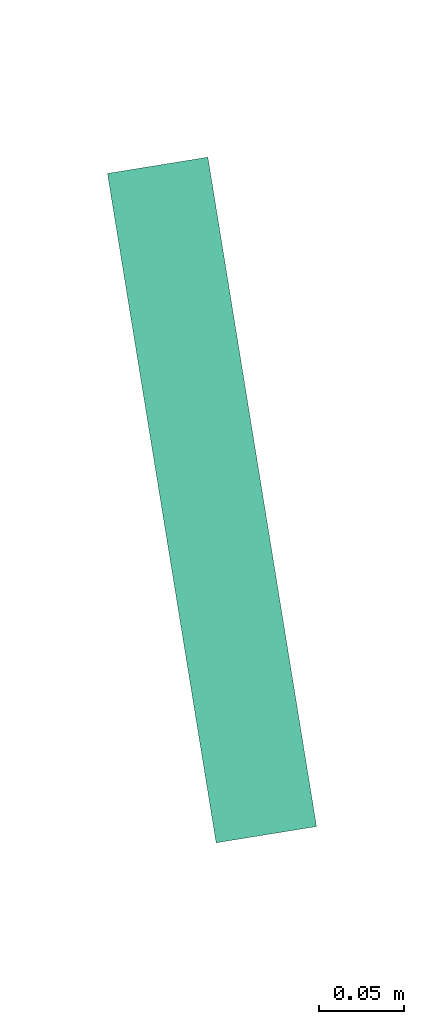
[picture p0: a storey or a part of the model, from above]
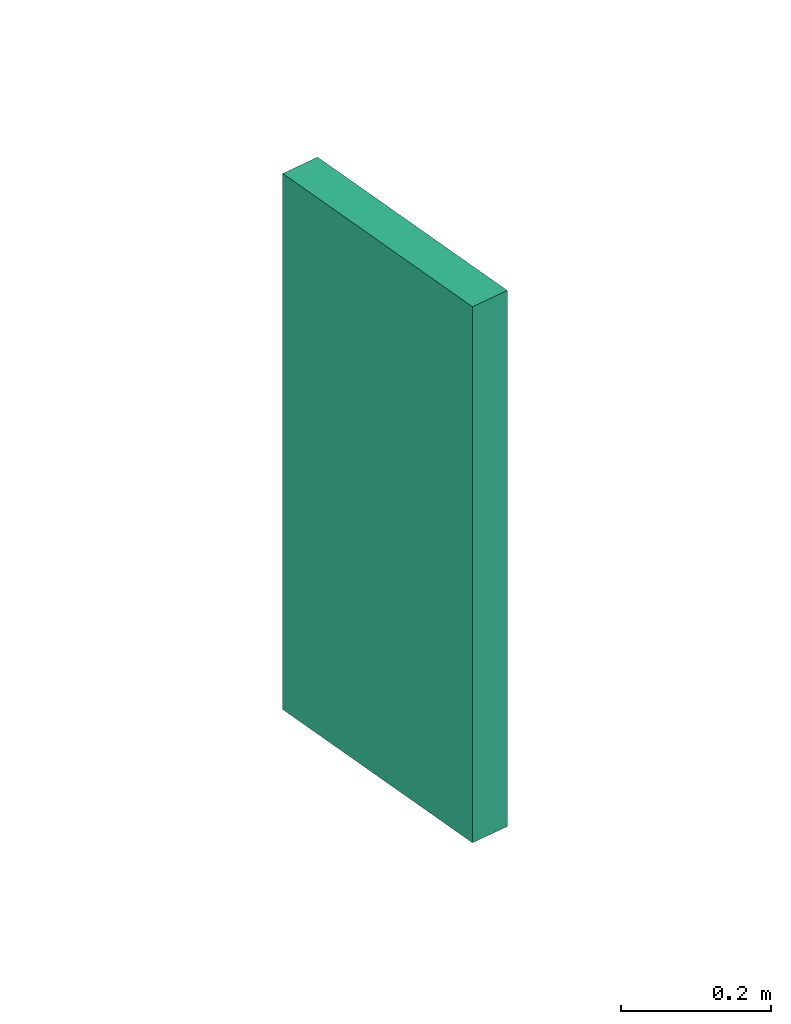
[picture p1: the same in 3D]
Properties of the parts of a building model (IFC2X3), part 1 of 3

# File
Description: ViewDefinition [CoordinationView_V2.0]
File name: BR003-350-101.1 (EDITED).ifc (Edited by Naviate Simple BIM 2022 version 6)
Time: 2026-03-27T09:04:17+01:00
Written by: ODA SDAI 24.12
Made in: Autodesk Revit 25.4.41.14 (ENU) - IFC 25.4.0.27

# IfcProject, 80052
LongName: T3 - Flesland; Phase: Som Bygget

# IfcSite (8)
RefElevation: 0 mm
Name | RefLatitude | RefLongitude
2 x Default | 60, 17, 20, 899658 | 5, 13, 37, 654037
3 x Default | 42, 24, 53, 508911 | -71, -15, -29, -58837
3 x Default | 59, 54, 49, 759826 | 10, 44, 19, 467315

# IfcBuilding (8)
Name
TOO | LongName: TOO
7 x 

# IfcBuildingStorey: Level:8mm Head (13)
Name | LongName | Elevation (mm)
Nivå B | Nivå B | 44700
7 x Nivå D | Nivå D | 51000
4 x Nivå C | Nivå C | 48160
Nivå E | Nivå E | 55630

# IfcBuildingStorey: Level:Kote Ny (3)
In: TOO
Name | LongName | Elevation (mm)
Nivå B | Nivå B | 44700
Nivå D-H01 | Nivå D-H01 | 51000
Himlingsplan Nivå E | Himlingsplan Nivå E | 55630

# IfcBeam: A223 - DLB Prefab. Betongbjelke:A223 - DLB Prefab. Betongbjelke - 815 x 700 x 400 mm (6)
In: Nivå D-H01
Type - PredefinedType: BEAM
ePset_Simplebim - Assembly Level: Leaf
ePset_SimplebimBasicQuantities - Height (Simplebim): 815 mm; Width (Simplebim): 700 mm
Pset_BeamCommon - Reference: A223 - DLB Prefab. Betongbjelke:A223 - DLB Prefab. Betongbjelke - 815 x 700 x 400 mm
Name (A223 - DLB Prefab. Betongbjelke:A223 - DLB Prefab. Betongbjelke - 815 x 700 x 400 mm:...) | Length (Simplebim) (mm) | Area, sides, net (Simplebim) (m2) | Volume, net (Simplebim) (m3) | Weight, as steel (Simplebim) (kg) | Splitting
28208053 | 8974.6 | 28.097 | 4.05652 | 31843.7 | ORIGINAL
28208110 | 8974.6 | 28.097 | 4.05652 | 31843.7 | ORIGINAL
28208108 | 5597 | 17.8638 | 2.52998 | 19860.3 | RESULT
23469193 | 767 | 3.22892 | 0.34682 | 2722.53 | RESULT
14871710 | 768 | 3.22892 | 0.34682 | 2722.53 | RESULT
28208055 | 5597 | 17.8638 | 2.52998 | 19860.3 | RESULT

# IfcBuildingElementProxy: 1612510-0001:Junction box1 (6)
In: Nivå D
Type - Material: <Unnamed>
ePset_Simplebim - Assembly Level: Leaf
ePset_LocationTool - Splitting: ORIGINAL
ePset_SimplebimBasicQuantities - Area, largest surface, net (Simplebim): 0.0121 m2; Volume, net (Simplebim): 0.000515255 m3; Length (Simplebim): 110 mm; Height (Simplebim): 110 mm; Thickness (Simplebim): 46 mm
Pset_BuildingElementProxyCommon - Reference: 1612510-0001:Junction box1
AVINOR - 08_Status: S4; 07_Fase: F90
Name (1612510-0001:Junction box1:...) | 05_ID-nummer
14241557 | +BR003=360.SB102-LC001
14241558 | +BR003=360.SB102-LC002
14241559 | +BR003=360.SB121-FA002
14241560 | +BR003=360.SB121-FA002
14241561 | +BR003=360.SB113-FA001
14296219 | +BR003=360.SB121-FA002 | Group: 5

# IfcBuildingElementProxy: 244 - Albuebryter:244 - Albuebryter (2)
In: Nivå D-H01
Type - Material: Ramme Plast, <Unnamed>
ePset_Simplebim - Assembly Level: Leaf
ePset_LocationTool - Splitting: ORIGINAL
ePset_SimplebimBasicQuantities - Area, largest surface, net (Simplebim): 0.0480408 m2; Volume, net (Simplebim): 0.000518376 m3; Thickness (Simplebim): 27.7678 mm; Height (Simplebim): 250 mm; Length (Simplebim): 79.9999 mm
Pset_BuildingElementProxyCommon - Reference: 244 - Albuebryter:244 - Albuebryter
Name (244 - Albuebryter:244 - Albuebryter:...)
37698599
37866248

# IfcBuildingElementProxy: 274-stikkontakt (306):274-stikkontakt (306) (2)
In: Nivå D-H01
Type - Material: <Unnamed>
ePset_Simplebim - Assembly Level: Leaf
Pset_BuildingElementProxyCommon - Reference: 274-stikkontakt (306):274-stikkontakt (306)
ePset_LocationTool - Splitting: ORIGINAL
ePset_SimplebimBasicQuantities - Volume, net (Simplebim): 0.00007225 m3; Height (Simplebim): 85 mm; Thickness (Simplebim): 10 mm; Area, largest surface, net (Simplebim): 0.007225 m2; Length (Simplebim): 85 mm
Name (274-stikkontakt (306):274-stikkontakt (306):...)
35439303
35460235

# IfcBuildingElementProxy: A275 - 3D FOLIE PIKTOGRAM HCWC:A275 - 3D FOLIE PIKTOGRAM HCWC, A275 - 3D FOLIE PIKTOGRAM HCWC:A275 - 3D FOLIE PIKTOGRAM HCWC:38297930
In: Nivå D-H01
Type - Material: <Unnamed>
ePset_Simplebim - Assembly Level: Leaf
ePset_LocationTool - Splitting: ORIGINAL
ePset_SimplebimBasicQuantities - Length (Simplebim): 300.595 mm; Height (Simplebim): 232.845 mm; Thickness (Simplebim): 48.6239 mm; Area, largest surface, net (Simplebim): 0.0134453 m2; Volume, net (Simplebim): 0.00022648 m3
Pset_BuildingElementProxyCommon - Reference: A275 - 3D FOLIE PIKTOGRAM HCWC:A275 - 3D FOLIE PIKTOGRAM HCWC

# IfcBuildingElementProxy: A275 - 3D FOLIE PIKTOGRAM stellebord:A275 - 3D FOLIE PIKTOGRAM stellebord, A275 - 3D FOLIE PIKTOGRAM stellebord:A275 - 3D FOLIE PIKTOGRAM stellebord:38650796
In: Nivå D-H01
Type - Material: <Unnamed>
ePset_Simplebim - Assembly Level: Leaf
ePset_LocationTool - Splitting: ORIGINAL
ePset_SimplebimBasicQuantities - Area, largest surface, net (Simplebim): 0.0115962 m2; Length (Simplebim): 241.472 mm; Volume, net (Simplebim): 0.000257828 m3; Height (Simplebim): 242.647 mm; Thickness (Simplebim): 37.4759 mm
Pset_BuildingElementProxyCommon - Reference: A275 - 3D FOLIE PIKTOGRAM stellebord:A275 - 3D FOLIE PIKTOGRAM stellebord

# IfcBuildingElementProxy: BRANNSPJELD - - SZ010T:BRANNSPJELD - FDT/R-1250-1000 - SZ010T, BRANNSPJELD - - SZ010T:BRANNSPJELD - FDT/R-1250-1000 - SZ010T:5717189
In: Nivå E
Type - Material: <Unnamed>
ePset_LocationTool - Splitting: ORIGINAL
ePset_Simplebim - Assembly Level: Leaf
AVINOR - 08_Status: S4; 07_Fase: F90; 05_ID-nummer: +BR003=360.SB110-SZ003
Pset_BuildingElementProxyCommon - Reference: BRANNSPJELD - - SZ010T:BRANNSPJELD - FDT/R-1250-1000 - SZ010T
ePset_SimplebimBasicQuantities - Area, largest surface, net (Simplebim): 1.24102 m2; Thickness (Simplebim): 996 mm; Height (Simplebim): 406 mm; Length (Simplebim): 1246 mm; Volume, net (Simplebim): 0.503852 m3
Group: 360.SB110 T

# IfcBuildingElementProxy: BRANNSPJELD - - SZ011T:BRANNSPJELD -C-EI60-125 - SZ011T, BRANNSPJELD - - SZ011T:BRANNSPJELD -C-EI60-125 - SZ011T:13399544
In: Nivå D
Type - Material: <Unnamed>
ePset_Simplebim - Assembly Level: Leaf
Pset_BuildingElementProxyCommon - Reference: BRANNSPJELD - - SZ011T:BRANNSPJELD -C-EI60-125 - SZ011T
ePset_LocationTool - Splitting: ORIGINAL
ePset_SimplebimBasicQuantities - Volume, net (Simplebim): 0.00323555 m3; Area, largest surface, net (Simplebim): 0.103933 m2; Height (Simplebim): 125 mm; Thickness (Simplebim): 125 mm; Length (Simplebim): 265 mm
AVINOR - 08_Status: S4; 07_Fase: F90; 05_ID-nummer: +BR003=360.SB113-SZ053
Group: 360.SB113 T

# IfcBuildingElementProxy: BRANNSPJELD - - SZ011T:BRANNSPJELD -C-EI60-200 - SZ011T, BRANNSPJELD - - SZ011T:BRANNSPJELD -C-EI60-200 - SZ011T:13404535
In: Nivå D
Type - Material: <Unnamed>
ePset_Simplebim - Assembly Level: Leaf
Pset_BuildingElementProxyCommon - Reference: BRANNSPJELD - - SZ011T:BRANNSPJELD -C-EI60-200 - SZ011T
AVINOR - 05_ID-nummer: +BR003=360.SB113-SZ010; 08_Status: S4; 07_Fase: F90
ePset_LocationTool - Splitting: ORIGINAL
ePset_SimplebimBasicQuantities - Volume, net (Simplebim): 0.00828302 m3; Area, largest surface, net (Simplebim): 0.166293 m2; Height (Simplebim): 200 mm; Thickness (Simplebim): 200 mm; Length (Simplebim): 265 mm
Group: 360.SB113 A

# IfcBuildingElementProxy: BRANNSPJELD - - SZ011T:BRANNSPJELD -C-EI60-500 - SZ011T (2)
In: Nivå D
Type - Material: <Unnamed>
ePset_Simplebim - Assembly Level: Leaf
ePset_SimplebimBasicQuantities - Area, largest surface, net (Simplebim): 0.701255 m2; Thickness (Simplebim): 447 mm; Length (Simplebim): 500 mm; Height (Simplebim): 500 mm; Volume, net (Simplebim): 0.0873233 m3
Pset_BuildingElementProxyCommon - Reference: BRANNSPJELD - - SZ011T:BRANNSPJELD -C-EI60-500 - SZ011T
ePset_LocationTool - Splitting: ORIGINAL
AVINOR - 08_Status: S4; 07_Fase: F90
Name (BRANNSPJELD - - SZ011T:BRANNSPJELD -C-EI60-500 - SZ011T:...) | 05_ID-nummer | Group
13271974 | +BR003=360.SB113-SZ049 | 360.SB113 T
13879327 | +BR003=360.SB113-SZ001 | 360.SB113 A

# IfcBuildingElementProxy: BRANNSPJELD - 1 - SZ010T:BRANNSPJELD -R E120-1000-1000 - SZ010T (2)
In: Nivå C
Type - Material: <Unnamed>
ePset_SimplebimBasicQuantities - Length (Simplebim): 996 mm; Thickness (Simplebim): 996 mm; Height (Simplebim): 396 mm; Volume, net (Simplebim): 0.392838 m3; Area, largest surface, net (Simplebim): 0.992016 m2
ePset_Simplebim - Assembly Level: Leaf
AVINOR - 08_Status: S4; 07_Fase: F90
Pset_BuildingElementProxyCommon - Reference: BRANNSPJELD - 1 - SZ010T:BRANNSPJELD -R E120-1000-1000 - SZ010T
ePset_LocationTool - Splitting: ORIGINAL
Name (BRANNSPJELD - 1 - SZ010T:BRANNSPJELD -R E120-1000-1000 - SZ010T:...) | 05_ID-nummer | Group
5561560 | +BR003=360.SB111-SZ001 | 360.SB111 A
5561591 | +BR003=360.SB112-SZ001 | 360.SB112 A

# IfcBuildingElementProxy: BRANNSPJELD - 1 - SZ06T:BRANNSPJELD -C-EI120-500 - SZ06T, BRANNSPJELD - 1 - SZ06T:BRANNSPJELD -C-EI120-500 - SZ06T:13082281
In: Nivå D
Type - Material: <Unnamed>
ePset_Simplebim - Assembly Level: Leaf
ePset_LocationTool - Splitting: ORIGINAL
Pset_BuildingElementProxyCommon - Reference: BRANNSPJELD - 1 - SZ06T:BRANNSPJELD -C-EI120-500 - SZ06T
AVINOR - 08_Status: S4; 07_Fase: F90; 05_ID-nummer: +BR003=360.SB113-SZ037
ePset_SimplebimBasicQuantities - Area, largest surface, net (Simplebim): 0.68942 m2; Height (Simplebim): 443 mm; Length (Simplebim): 496 mm; Thickness (Simplebim): 496 mm; Volume, net (Simplebim): 0.0851628 m3
Group: 360.SB113 T

# IfcBuildingElementProxy: Bryter 1-polet påvegg:2006015 (2)
In: Nivå D
Type - Material: Material1
ePset_LocationTool - Splitting: ORIGINAL
ePset_Simplebim - Assembly Level: Leaf
Pset_BuildingElementProxyCommon - Reference: Bryter 1-polet påvegg:2006015
AVINOR - 08_Status: S4; 07_Fase: F90; 05_ID-nummer: +BR003=439.OO001-XS001T
ePset_SimplebimBasicQuantities - Volume, net (Simplebim): 0.000041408 m3; Thickness (Simplebim): 12 mm; Length (Simplebim): 60 mm; Height (Simplebim): 60 mm; Area, largest surface, net (Simplebim): 0.0036 m2
Name (Bryter 1-polet påvegg:2006015:...)
14247189
14247595

# IfcBuildingElementProxy: Dobbel stikk i tak m_boks 2P+J PH:Earthed reces socket c2 (2)
In: Nivå D
Type - Material: <Unnamed>
ePset_Simplebim - Assembly Level: Leaf
ePset_LocationTool - Splitting: ORIGINAL
AVINOR - 08_Status: S4; 07_Fase: F90; 05_ID-nummer: +BR003=439.OO001-UE001T
ePset_SimplebimBasicQuantities - Area, largest surface, net (Simplebim): 0.010086 m2; Height (Simplebim): 19 mm; Thickness (Simplebim): 82 mm; Length (Simplebim): 123 mm; Volume, net (Simplebim): 0.000118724 m3
Pset_BuildingElementProxyCommon - Reference: Dobbel stikk i tak m_boks 2P+J PH:Earthed reces socket c2
Name (Dobbel stikk i tak m_boks 2P+J PH:Earthed reces socket c2:...) | Group
4070366 | =433.SD121-KW28
5570882 | =433.SD121-KW27

# IfcBuildingElementProxy: Dobbel stikk på vegg 2P+J hor PH:EARTHED-SOCKET-2(HOR) (5)
In: Nivå D
Type - Material: <Unnamed>
ePset_SimplebimBasicQuantities - Thickness (Simplebim): 45.1 mm; Length (Simplebim): 98.2 mm; Area, largest surface, net (Simplebim): 0.006174 m2; Height (Simplebim): 63.2 mm; Volume, net (Simplebim): 0.0000063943 m3
ePset_Simplebim - Assembly Level: Leaf
Pset_BuildingElementProxyCommon - Reference: Dobbel stikk på vegg 2P+J hor PH:EARTHED-SOCKET-2(HOR)
ePset_LocationTool - Splitting: ORIGINAL
AVINOR - 08_Status: S4; 07_Fase: F90; 05_ID-nummer: +BR003=439.OO001-UE001T
Name (Dobbel stikk på vegg 2P+J hor PH:EARTHED-SOCKET-2(HOR):...) | Group
14252326 | =433.SD121-KW67
14252465 | =433.SD121-KW67
14252483 | =433.SD121-KW67
14252511 | =433.SD121-KW67
18195576 | 6

# IfcBuildingElementProxy: Dobbel stikk vegg innf 2P+J vert PH:RECESSED-EARTHED-SOCKET-2(VER) (4)
In: Nivå D
Type - Material: Material3, Material2, Material1
ePset_Simplebim - Assembly Level: Leaf
ePset_LocationTool - Splitting: ORIGINAL
AVINOR - 08_Status: S4; 07_Fase: F90; 05_ID-nummer: +BR003=439.OO001-UE001T
Pset_BuildingElementProxyCommon - Reference: Dobbel stikk vegg innf 2P+J vert PH:RECESSED-EARTHED-SOCKET-2(VER)
ePset_SimplebimBasicQuantities - Volume, net (Simplebim): 0.000114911 m3; Length (Simplebim): 91.4039 mm; Area, largest surface, net (Simplebim): 0.00984 m2; Thickness (Simplebim): 83.0083 mm; Height (Simplebim): 103.761 mm
Name (Dobbel stikk vegg innf 2P+J vert PH:RECESSED-EARTHED-SOCKET-2(VER):...) | Group
6345599
15224680 | =433.SD121-KW149
18268836 | 8
18268866 | 7 | AVINOR - 01_Lufthavnkode: ENBR

# IfcBuildingElementProxy: Dome-camera-ceiling-0001:Dome camera ceiling, Dome-camera-ceiling-0001:Dome camera ceiling:7268528
In: Nivå D
Type - Material: <Unnamed>
ePset_Simplebim - Assembly Level: Leaf
Pset_BuildingElementProxyCommon - Reference: Dome-camera-ceiling-0001:Dome camera ceiling
ePset_SimplebimBasicQuantities - Height (Simplebim): 70 mm; Volume, net (Simplebim): 0.000340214 m3; Length (Simplebim): 100 mm; Thickness (Simplebim): 100 mm; Area, largest surface, net (Simplebim): 0.00942921 m2
AVINOR - 08_Status: S1; 07_Fase: F30
ePset_LocationTool - Splitting: ORIGINAL

# IfcBuildingElementProxy: El-ford-Skap:El-ford-Skap_001, El-ford-Skap:=435.SD121:14157169
In: Nivå D
Type - Material: <Unnamed>
ePset_Simplebim - Assembly Level: Leaf
AVINOR - 08_Status: S4; 07_Fase: F90; 05_ID-nummer: +BR003=435.SD121
ePset_LocationTool - Splitting: ORIGINAL
Pset_BuildingElementProxyCommon - Reference: El-ford-Skap:El-ford-Skap_001
ePset_SimplebimBasicQuantities - Area, largest surface, net (Simplebim): 1.2 m2; Thickness (Simplebim): 300 mm; Length (Simplebim): 600 mm; Height (Simplebim): 2000 mm; Volume, net (Simplebim): 0.36 m3
Group: 6; 5; 8; 7

# IfcBuildingElementProxy: Enkel stikk på vegg 2P+J IP44 PH:COVERED-SOCKET- 1, Enkel stikk på vegg 2P+J IP44 PH:COVERED-SOCKET- 1:4155008
In: Nivå D
Type - Material: <Unnamed>
ePset_Simplebim - Assembly Level: Leaf
ePset_LocationTool - Splitting: ORIGINAL
AVINOR - 08_Status: S4; 07_Fase: F90; 05_ID-nummer: +BR003=439.OO001-UE001T
ePset_SimplebimBasicQuantities - Thickness (Simplebim): 55.1845 mm; Area, largest surface, net (Simplebim): 0.002516 m2; Height (Simplebim): 87.4696 mm; Volume, net (Simplebim): 0.00000428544 m3; Length (Simplebim): 68.5963 mm
Pset_BuildingElementProxyCommon - Reference: Enkel stikk på vegg 2P+J IP44 PH:COVERED-SOCKET- 1
Group: =433.SD121-KW29

# IfcBuildingElementProxy: Enkel stikk på vegg 2P+J PH:EARTHED-SOCKET-1 (3)
In: Nivå D
Type - Material: Material3, Material2, Material1
ePset_Simplebim - Assembly Level: Leaf
Pset_BuildingElementProxyCommon - Reference: Enkel stikk på vegg 2P+J PH:EARTHED-SOCKET-1
ePset_SimplebimBasicQuantities - Volume, net (Simplebim): 0.000137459 m3; Thickness (Simplebim): 45.0114 mm; Height (Simplebim): 63 mm; Length (Simplebim): 63 mm; Area, largest surface, net (Simplebim): 0.003969 m2
AVINOR - 08_Status: S4; 07_Fase: F90; 05_ID-nummer: +BR003=439.OO001-UE001T
ePset_LocationTool - Splitting: ORIGINAL
Name (Enkel stikk på vegg 2P+J PH:EARTHED-SOCKET-1:...) | Group
5560765 | =433.SD121-KW59
5560766 | =433.SD121-KW30
14432721

# IfcBuildingElementProxy: FANCOIL--LC006T:FANCOIL--LC006T (2)
In: Nivå D
Type - Material: <Unnamed>
ePset_Simplebim - Assembly Level: Leaf
AVINOR - 08_Status: S4; 07_Fase: F90
ePset_LocationTool - Splitting: ORIGINAL
Pset_BuildingElementProxyCommon - Reference: FANCOIL--LC006T:FANCOIL--LC006T
ePset_SimplebimBasicQuantities - Volume, net (Simplebim): 0.126 m3; Height (Simplebim): 350 mm; Length (Simplebim): 600 mm; Thickness (Simplebim): 600 mm; Area, largest surface, net (Simplebim): 0.36 m2
Group: 370.SB102 T
Name (FANCOIL--LC006T:FANCOIL--LC006T:...) | 05_ID-nummer
21083713 | +BR003=370.SB102-LC001
21083752 | +BR003=370.SB102-LC002

# IfcBuildingElementProxy: Høyttaler innfelt 16cm:Bass speaker PC-2369EN /6W (4)
In: Nivå D
Type - Material: Material1, Material2
ePset_Simplebim - Assembly Level: Leaf
ePset_LocationTool - Splitting: ORIGINAL
ePset_SimplebimBasicQuantities - Area, largest surface, net (Simplebim): 0.0479856 m2; Length (Simplebim): 242.889 mm; Height (Simplebim): 170.098 mm; Volume, net (Simplebim): 0.00448694 m3; Thickness (Simplebim): 229.877 mm
AVINOR - 08_Status: S1; 07_Fase: F30
Pset_BuildingElementProxyCommon - Reference: Høyttaler innfelt 16cm:Bass speaker PC-2369EN /6W
Name (Høyttaler innfelt 16cm:Bass speaker PC-2369EN /6W:...)
7046618
7046619
7046620
7046621

# IfcBuildingElementProxy: Høyttaler line array:TOA Sr-S4s, Høyttaler line array:TOA Sr-S4s:10112814
In: Nivå D
Type - Material: <Unnamed>
ePset_Simplebim - Assembly Level: Leaf
ePset_LocationTool - Splitting: ORIGINAL
ePset_SimplebimBasicQuantities - Area, largest surface, net (Simplebim): 0.270276 m2; Volume, net (Simplebim): 0.0432442 m3; Thickness (Simplebim): 160 mm; Length (Simplebim): 303 mm; Height (Simplebim): 892 mm
Pset_BuildingElementProxyCommon - Reference: Høyttaler line array:TOA Sr-S4s
AVINOR - 08_Status: S1; 07_Fase: F30

# IfcBuildingElementProxy: INNREGULERINGSPJELD - - SR001T:INNREGULERINGSPJELD - IRIS-025 - SR001T, INNREGULERINGSPJELD - - SR001T:INNREGULERINGSPJELD - IRIS-025 - SR001T:22035496
In: Nivå D
Type - Material: <Unnamed>
ePset_Simplebim - Assembly Level: Leaf
Pset_BuildingElementProxyCommon - Reference: INNREGULERINGSPJELD - - SR001T:INNREGULERINGSPJELD - IRIS-025 - SR001T
ePset_SimplebimBasicQuantities - Thickness (Simplebim): 48 mm; Volume, net (Simplebim): 0.00234425 m3; Area, largest surface, net (Simplebim): 0.0488385 m2; Length (Simplebim): 250 mm; Height (Simplebim): 250 mm
AVINOR - 08_Status: S4; 07_Fase: F90; 05_ID-nummer: +BR003=360.SB113-SR001T
ePset_LocationTool - Splitting: ORIGINAL
Group: 360.SB113 A

# IfcBuildingElementProxy: INNREGULERINGSPJELD - - SR001T:INNREGULERINGSPJELD - IRIS-031 - SR001T (3)
In: Nivå D
Type - Material: <Unnamed>
Pset_BuildingElementProxyCommon - Reference: INNREGULERINGSPJELD - - SR001T:INNREGULERINGSPJELD - IRIS-031 - SR001T
ePset_Simplebim - Assembly Level: Leaf
ePset_SimplebimBasicQuantities - Volume, net (Simplebim): 0.00372173 m3; Area, largest surface, net (Simplebim): 0.0775361 m2; Thickness (Simplebim): 48 mm; Length (Simplebim): 315 mm; Height (Simplebim): 315 mm
ePset_LocationTool - Splitting: ORIGINAL
AVINOR - 08_Status: S4; 07_Fase: F90; 05_ID-nummer: +BR003=360.SB113-SR001T
Group: 360.SB113 A
Name (INNREGULERINGSPJELD - - SR001T:INNREGULERINGSPJELD - IRIS-031 - SR001T:...)
22035648
22063609
22063637

# IfcBuildingElementProxy: KJØLEAGGREGAT--IL - Starcold Aggregat:KJØLEAGGREGATMC LC1A B 020 MTIL - Starcold AggregaT, KJØLEAGGREGAT--IL - Starcold Aggregat:KJØLEAGGREGATMC LC1A B 020 MTIL - Starcold AggregaT:22171686
In: Nivå D
Type - Material: <Unnamed>
ePset_Simplebim - Assembly Level: Leaf
AVINOR - 05_ID-nummer: Kjøleaggregat-kom.areal; 08_Status: S4; 07_Fase: F90
ePset_LocationTool - Splitting: ORIGINAL
ePset_SimplebimBasicQuantities - Area, largest surface, net (Simplebim): 0.920419 m2; Height (Simplebim): 1040.02 mm; Volume, net (Simplebim): 0.699519 m3; Thickness (Simplebim): 760 mm; Length (Simplebim): 885 mm
Pset_BuildingElementProxyCommon - Reference: KJØLEAGGREGAT--IL - Starcold Aggregat:KJØLEAGGREGATMC LC1A B 020 MTIL - Starcold AggregaT

# IfcBuildingElementProxy: KJØLEAGGREGAT--IL - Starcold Aggregat:KJØLEAGGREGATMC LC4 B 050 MTIL - Starcold AggregaT, KJØLEAGGREGAT--IL - Starcold Aggregat:KJØLEAGGREGATMC LC4 B 050 MTIL - Starcold AggregaT:22171787
In: Nivå D
Type - Material: <Unnamed>
ePset_Simplebim - Assembly Level: Leaf
AVINOR - 05_ID-nummer: Kjøleaggregat-kom.areal; 08_Status: S4; 07_Fase: F90
Pset_BuildingElementProxyCommon - Reference: KJØLEAGGREGAT--IL - Starcold Aggregat:KJØLEAGGREGATMC LC4 B 050 MTIL - Starcold AggregaT
ePset_SimplebimBasicQuantities - Volume, net (Simplebim): 1.05916 m3; Area, largest surface, net (Simplebim): 1.39363 m2; Height (Simplebim): 1040.02 mm; Thickness (Simplebim): 760 mm; Length (Simplebim): 1340 mm
ePset_LocationTool - Splitting: ORIGINAL

# IfcBuildingElementProxy: Kabinetthøytaler himling 6:Bass speaker BS-678BSW /6W (7)
In: Nivå D
Type - Material: <Unnamed>
ePset_Simplebim - Assembly Level: Leaf
Pset_BuildingElementProxyCommon - Reference: Kabinetthøytaler himling 6:Bass speaker BS-678BSW /6W
ePset_LocationTool - Splitting: ORIGINAL
AVINOR - 08_Status: S1; 07_Fase: F30
ePset_SimplebimBasicQuantities - Height (Simplebim): 170.2 mm; Length (Simplebim): 250 mm; Thickness (Simplebim): 250 mm; Volume, net (Simplebim): 0.000128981 m3; Area, largest surface, net (Simplebim): 0.0966667 m2
Name (Kabinetthøytaler himling 6:Bass speaker BS-678BSW /6W:...)
7046635
7046636
7046638
7046639
7046640
7046641
9752912

# IfcBuildingElementProxy: Kortleser med tastatur1:SECURITY ALARM 3, Kortleser med tastatur1:SECURITY ALARM 3:10954413
In: Nivå D
Type - Material: Material1
Pset_BuildingElementProxyCommon - Reference: Kortleser med tastatur1:SECURITY ALARM 3
ePset_Simplebim - Assembly Level: Leaf
ePset_LocationTool - Splitting: ORIGINAL
AVINOR - 08_Status: S1; 07_Fase: F30
ePset_SimplebimBasicQuantities - Area, largest surface, net (Simplebim): 0.01037 m2; Thickness (Simplebim): 25 mm; Length (Simplebim): 85 mm; Height (Simplebim): 122 mm; Volume, net (Simplebim): 0.00025925 m3

# IfcBuildingElementProxy: LYDDEMPER - - QL006T:LYDDEMPER - 200-900 - QL006T, LYDDEMPER - - QL006T:LYDDEMPER - 200-900 - QL006T:22090765
In: Nivå D
Type - Material: <Unnamed>
ePset_SimplebimBasicQuantities - Volume, net (Simplebim): 0.0403286 m3; Height (Simplebim): 240 mm; Thickness (Simplebim): 240 mm; Length (Simplebim): 896 mm; Area, largest surface, net (Simplebim): 0.674711 m2
ePset_Simplebim - Assembly Level: Leaf
ePset_LocationTool - Splitting: ORIGINAL
Pset_BuildingElementProxyCommon - Reference: LYDDEMPER - - QL006T:LYDDEMPER - 200-900 - QL006T
AVINOR - 08_Status: S4; 07_Fase: F90; 05_ID-nummer: +BR003=360.SB113-QL006T
Group: 360.SB113 OVS

# IfcBuildingElementProxy: LYDDEMPER - - QL006T:LYDDEMPER - 500-900 - QL006T, LYDDEMPER - - QL006T:LYDDEMPER - 500-900 - QL006T:22057957
In: Nivå D
Type - Material: <Unnamed>
ePset_SimplebimBasicQuantities - Height (Simplebim): 540 mm; Thickness (Simplebim): 540 mm; Area, largest surface, net (Simplebim): 1.5181 m2; Volume, net (Simplebim): 0.204164 m3; Length (Simplebim): 896 mm
ePset_Simplebim - Assembly Level: Leaf
ePset_LocationTool - Splitting: ORIGINAL
AVINOR - 08_Status: S4; 07_Fase: F90; 05_ID-nummer: +BR003=360.SB113-QL006T
Pset_BuildingElementProxyCommon - Reference: LYDDEMPER - - QL006T:LYDDEMPER - 500-900 - QL006T
Group: 360.SB113 T

# IfcBuildingElementProxy: LYDDEMPER - - QL007T:LYDDEMPER - 250-1200 - QL007T, LYDDEMPER - - QL007T:LYDDEMPER - 250-1200 - QL007T:22035589
In: Nivå D
Type - Material: <Unnamed>
AVINOR - 08_Status: S4; 07_Fase: F90; 05_ID-nummer: +BR003=360.SB113-QL007T
ePset_Simplebim - Assembly Level: Leaf
Pset_BuildingElementProxyCommon - Reference: LYDDEMPER - - QL007T:LYDDEMPER - 250-1200 - QL007T
ePset_SimplebimBasicQuantities - Height (Simplebim): 290 mm; Thickness (Simplebim): 290 mm; Length (Simplebim): 1226 mm; Area, largest surface, net (Simplebim): 1.11554 m2; Volume, net (Simplebim): 0.0805692 m3
ePset_LocationTool - Splitting: ORIGINAL
Group: 360.SB113 A

# IfcBuildingElementProxy: Move-detector-2-0002:MOVE-DETECTOR-2, Move-detector-2-0002:MOVE-DETECTOR-2:6345598
In: Nivå D
Type - Material: <Unnamed>
ePset_Simplebim - Assembly Level: Leaf
ePset_LocationTool - Splitting: ORIGINAL
ePset_SimplebimBasicQuantities - Thickness (Simplebim): 72.7557 mm; Volume, net (Simplebim): 0.0000355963 m3; Height (Simplebim): 57.7879 mm; Area, largest surface, net (Simplebim): 0.006724 m2; Length (Simplebim): 87.7235 mm
AVINOR - 08_Status: S4; 07_Fase: F90; 05_ID-nummer: +BR003=439.OO001-XS001T
Pset_BuildingElementProxyCommon - Reference: Move-detector-2-0002:MOVE-DETECTOR-2
Group: =433.SD121-KW31

# IfcBuildingElementProxy: Styrepanel_FC:Styrepanel-FC (2)
In: Nivå D
Type - Material: <Unnamed>
ePset_Simplebim - Assembly Level: Leaf
Pset_BuildingElementProxyCommon - Reference: Styrepanel_FC:Styrepanel-FC
ePset_SimplebimBasicQuantities - Thickness (Simplebim): 62.6793 mm; Volume, net (Simplebim): 0.0000430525 m3; Height (Simplebim): 70.9326 mm; Area, largest surface, net (Simplebim): 0.006724 m2; Length (Simplebim): 88.5562 mm
AVINOR - 08_Status: S4; 07_Fase: F90
ePset_LocationTool - Splitting: ORIGINAL
Name (Styrepanel_FC:Styrepanel-FC:...) | 05_ID-nummer
14247711 | +BR003=360.SB102-LC001
14256008 | +BR003=360.SB102-LC002

# IfcBuildingElementProxy: TAPPEVANN KURS - 12 - - OR:TAPPEVANN KURS - 12 - 12 - OR001T, TAPPEVANN KURS - 12 - - OR:TAPPEVANN KURS - 12 - 12 - OR001T:19191870
In: Nivå D
Type - Material: <Unnamed>
ePset_Simplebim - Assembly Level: Leaf
ePset_SimplebimBasicQuantities - Volume, net (Simplebim): 0.04425 m3; Area, largest surface, net (Simplebim): 0.375 m2; Thickness (Simplebim): 118 mm; Length (Simplebim): 500 mm; Height (Simplebim): 750 mm
Pset_BuildingElementProxyCommon - Reference: TAPPEVANN KURS - 12 - - OR:TAPPEVANN KURS - 12 - 12 - OR001T
AVINOR - 08_Status: S4; 07_Fase: F90; 05_ID-nummer: +BR003=310.TO100-OR048
ePset_LocationTool - Splitting: ORIGINAL

# IfcColumn: A222 - HUP:A222 - HUP - 120 x 120 X 8mm (2)
In: Nivå D-H01
Type - PredefinedType: COLUMN; Material: A200 - Metall - Stål
ePset_Simplebim - Assembly Level: Leaf
ePset_SimplebimBasicQuantities - Weight, as steel (Simplebim): 105.941 kg; Area, sides, net (Simplebim): 3.33494 m2; Width (Simplebim): 120 mm; Depth (Simplebim): 120 mm; Height (Simplebim): 3810 mm; Volume, net (Simplebim): 0.0134956 m3
Pset_ColumnCommon - Reference: A222 - HUP:A222 - HUP - 120 x 120 X 8mm
ePset_LocationTool - Splitting: ORIGINAL
Name (A222 - HUP:A222 - HUP - 120 x 120 X 8mm:...)
19811011
19824822

# IfcColumn: A222 - Prefabrikert Sirkulær Betongsøyle:A222 - Prefabrikert Sirkulær Betongsøyle - Ø 600 mm (5)
In: Nivå D-H01
Type - PredefinedType: COLUMN; Material: A200 - Betong
ePset_Simplebim - Assembly Level: Leaf
Pset_ColumnCommon - Reference: A222 - Prefabrikert Sirkulær Betongsøyle:A222 - Prefabrikert Sirkulær Betongsøyle - Ø 600 mm
ePset_SimplebimBasicQuantities - Width (Simplebim): 600 mm; Depth (Simplebim): 600 mm
ePset_LocationTool - Splitting: RESULT
Name (A222 - Prefabrikert Sirkulær Betongsøyle:A222 - Prefabrikert Sirkulær Betongsøyle - Ø 600 mm:...) | Area, sides, net (Simplebim) (m2) | Volume, net (Simplebim) (m3) | Weight, as steel (Simplebim) (kg) | Height (Simplebim) (mm)
14902123 | 7.90677 | 1.1815 | 9274.79 | 4200
14901576 | 7.90677 | 1.1815 | 9274.79 | 4200
5212049 | 8.32093 | 1.24339 | 9760.61 | 4420
14901970 | 7.90677 | 1.1815 | 9274.79 | 4200
1233260 | 8.32093 | 1.24339 | 9760.61 | 4420

# IfcCovering: Compound Ceiling:A256 A01 Akustiske plater direkkemonert (4)
In: Nivå B
Type - PredefinedType: CEILING
ePset_LocationTool - Splitting: RESULT
ePset_Simplebim - Assembly Level: Leaf
Pset_CoveringCommon - Reference: Compound Ceiling:A256 A01 Akustiske plater direkkemonert
ePset_SimplebimBasicQuantities - Height (Simplebim): 50 mm
Name (Compound Ceiling:A256 A01 Akustiske plater direkkemonert:...) | Volume, net (Simplebim) (m3) | Area, largest surface, net (Simplebim) (m2) | Width (Simplebim) (mm) | Length (Simplebim) (mm)
25887524 | 1.3851 | 27.702 | 1800 | 15390
26811529 | 3.24049 | 64.8101 | 5405 | 14431
25469538 | 0.135004 | 2.70008 | 1295 | 2085
25937099 | 0.11655 | 2.331 | 1295 | 1800

# IfcCovering: Compound Ceiling:A257 MF04 Publikum Systemhimling 600x600 mm, Compound Ceiling:A257 MF04 Publikum Systemhimling 600x600 mm:10130142
In: Nivå D-H01
Type - PredefinedType: CEILING
Material: _NSW Standard 95 mm, A257 - Metall - Aluminum - 600 x 600mm 5 mm
ePset_Simplebim - Assembly Level: Leaf
ePset_SimplebimBasicQuantities - Length (Simplebim): 2510 mm; Volume, net (Simplebim): 0.547867 m3; Height (Simplebim): 100 mm; Width (Simplebim): 2220 mm; Area, largest surface, net (Simplebim): 5.47867 m2
Pset_CoveringCommon - Reference: Compound Ceiling:A257 MF04 Publikum Systemhimling 600x600 mm
ePset_LocationTool - Splitting: ORIGINAL

# IfcCovering: Duct Insulation:EI 60-30 (43)
In: Nivå D
Type - PredefinedType: INSULATION
ePset_Simplebim - Assembly Level: Leaf
ePset_LocationTool - Splitting: ORIGINAL
AVINOR - 08_Status: S4; 07_Fase: F90; 05_ID-nummer: +BR003=360.TO001-BI002T
Pset_CoveringCommon - Reference: Duct Insulation:EI 60-30
Name (Duct Insulation:EI 60-30:...) | Volume, net (Simplebim) (m3) | Width (Simplebim) (mm) | Height (Simplebim) (mm) | Length (Simplebim) (mm) | Area, largest surface, net (Simplebim) (m2)
22034092 | 0.0440498 | 180 | 560 | 560 | 0.316164
22034093 | 0.0507049 | 344.803 | 560 | 594.472 | 0.363561
22034094 | 0.0305196 | 201.879 | 560 | 567.496 | 0.239783
22034095 | 0.180211 | 780 | 670.328 | 825.891 | 1.34361
22034096 | 0.402592 | 560 | 560 | 1647.76 | 2.89215
22034098 | 0.971322 | 560 | 560 | 3974.33 | 6.97712
22034578 | 0.180211 | 780 | 560 | 780 | 1.34361
22036224 | 0.108767 | 460 | 460 | 660 | 0.951788
22036225 | 0.109031 | 530 | 460 | 600 | 0.329362
22036226 | 0.0807515 | 460 | 460 | 490 | 0.70663
22036227 | 0.0152774 | 75 | 560 | 560 | 0.244721
22036229 | 0.089043 | 460 | 460 | 540.312 | 0.779186
22036231 | 0.0118494 | 375 | 107.833 | 375 | 0.126873
22036232 | 0.00507581 | 30.8 | 460 | 460 | 0.164799
22036233 | 0.0117579 | 375 | 107 | 375 | 0.125894
22036235 | 0.00507581 | 30.8 | 460 | 460 | 0.164799
22036250 | 0.0947594 | 460 | 460 | 575 | 0.829209
22036251 | 0.0216045 | 131.096 | 460 | 460 | 0.189054
22036252 | 0.12136 | 460 | 460 | 736.41 | 1.06198
22036253 | 0.0974432 | 630 | 460 | 630 | 0.883822
22036254 | 0.00507581 | 30.8 | 460 | 460 | 0.164799
22036268 | 0.0118101 | 107.833 | 375 | 375 | 0.126771
22036269 | 0.365247 | 375 | 375 | 3344.73 | 3.92827
22036270 | 0.00569515 | 52 | 375 | 375 | 0.109522
22036271 | 0.174863 | 375 | 375 | 1596.42 | 1.87603
22036272 | 0.0406581 | 375 | 370 | 375 | 0.435327
22036273 | 0.0494316 | 375 | 502.5 | 502.5 | 0.524905
22057835 | 0.326799 | 560 | 560 | 1335.36 | 2.34468
22057838 | 0.150504 | 560 | 560 | 615 | 1.08023
22058200 | 0.200568 | 460 | 460 | 1215.64 | 1.75279
22058381 | 0.0325513 | 315 | 460 | 482.776 | 0.297579
22058382 | 0.0306953 | 390.77 | 460 | 491.192 | 0.267951
22058387 | 0.0325513 | 315 | 460 | 482.776 | 0.297579
22063470 | 0.0118494 | 375 | 107.833 | 375 | 0.126874
22063492 | 0.0160435 | 375 | 146 | 375 | 0.171779
22063621 | 0.00571411 | 375 | 52 | 375 | 0.10988
22063644 | 0.0385702 | 375 | 351 | 375 | 0.41298
22063645 | 0.00571411 | 375 | 52 | 375 | 0.109883
22064324 | 0.0353835 | 375 | 322 | 375 | 0.378855
22077347 | 0.081248 | 460 | 460 | 493.013 | 0.710975
22077434 | 0.0325513 | 315 | 460 | 482.776 | 0.297579
22077435 | 0.0141605 | 304.167 | 441.192 | 460 | 0.165355
22077440 | 0.0325513 | 315 | 460 | 482.776 | 0.297579

# IfcCovering: Duct Insulation:MuT030 (26)
Type - PredefinedType: INSULATION
ePset_Simplebim - Assembly Level: Leaf
AVINOR - 08_Status: S4; 07_Fase: F90; 05_ID-nummer: +BR003=360.TO001-BI001T
Pset_CoveringCommon - Reference: Duct Insulation:MuT030
Name (Duct Insulation:MuT030:...) | In | Splitting | Height (Simplebim) (mm) | Volume, net (Simplebim) (m3) | Width (Simplebim) (mm) | Area, largest surface, net (Simplebim) (m2) | Length (Simplebim) (mm)
16892361 | Nivå C | ORIGINAL | 460 | 0.203638 | 460 | 1.77973 | 1234.31
16892362 | Nivå C | ORIGINAL | 630 | 0.0974432 | 460 | 0.883822 | 630
16892364 | Nivå C | ORIGINAL | 460 | 0.0479524 | 445.477 | 0.440892 | 509.792
16905592 | Nivå D | ORIGINAL | 252.133 | 0.350111 | 1060 | 1.3886 | 1310
16905594 | Nivå C | ORIGINAL | 572.646 | 0.795176 | 1060 | 1.3886 | 1310
16905714 | Nivå D | ORIGINAL | 560 | 0.0930422 | 380.196 | 0.667802 | 560
16905715 | Nivå D | ORIGINAL | 780 | 0.180211 | 560 | 1.34361 | 780
16905716 | Nivå C | ORIGINAL | 386.543 | 0.0947233 | 560 | 0.6792 | 560
16905780 | Nivå C | ORIGINAL | 551.543 | 0.0893603 | 560 | 0.67158 | 624.437
16905781 | Nivå D | ORIGINAL | 560 | 0.606443 | 560 | 4.34842 | 2474.75
16905800 | Nivå D | ORIGINAL | 185.028 | 0.00783397 | 185 | 0.17003 | 292.942
16905801 | Nivå D | ORIGINAL | 165.356 | 0.0013064 | 165.356 | 0.0283538 | 185.026
16905802 | Nivå D | ORIGINAL | 185.005 | 0.00238379 | 153.805 | 0.0242007 | 194.519
16905803 | Nivå D | ORIGINAL | 185 | 0.0192784 | 185 | 0.419112 | 722.958
16905804 | Nivå D | ORIGINAL | 185 | 0.00238379 | 153.796 | 0.0242007 | 194.519
16905805 | Nivå D | ORIGINAL | 311.841 | 0.00835874 | 220 | 0.152562 | 311.841
16905806 | Nivå D | ORIGINAL | 220 | 0.00649253 | 172.764 | 0.119065 | 220.001
16905809 | Nivå D | ORIGINAL | 185.009 | 0.0304689 | 185 | 0.662488 | 1142.77
16905810 | Nivå D | ORIGINAL | 185 | 0.00162537 | 61.1647 | 0.0354464 | 185
16905811 | Nivå D | ORIGINAL | 185.002 | 0.00645957 | 185 | 0.140872 | 243.078
16905812 | Nivå D | ORIGINAL | 220 | 0.00239268 | 75.0019 | 0.0487985 | 220
16905843 | Nivå D | ORIGINAL | 400 | 0.566945 | 1310 | 1.82521 | 1310
18047927 | Nivå D | ORIGINAL | 220 | 0.00440114 | 190.919 | 0.0782788 | 234.645
18047932 | Nivå D | ORIGINAL | 220 | 0.00440117 | 190.92 | 0.0782793 | 234.645
16905937 | Nivå D | RESULT | 1310 | 4.48946 | 1310 | 1.341 | 3348
16905733 | Nivå D | RESULT | 220 | 0.0197545 | 220 | 0.0376796 | 524

# IfcCurtainWall: Curtain Wall:Curtain Wall Standard (Bruk kun denne) (2)
In: Nivå D-H01
ePset_Simplebim - Assembly Level: Topmost
Pset_CurtainWallCommon - Reference: Curtain Wall:Curtain Wall Standard (Bruk kun denne)
Name (Curtain Wall:Curtain Wall Standard (Bruk kun denne):...) | Volume, net (Simplebim) (m3) | Width (mm) | Height (mm) | Length (mm)
16536474 | 5.09154 | 365 | 4600 | 53820
42233614 | 0.0189 | 10 | 2700 | 700

# IfcDistributionControlElement: Brannalarm Røykdetektor m-v-lys:SMOKE DETECTOR2, Brannalarm Røykdetektor m-v-lys:SMOKE DETECTOR2:3716187
In: Nivå D
Type - Material: <Unnamed>
ePset_Simplebim - Assembly Level: Leaf
ePset_LocationTool - Splitting: ORIGINAL
AVINOR - 08_Status: S4; 07_Fase: F90; 05_ID-nummer: +BR003=542.SD103-RY3030

# IfcDistributionControlElement: Brannalarm Røykdetektor:SMOKE DETECTOR2 (8)
Type - Material: <Unnamed>
ePset_Simplebim - Assembly Level: Leaf
AVINOR - 08_Status: S4; 07_Fase: F90
ePset_LocationTool - Splitting: ORIGINAL
Name (Brannalarm Røykdetektor:SMOKE DETECTOR2:...) | In | 05_ID-nummer
2640049 | Nivå B | +BR003=542.SB101-RY2048
3721035 | Nivå D | +BR003=542.SD103-RY3028
4462737 | Nivå B | +BR003=542.SB101-RY2015
4570552 | Nivå B | +BR003=542.SB101-RY2017
4571193 | Nivå B | +BR003=542.SB101-RY2016
6727980 | Nivå D | +BR003=542.SD103-RY3034
6727988 | Nivå D | +BR003=542.SD103-RY3033
14231547 | Nivå D | +BR003=542.SD103-RY3031

# IfcDistributionControlElement: Brannalarm Varmedetektor:Heating detector ceiling, Brannalarm Varmedetektor:Heating detector ceiling:14231688
In: Nivå D
Type - Material: <Unnamed>
ePset_LocationTool - Splitting: ORIGINAL
AVINOR - 08_Status: S4; 07_Fase: F90; 05_ID-nummer: +BR003=542.SD103-RZ3032
ePset_Simplebim - Assembly Level: Leaf

# IfcDistributionControlElement: Brannalarm adresseledd:I/O UNIT, Brannalarm adresseledd:I/O UNIT:18275993
In: Nivå D
Type - Material: <Unnamed>
ePset_Simplebim - Assembly Level: Leaf
ePset_LocationTool - Splitting: ORIGINAL
AVINOR - 08_Status: S4; 07_Fase: F90; 05_ID-nummer: +BR003=542.SD103-XZ30XX

# IfcDistributionControlElement: bryter_brann:4ed9449eabe84ffd8883e117f7a2c9, bryter_brann:4ed9449eabe84ffd8883e117f7a2c9:18276112
In: Nivå D
Type - Material: <Unnamed>
ePset_Simplebim - Assembly Level: Leaf
ePset_LocationTool - Splitting: ORIGINAL

# IfcDistributionPort (673)
Description: Flow
ePset_Simplebim - Assembly Level: Leaf
Name | FlowDirection | Group
OutPort_28710394_1 | SOURCE
OutPort_37112398_1 | SOURCE
Port_3223138_1 | SOURCEANDSINK
Port_6345598_1 | SOURCEANDSINK
Port_3339015_1 | SOURCEANDSINK
Port_4070366_1 | SOURCEANDSINK
Port_3343406_1 | SOURCEANDSINK
Port_4155008_1 | SOURCEANDSINK
Port_14432721_1 | SOURCEANDSINK
Port_4155016_1 | SOURCEANDSINK
Port_4207578_1 | SOURCEANDSINK
Port_4501853_1 | SOURCEANDSINK
Port_5563343_1 | SOURCEANDSINK
Port_6345599_1 | SOURCEANDSINK
Port_8559565_0 | SOURCEANDSINK
Port_14244948_1 | SOURCEANDSINK
Port_8559565_1 | SOURCEANDSINK
Port_8597597_0 | SOURCEANDSINK
Port_14244947_1 | SOURCEANDSINK
Port_8597597_1 | SOURCEANDSINK
Port_14245988_1 | SOURCEANDSINK
Port_14157169_1 | SOURCEANDSINK
Port_14162308_0 | SOURCEANDSINK
Port_14162498_2 | SOURCEANDSINK
Port_14162308_1 | SOURCEANDSINK
Port_14162498_1 | SOURCEANDSINK
Port_14208431_0 | SOURCEANDSINK
Port_14244947_2 | SOURCEANDSINK
Port_14208431_1 | SOURCEANDSINK
Port_14233376_1 | SOURCEANDSINK
Port_14208431_2 | SOURCEANDSINK
Port_14233037_0 | SOURCEANDSINK
Port_14230975_1 | SOURCEANDSINK
Port_14230976_1 | SOURCEANDSINK
Port_14231547_1 | SOURCEANDSINK
Port_14231688_1 | SOURCEANDSINK
Port_14232792_0 | SOURCEANDSINK
Port_14233284_1 | SOURCEANDSINK
Port_14232792_1 | SOURCEANDSINK
Port_14233037_1 | SOURCEANDSINK
Port_14233287_1 | SOURCEANDSINK
Port_14233246_0 | SOURCEANDSINK
Port_14233284_2 | SOURCEANDSINK
Port_14233246_1 | SOURCEANDSINK
Port_14233287_2 | SOURCEANDSINK
Port_14233326_0 | SOURCEANDSINK
Port_14233376_2 | SOURCEANDSINK
Port_14233326_1 | SOURCEANDSINK
Port_14233537_2 | SOURCEANDSINK
Port_14233464_0 | SOURCEANDSINK
Port_14233537_1 | SOURCEANDSINK
Port_14233464_1 | SOURCEANDSINK
Port_14246518_2 | SOURCEANDSINK
Port_14233636_0 | SOURCEANDSINK
Port_14233636_1 | SOURCEANDSINK
Port_14241557_1 | SOURCEANDSINK
Port_14241558_1 | SOURCEANDSINK
Port_14241559_1 | SOURCEANDSINK
Port_14241560_1 | SOURCEANDSINK
Port_14241561_1 | SOURCEANDSINK
Port_14244919_0 | SOURCEANDSINK
Port_14244919_1 | SOURCEANDSINK
Port_14244920_0 | SOURCEANDSINK
Port_14244920_1 | SOURCEANDSINK
Port_14244921_0 | SOURCEANDSINK
Port_14244921_1 | SOURCEANDSINK
Port_14244922_0 | SOURCEANDSINK
Port_14244922_1 | SOURCEANDSINK
Port_14244923_0 | SOURCEANDSINK
Port_14244923_1 | SOURCEANDSINK
Port_14244924_0 | SOURCEANDSINK
Port_14244924_1 | SOURCEANDSINK
Port_14244926_0 | SOURCEANDSINK
Port_14244926_1 | SOURCEANDSINK
Port_14244927_0 | SOURCEANDSINK
Port_14244927_1 | SOURCEANDSINK
Port_14244928_0 | SOURCEANDSINK
Port_14244928_1 | SOURCEANDSINK
Port_14244929_0 | SOURCEANDSINK
Port_14244929_1 | SOURCEANDSINK
Port_14244948_2 | SOURCEANDSINK
Port_14245065_0 | SOURCEANDSINK
Port_14246025_2 | SOURCEANDSINK
Port_14245065_1 | SOURCEANDSINK
Port_14245987_1 | SOURCEANDSINK
Port_14245132_0 | SOURCEANDSINK
Port_14246024_2 | SOURCEANDSINK
Port_14245132_1 | SOURCEANDSINK
Port_14245162_0 | SOURCEANDSINK
Port_14245987_2 | SOURCEANDSINK
Port_14245162_1 | SOURCEANDSINK
Port_14245988_2 | SOURCEANDSINK
Port_14245866_0 | SOURCEANDSINK
Port_14246024_1 | SOURCEANDSINK
Port_14245866_1 | SOURCEANDSINK
Port_14246025_1 | SOURCEANDSINK
Port_14246517_0 | SOURCEANDSINK
Port_14246518_1 | SOURCEANDSINK
Port_14246517_1 | SOURCEANDSINK
Port_14247711_1 | SOURCEANDSINK
2 x Port_14252326_1 | SOURCEANDSINK
Port_18195576_1 | SOURCEANDSINK
2 x Port_14252465_1 | SOURCEANDSINK
2 x Port_14252483_1 | SOURCEANDSINK
Port_14252511_1 | SOURCEANDSINK
Port_14256008_1 | SOURCEANDSINK
Port_18275993_1 | SOURCEANDSINK
Port_18276112_1 | SOURCEANDSINK
InPort_5561560_1 | SINK | 360.SB111 A
OutPort_13082516_0 | SOURCE | 360.SB111 A
InPort_13082517_0 | SINK | 360.SB111 A
OutPort_5561560_2 | SOURCE | 360.SB111 A
InPort_5561568_1 | SINK | 360.SB111 A
OutPort_13082517_1 | SOURCE | 360.SB111 A
InPort_5561591_1 | SINK | 360.SB112 A
OutPort_13082518_0 | SOURCE | 360.SB112 A
InPort_13082520_0 | SINK | 360.SB112 A
OutPort_5561591_2 | SOURCE | 360.SB112 A
InPort_5561599_1 | SINK | 360.SB112 A
OutPort_13082520_1 | SOURCE | 360.SB112 A
InPort_5717182_0 | SINK | 360.SB110 T
OutPort_5717189_2 | SOURCE | 360.SB110 T
InPort_14228081_0 | SINK | 360.SB110 T
OutPort_5717182_1 | SOURCE | 360.SB110 T
InPort_5717189_1 | SINK | 360.SB110 T
OutPort_5717188_1 | SOURCE | 360.SB110 T
InPort_13271974_1 | SINK | 360.SB113 T
OutPort_7335645_0 | SOURCE | 360.SB113 T
InPort_7335645_1 | SINK | 360.SB113 T
OutPort_7335647_1 | SOURCE | 360.SB113 T
InPort_7335647_2 | SINK | 360.SB113 T
OutPort_13082282_0 | SOURCE | 360.SB113 T
InPort_13082281_1 | SINK | 360.SB113 T
OutPort_7335663_0 | SOURCE | 360.SB113 T
InPort_7335663_1 | SINK | 360.SB113 T
OutPort_13082277_2 | SOURCE | 360.SB113 T
InPort_7568002_1 | SINK | 360.SB113 T
OutPort_13405116_0 | SOURCE | 360.SB113 T
InPort_18047923_1 | SINK | 360.SB113 T
InPort_13327755_0 | SINK | 360.SB113 A
OutPort_8669098_1 | SOURCE | 360.SB113 A
InPort_12339977_2 | SINK | 360.SB114 T
OutPort_12339971_0 | SOURCE | 360.SB114 T
InPort_12339971_1 | SINK | 360.SB114 T
OutPort_12340091_1 | SOURCE | 360.SB114 T
InPort_12340320_0 | SINK | 360.SB114 A
OutPort_12340328_2 | SOURCE | 360.SB114 A
InPort_12340363_1 | SINK | 360.SB114 A
OutPort_12340320_1 | SOURCE | 360.SB114 A
InPort_13082282_1 | SINK | 360.SB113 T
OutPort_13082281_2 | SOURCE | 360.SB113 T
InPort_13082516_1 | SINK | 360.SB111 A
OutPort_14282860_0 | SOURCE | 360.SB111 A
InPort_13082518_1 | SINK | 360.SB112 A
OutPort_14282905_0 | SOURCE | 360.SB112 A
InPort_13271975_1 | SINK | 360.SB113 T
OutPort_13271974_2 | SOURCE | 360.SB113 T
InPort_22036357_1 | SINK | 360.SB113 T
OutPort_13271975_0 | SOURCE | 360.SB113 T
InPort_13327757_3 | SINK | 360.SB113 A
OutPort_13327755_1 | SOURCE | 360.SB113 A
InPort_13327761_0 | SINK | 360.SB113 A
OutPort_13327757_1 | SOURCE | 360.SB113 A
InPort_13327757_2 | SINK | 360.SB113 A
OutPort_13404551_0 | SOURCE | 360.SB113 A
InPort_18021358_1 | SINK | 360.SB113 A
OutPort_13327761_1 | SOURCE | 360.SB113 A
OutPort_18021353_2 | SOURCE | 360.SB113 A
InPort_13879327_1 | SINK | 360.SB113 A
OutPort_13385609_0 | SOURCE | 360.SB113 A
InPort_13385609_1 | SINK | 360.SB113 A
OutPort_22033990_1 | SOURCE | 360.SB113 A
InPort_13386488_1 | SINK | 360.SB113 T
OutPort_13404819_0 | SOURCE | 360.SB113 T
InPort_13399544_1 | SINK | 360.SB113 T
OutPort_13405083_1 | SOURCE | 360.SB113 T
InPort_13404801_0 | SINK | 360.SB113 T
OutPort_13399544_2 | SOURCE | 360.SB113 T
InPort_13404535_1 | SINK | 360.SB113 A
OutPort_13399975_0 | SOURCE | 360.SB113 A
InPort_13399975_1 | SINK | 360.SB113 A
OutPort_13399997_2 | SOURCE | 360.SB113 A
InPort_13399997_1 | SINK | 360.SB113 A
OutPort_16842945_0 | SOURCE | 360.SB113 A
InPort_13404551_1 | SINK | 360.SB113 A
OutPort_13404535_2 | SOURCE | 360.SB113 A
InPort_13404815_2 | SINK | 360.SB113 T
OutPort_13404801_1 | SOURCE | 360.SB113 T
InPort_13404809_0 | SINK | 360.SB113 T
OutPort_13404815_1 | SOURCE | 360.SB113 T
InPort_13404831_1 | SINK | 360.SB113 T
OutPort_13404809_1 | SOURCE | 360.SB113 T
InPort_13404819_1 | SINK | 360.SB113 T
OutPort_13404831_2 | SOURCE | 360.SB113 T
InPort_13404924_0 | SINK | 360.SB113 T
OutPort_18047923_2 | SOURCE | 360.SB113 T
InPort_18047928_2 | SINK | 360.SB113 T
OutPort_13404924_1 | SOURCE | 360.SB113 T
InPort_13405175_2 | SINK | 360.SB113 T
OutPort_13404966_0 | SOURCE | 360.SB113 T
InPort_13404966_1 | SINK | 360.SB113 T
OutPort_18047928_1 | SOURCE | 360.SB113 T
InPort_13405091_1 | SINK | 360.SB113 T
OutPort_13404966_2 | SOURCE | 360.SB113 T
InPort_13405083_0 | SINK | 360.SB113 T
OutPort_13405091_2 | SOURCE | 360.SB113 T
InPort_13405116_1 | SINK | 360.SB113 T
OutPort_13405175_1 | SOURCE | 360.SB113 T
OutPort_13879327_2 | SOURCE | 360.SB113 A
OutPort_14228081_1 | SOURCE | 360.SB110 T
OutPort_14282370_1 | SOURCE | 360.SB112 A
InPort_14282860_1 | SINK | 360.SB111 A
OutPort_14282965_1 | SOURCE | 360.SB111 A
InPort_14282905_1 | SINK | 360.SB112 A
OutPort_14282947_1 | SOURCE | 360.SB112 A
InPort_16842945_1 | SINK | 360.SB113 A
OutPort_16842743_1 | SOURCE | 360.SB113 A
InPort_18021351_0 | SINK | 360.SB113 A
OutPort_18021358_2 | SOURCE | 360.SB113 A
InPort_18021353_1 | SINK | 360.SB113 A
OutPort_18021351_1 | SOURCE | 360.SB113 A
InPort_22033864_0 | SINK | 360.SB113 A
OutPort_22033986_2 | SOURCE | 360.SB113 A
InPort_22033990_2 | SINK | 360.SB113 A
OutPort_22033864_1 | SOURCE | 360.SB113 A
InPort_22033986_1 | SINK | 360.SB113 A
OutPort_22034005_0 | SOURCE | 360.SB113 A
InPort_22034005_1 | SINK | 360.SB113 A
OutPort_22034576_2 | SOURCE | 360.SB113 A
InPort_22064079_0 | SINK | 360.SB113 A
OutPort_22034212_0 | SOURCE | 360.SB113 A
InPort_22034212_1 | SINK | 360.SB113 A
OutPort_22063950_1 | SOURCE | 360.SB113 A
InPort_22034461_2 | SINK | 360.SB113 A
OutPort_22034428_0 | SOURCE | 360.SB113 A
InPort_22034428_1 | SINK | 360.SB113 A
OutPort_22035878_1 | SOURCE | 360.SB113 A
InPort_22034428_2 | SINK | 360.SB113 A
OutPort_22063467_1 | SOURCE | 360.SB113 A
InPort_22034461_1 | SINK | 360.SB113 A
OutPort_22034482_0 | SOURCE | 360.SB113 A
InPort_22034656_1 | SINK | 360.SB113 A
OutPort_22034461_3 | SOURCE | 360.SB113 A
InPort_22034482_1 | SINK | 360.SB113 A
OutPort_22035838_1 | SOURCE | 360.SB113 A
InPort_22034482_2 | SINK | 360.SB113 A
OutPort_22035824_1 | SOURCE | 360.SB113 A
InPort_22034576_1 | SINK | 360.SB113 A
OutPort_22034526_1 | SOURCE | 360.SB113 A
InPort_22034573_1 | SINK | 360.SB113 A
OutPort_22034656_0 | SOURCE | 360.SB113 A
InPort_22057833_0 | SINK | 360.SB113 A
OutPort_22034573_2 | SOURCE | 360.SB113 A
InPort_22034601_2 | SINK | 360.SB113 A
OutPort_22034590_0 | SOURCE | 360.SB113 A
InPort_22034590_1 | SINK | 360.SB113 A
OutPort_22034611_1 | SOURCE | 360.SB113 A
InPort_22057833_2 | SINK | 360.SB113 A
OutPort_22034601_1 | SOURCE | 360.SB113 A
InPort_22034605_0 | SINK | 360.SB113 A
OutPort_22077430_1 | SOURCE | 360.SB113 A
InPort_22058383_1 | SINK | 360.SB113 A
OutPort_22034605_1 | SOURCE | 360.SB113 A
InPort_22034611_2 | SINK | 360.SB113 A
OutPort_22058238_0 | SOURCE | 360.SB113 A
InPort_22077326_0 | SINK | 360.SB113 A
OutPort_22034828_1 | SOURCE | 360.SB113 A
InPort_22077326_3 | SINK | 360.SB113 A
OutPort_22035303_1 | SOURCE | 360.SB113 A
InPort_22035303_2 | SINK | 360.SB113 A
OutPort_22035656_0 | SOURCE | 360.SB113 A
InPort_22077326_2 | SINK | 360.SB113 A
OutPort_22035396_1 | SOURCE | 360.SB113 A
InPort_22035396_2 | SINK | 360.SB113 A
OutPort_22035514_0 | SOURCE | 360.SB113 A
InPort_22035648_1 | SINK | 360.SB113 A
OutPort_22035462_0 | SOURCE | 360.SB113 A
InPort_22035462_1 | SINK | 360.SB113 A
OutPort_22035742_1 | SOURCE | 360.SB113 A
InPort_22035496_1 | SINK | 360.SB113 A
OutPort_22035599_0 | SOURCE | 360.SB113 A
InPort_22035514_1 | SINK | 360.SB113 A
OutPort_22035496_2 | SOURCE | 360.SB113 A
InPort_22035589_1 | SINK | 360.SB113 A
OutPort_22117714_0 | SOURCE | 360.SB113 A
InPort_22035599_1 | SINK | 360.SB113 A
OutPort_22035589_2 | SOURCE | 360.SB113 A
InPort_22035656_1 | SINK | 360.SB113 A
OutPort_22035648_2 | SOURCE | 360.SB113 A
InPort_22035723_0 | SINK | 360.SB113 A
OutPort_22035740_1 | SOURCE | 360.SB113 A
InPort_22035742_2 | SINK | 360.SB113 A
OutPort_22035723_1 | SOURCE | 360.SB113 A
InPort_22035740_0 | SINK | 360.SB113 A
OutPort_22064582_0 | SOURCE | 360.SB113 A
InPort_22035824_2 | SINK | 360.SB113 A
OutPort_22063618_0 | SOURCE | 360.SB113 A
InPort_22063637_1 | SINK | 360.SB113 A
OutPort_22035852_0 | SOURCE | 360.SB113 A
InPort_22035852_1 | SINK | 360.SB113 A
OutPort_22064079_1 | SOURCE | 360.SB113 A
InPort_22036345_0 | SINK | 360.SB113 T
OutPort_22036357_2 | SOURCE | 360.SB113 T
InPort_22036368_1 | SINK | 360.SB113 T
OutPort_22036345_1 | SOURCE | 360.SB113 T
InPort_22036362_0 | SINK | 360.SB113 T
OutPort_22036368_2 | SOURCE | 360.SB113 T
InPort_22036421_1 | SINK | 360.SB113 T
OutPort_22036362_1 | SOURCE | 360.SB113 T
InPort_22057878_0 | SINK | 360.SB113 T
OutPort_22036421_2 | SOURCE | 360.SB113 T
InPort_22036439_0 | SINK | 360.SB113 T
OutPort_22057957_2 | SOURCE | 360.SB113 T
InPort_22058631_1 | SINK | 360.SB113 T
OutPort_22036439_1 | SOURCE | 360.SB113 T
InPort_22059491_1 | SINK | 360.SB113 T
OutPort_22036439_5 | SOURCE | 360.SB113 T
InPort_22060967_1 | SINK | 360.SB113 T
OutPort_22036439_6 | SOURCE | 360.SB113 T
InPort_22091961_1 | SINK | 360.SB113 T
OutPort_22036439_7 | SOURCE | 360.SB113 T
InPort_22059487_1 | SINK | 360.SB113 T
OutPort_22036447_0 | SOURCE | 360.SB113 T
InPort_22036447_1 | SINK | 360.SB113 T
OutPort_22059491_2 | SOURCE | 360.SB113 T
InPort_22059919_1 | SINK | 360.SB113 T
OutPort_22036447_2 | SOURCE | 360.SB113 T
InPort_22057957_1 | SINK | 360.SB113 T
OutPort_22057971_1 | SOURCE | 360.SB113 T
InPort_22058238_1 | SINK | 360.SB113 A
OutPort_22058377_1 | SOURCE | 360.SB113 A
InPort_22058377_2 | SINK | 360.SB113 A
OutPort_22058354_0 | SOURCE | 360.SB113 A
InPort_22058354_1 | SINK | 360.SB113 A
OutPort_22058383_2 | SOURCE | 360.SB113 A
InPort_22059849_1 | SINK | 360.SB113 T
OutPort_22058730_1 | SOURCE | 360.SB113 T
InPort_22058751_1 | SINK | 360.SB113 T
OutPort_22058730_2 | SOURCE | 360.SB113 T
InPort_22058730_3 | SINK | 360.SB113 T
OutPort_22058947_0 | SOURCE | 360.SB113 T
InPort_22059779_1 | SINK | 360.SB113 T
OutPort_22058751_0 | SOURCE | 360.SB113 T
InPort_22058947_1 | SINK | 360.SB113 T
OutPort_22059487_2 | SOURCE | 360.SB113 T
InPort_22059374_0 | SINK | 360.SB113 T
OutPort_22060967_2 | SOURCE | 360.SB113 T
InPort_22059380_1 | SINK | 360.SB113 T
OutPort_22059374_1 | SOURCE | 360.SB113 T
InPort_22061004_0 | SINK | 360.SB113 T
OutPort_22059380_2 | SOURCE | 360.SB113 T
InPort_22059397_0 | SINK | 360.SB113 T
OutPort_22061040_2 | SOURCE | 360.SB113 T
InPort_22059452_3 | SINK | 360.SB113 T
OutPort_22059397_1 | SOURCE | 360.SB113 T
InPort_22060111_0 | SINK | 360.SB113 T
OutPort_22059452_1 | SOURCE | 360.SB113 T
InPort_22060077_0 | SINK | 360.SB113 T
OutPort_22059452_2 | SOURCE | 360.SB113 T
InPort_22059600_1 | SINK | 360.SB113 T
OutPort_22059663_0 | SOURCE | 360.SB113 T
InPort_22059663_1 | SINK | 360.SB113 T
OutPort_22059783_1 | SOURCE | 360.SB113 T
InPort_22059757_0 | SINK | 360.SB113 T
OutPort_22059779_2 | SOURCE | 360.SB113 T
InPort_22059783_2 | SINK | 360.SB113 T
OutPort_22059757_1 | SOURCE | 360.SB113 T
InPort_22059826_1 | SINK | 360.SB113 T
OutPort_22059827_0 | SOURCE | 360.SB113 T
InPort_22059827_1 | SINK | 360.SB113 T
OutPort_22059833_1 | SOURCE | 360.SB113 T
InPort_22059829_0 | SINK | 360.SB113 T
OutPort_22059831_2 | SOURCE | 360.SB113 T
InPort_22059833_2 | SINK | 360.SB113 T
OutPort_22059829_1 | SOURCE | 360.SB113 T
InPort_22059831_1 | SINK | 360.SB113 T
OutPort_22059849_0 | SOURCE | 360.SB113 T
InPort_22059881_1 | SINK | 360.SB113 T
OutPort_22059882_0 | SOURCE | 360.SB113 T
InPort_22059882_1 | SINK | 360.SB113 T
OutPort_22059888_1 | SOURCE | 360.SB113 T
InPort_22059884_0 | SINK | 360.SB113 T
OutPort_22059922_1 | SOURCE | 360.SB113 T
InPort_22059888_2 | SINK | 360.SB113 T
OutPort_22059884_1 | SOURCE | 360.SB113 T
InPort_22059904_0 | SINK | 360.SB113 T
OutPort_22059919_2 | SOURCE | 360.SB113 T
InPort_22059922_2 | SINK | 360.SB113 T
OutPort_22059904_1 | SOURCE | 360.SB113 T
InPort_22059936_1 | SINK | 360.SB113 T
OutPort_22059937_0 | SOURCE | 360.SB113 T
InPort_22059937_1 | SINK | 360.SB113 T
OutPort_22059941_1 | SOURCE | 360.SB113 T
InPort_22059939_0 | SINK | 360.SB113 T
OutPort_22059943_1 | SOURCE | 360.SB113 T
InPort_22059941_2 | SINK | 360.SB113 T
OutPort_22059939_1 | SOURCE | 360.SB113 T
InPort_22059943_2 | SINK | 360.SB113 T
OutPort_22060003_1 | SOURCE | 360.SB113 T
InPort_22059962_1 | SINK | 360.SB113 T
OutPort_22059963_0 | SOURCE | 360.SB113 T
InPort_22059963_1 | SINK | 360.SB113 T
OutPort_22059969_1 | SOURCE | 360.SB113 T
InPort_22059965_0 | SINK | 360.SB113 T
OutPort_22059967_2 | SOURCE | 360.SB113 T
InPort_22059969_2 | SINK | 360.SB113 T
OutPort_22059965_1 | SOURCE | 360.SB113 T
InPort_22059967_1 | SINK | 360.SB113 T
OutPort_22060003_0 | SOURCE | 360.SB113 T
InPort_22060003_2 | SINK | 360.SB113 T
OutPort_22091940_1 | SOURCE | 360.SB113 T
InPort_22060047_1 | SINK | 360.SB113 T
OutPort_22060048_0 | SOURCE | 360.SB113 T
InPort_22060048_1 | SINK | 360.SB113 T
OutPort_22060054_1 | SOURCE | 360.SB113 T
InPort_22060050_0 | SINK | 360.SB113 T
OutPort_22060089_1 | SOURCE | 360.SB113 T
InPort_22060054_2 | SINK | 360.SB113 T
OutPort_22060050_1 | SOURCE | 360.SB113 T
InPort_22060089_2 | SINK | 360.SB113 T
OutPort_22060077_1 | SOURCE | 360.SB113 T
InPort_22060094_1 | SINK | 360.SB113 T
OutPort_22060095_0 | SOURCE | 360.SB113 T
InPort_22060095_1 | SINK | 360.SB113 T
OutPort_22060099_1 | SOURCE | 360.SB113 T
InPort_22060097_0 | SINK | 360.SB113 T
OutPort_22060125_1 | SOURCE | 360.SB113 T
InPort_22060099_2 | SINK | 360.SB113 T
OutPort_22060097_1 | SOURCE | 360.SB113 T
InPort_22060125_2 | SINK | 360.SB113 T
OutPort_22060111_1 | SOURCE | 360.SB113 T
InPort_22061040_1 | SINK | 360.SB113 T
OutPort_22061004_1 | SOURCE | 360.SB113 T
InPort_22061062_1 | SINK | 360.SB113 T
OutPort_22061004_2 | SOURCE | 360.SB113 T
InPort_22061051_0 | SINK | 360.SB113 T
OutPort_22061062_2 | SOURCE | 360.SB113 T
InPort_22061088_1 | SINK | 360.SB113 T
OutPort_22061051_1 | SOURCE | 360.SB113 T
InPort_22061080_0 | SINK | 360.SB113 T
OutPort_22061088_2 | SOURCE | 360.SB113 T
InPort_22061097_1 | SINK | 360.SB113 T
OutPort_22061080_1 | SOURCE | 360.SB113 T
InPort_22063467_2 | SINK | 360.SB113 A
OutPort_22063642_0 | SOURCE | 360.SB113 A
InPort_22063609_1 | SINK | 360.SB113 A
OutPort_22064314_0 | SOURCE | 360.SB113 A
InPort_22063618_1 | SINK | 360.SB113 A
OutPort_22063609_2 | SOURCE | 360.SB113 A
InPort_22063642_1 | SINK | 360.SB113 A
OutPort_22063637_2 | SOURCE | 360.SB113 A
InPort_22064314_1 | SINK | 360.SB113 A
OutPort_22064355_1 | SOURCE | 360.SB113 A
InPort_22064582_1 | SINK | 360.SB113 A
OutPort_22064396_1 | SOURCE | 360.SB113 A
InPort_22077436_1 | SINK | 360.SB113 A
OutPort_22077326_1 | SOURCE | 360.SB113 A
InPort_22077430_2 | SINK | 360.SB113 A
OutPort_22077406_0 | SOURCE | 360.SB113 A
InPort_22077406_1 | SINK | 360.SB113 A
OutPort_22077436_2 | SOURCE | 360.SB113 A
InPort_22090765_1 | SINK | 360.SB113 OVS
OutPort_22090771_1 | SOURCE | 360.SB113 OVS
InPort_22117972_0 | SINK | 360.SB113 OVS
OutPort_22090765_2 | SOURCE | 360.SB113 OVS
InPort_22090771_0 | SINK | 360.SB113 OVS
OutPort_22090841_1 | SOURCE | 360.SB113 OVS
InPort_22091940_2 | SINK | 360.SB113 T
OutPort_22091927_0 | SOURCE | 360.SB113 T
InPort_22091927_1 | SINK | 360.SB113 T
OutPort_22091951_2 | SOURCE | 360.SB113 T
InPort_22091951_1 | SINK | 360.SB113 T
OutPort_22091943_0 | SOURCE | 360.SB113 T
InPort_22091943_1 | SINK | 360.SB113 T
OutPort_22091964_2 | SOURCE | 360.SB113 T
InPort_22091953_0 | SINK | 360.SB113 T
OutPort_22091961_2 | SOURCE | 360.SB113 T
InPort_22091964_1 | SINK | 360.SB113 T
OutPort_22091953_1 | SOURCE | 360.SB113 T
InPort_22117714_1 | SINK | 360.SB113 A
OutPort_22122182_1 | SOURCE | 360.SB113 A
InPort_22118106_1 | SINK | 360.SB113 OVS
OutPort_22117972_1 | SOURCE | 360.SB113 OVS
InPort_22118098_0 | SINK | 360.SB113 OVS
OutPort_22118106_2 | SOURCE | 360.SB113 OVS
InPort_22118100_1 | SINK | 360.SB113 OVS
OutPort_22118098_1 | SOURCE | 360.SB113 OVS
InPort_22118098_1 | SINK | 360.SB113 OVS
OutPort_22118100_1 | SOURCE | 360.SB113 OVS
Port_20453409_1 | SOURCEANDSINK | 370.SB102 T
Port_20453410_1 | SOURCEANDSINK | 370.SB102 T
Port_20453409_2 | SOURCEANDSINK | 370.SB102 T
Port_21083568_0 | SOURCEANDSINK | 370.SB102 T
Port_20453412_1 | SOURCEANDSINK | 370.SB102 R
Port_20453413_1 | SOURCEANDSINK | 370.SB102 R
Port_20453412_2 | SOURCEANDSINK | 370.SB102 R
Port_21083574_0 | SOURCEANDSINK | 370.SB102 R
Port_21083621_0 | SOURCEANDSINK | 370.SB102 T
Port_22136604_1 | SOURCEANDSINK | 370.SB102 T
Port_21083621_1 | SOURCEANDSINK | 370.SB102 T
Port_21083631_0 | SOURCEANDSINK | 370.SB102 R
Port_22136599_1 | SOURCEANDSINK | 370.SB102 R
Port_21083631_1 | SOURCEANDSINK | 370.SB102 R
Port_21083713_1 | SOURCEANDSINK | 370.SB102 T
Port_21083752_1 | SOURCEANDSINK | 370.SB102 T
Port_21394819_0 | SOURCEANDSINK | 370.SB102 R
Port_21396544_1 | SOURCEANDSINK | 370.SB102 R
Port_21394819_1 | SOURCEANDSINK | 370.SB102 R
Port_21394902_0 | SOURCEANDSINK | 370.SB102 T
Port_21396461_1 | SOURCEANDSINK | 370.SB102 T
Port_21394902_1 | SOURCEANDSINK | 370.SB102 T
Port_21396250_0 | SOURCEANDSINK | 370.SB102 T
Port_21396427_1 | SOURCEANDSINK | 370.SB102 T
Port_21396260_1 | SOURCEANDSINK | 370.SB102 T
Port_21396317_0 | SOURCEANDSINK | 370.SB102 R
Port_21396517_1 | SOURCEANDSINK | 370.SB102 R
Port_21396326_1 | SOURCEANDSINK | 370.SB102 R
Port_21396427_2 | SOURCEANDSINK | 370.SB102 T
Port_21396429_1 | SOURCEANDSINK | 370.SB102 T
Port_21396461_2 | SOURCEANDSINK | 370.SB102 T
Port_21396463_1 | SOURCEANDSINK | 370.SB102 T
Port_21396517_2 | SOURCEANDSINK | 370.SB102 R
Port_21396519_1 | SOURCEANDSINK | 370.SB102 R
Port_21396519_0 | SOURCEANDSINK | 370.SB102 R
Port_21396617_1 | SOURCEANDSINK | 370.SB102 R
Port_21396544_2 | SOURCEANDSINK | 370.SB102 R
Port_21396546_1 | SOURCEANDSINK | 370.SB102 R
Port_21396546_0 | SOURCEANDSINK | 370.SB102 R
Port_21396644_1 | SOURCEANDSINK | 370.SB102 R
Port_21396617_2 | SOURCEANDSINK | 370.SB102 R
Port_21396619_1 | SOURCEANDSINK | 370.SB102 R
Port_21396644_2 | SOURCEANDSINK | 370.SB102 R
Port_21396646_1 | SOURCEANDSINK | 370.SB102 R
Port_22136599_2 | SOURCEANDSINK | 370.SB102 R
Port_22136600_1 | SOURCEANDSINK | 370.SB102 R
Port_22136604_2 | SOURCEANDSINK | 370.SB102 T
Port_22136605_1 | SOURCEANDSINK | 370.SB102 T
Port_22136609_0 | SOURCEANDSINK | 370.SB102 R
Port_22136625_1 | SOURCEANDSINK | 370.SB102 R
Port_22136609_1 | SOURCEANDSINK | 370.SB102 R
Port_22136617_0 | SOURCEANDSINK | 370.SB102 T
Port_22136675_2 | SOURCEANDSINK | 370.SB102 T
Port_22136617_1 | SOURCEANDSINK | 370.SB102 T
Port_22136625_2 | SOURCEANDSINK | 370.SB102 R
Port_22136626_1 | SOURCEANDSINK | 370.SB102 R
Port_22136675_1 | SOURCEANDSINK | 370.SB102 T
Port_22136683_1 | SOURCEANDSINK | 370.SB102 T
Port_22171686_1 | SOURCEANDSINK
Port_22171787_1 | SOURCEANDSINK
Port_23480837_1 | SOURCEANDSINK | K 347
Port_23480838_0 | SOURCEANDSINK | K 347
Port_23480838_1 | SOURCEANDSINK | K 347
Port_23480840_1 | SOURCEANDSINK | K 349
Port_23480841_0 | SOURCEANDSINK | K 349
Port_23480841_1 | SOURCEANDSINK | K 349
Port_6031075_0 | SOURCEANDSINK | 310.TO500 22
Port_7600315_0 | SOURCEANDSINK | 310.TO100 78
Port_9049062_1 | SOURCEANDSINK | 310.TO500 22
OutPort_10884926_1 | SOURCE | 310.TO500 1 (47)
Port_10884926_2 | SOURCEANDSINK
OutPort_10888927_1 | SOURCE
Port_10888927_2 | SOURCEANDSINK
Port_10911357_1 | SOURCEANDSINK
OutPort_10914619_1 | SOURCE
Port_15946447_0 | SOURCEANDSINK | 310.TO500 22
OutPort_19152087_1 | SOURCE
Port_19152381_1 | SOURCEANDSINK | 310.TO500 22
Port_19154484_1 | SOURCEANDSINK | 310.TO200 1
Port_19165741_0 | SOURCEANDSINK | 310.TO500 22
Port_19165991_1 | SOURCEANDSINK | 310.TO601
Port_19166408_1 | SOURCEANDSINK | 310.TO100 78
Port_19173949_0 | SOURCEANDSINK | 310.TO500 22
Port_19174209_0 | SOURCEANDSINK | 310.TO500 22
Port_19174457_0 | SOURCEANDSINK | 310.TO500 22
Port_19174910_0 | SOURCEANDSINK | 310.TO500 22
Port_19185895_0 | SOURCEANDSINK | 310.TO500 22
InPort_19191870_1 | SINK
Port_19192476_0 | SOURCEANDSINK | 310.TO200 1
Port_19192476_1 | SOURCEANDSINK | 310.TO200 1
Port_19192774_0 | SOURCEANDSINK | 310.TO200 1
Port_19192774_1 | SOURCEANDSINK | 310.TO200 1
Port_19192795_1 | SOURCEANDSINK | 310.TO100 78
InPort_10365456_0 | SINK | 332.SB001 (1) (2)
OutPort_9498206_1 | SOURCE | 332.SB001 (1) (2)
InPort_9498208_1 | SINK | 332.SB001 (1) (2)
OutPort_9498207_1 | SOURCE | 332.SB001 (1) (2)
InPort_10365519_0 | SINK | 332.SB001 (1) (2)
OutPort_9498219_1 | SOURCE | 332.SB001 (1) (2)
InPort_9498221_1 | SINK | 332.SB001 (1) (2)
OutPort_9498220_1 | SOURCE | 332.SB001 (1) (2)
InPort_11007168_1 | SINK | 332.SB001 (1) (2)
OutPort_11007167_1 | SOURCE | 332.SB001 (1) (2)
InPort_19828718_1 | SINK | 332.SB001 (1) (2)
OutPort_19828717_1 | SOURCE | 332.SB001 (1) (2)
InPort_19828761_1 | SINK | 332.SB001 (1) (2)
OutPort_19828760_1 | SOURCE | 332.SB001 (1) (2)
InPort_19828783_1 | SINK | 332.SB001 (1) (2)
OutPort_19828782_1 | SOURCE | 332.SB001 (1) (2)
InPort_19829300_1 | SINK | 332.SB001 (1) (2)
OutPort_19829299_1 | SOURCE | 332.SB001 (1) (2)
InPort_19829324_1 | SINK | 332.SB001 (1) (2)
OutPort_19829323_1 | SOURCE | 332.SB001 (1) (2)
InPort_19829336_1 | SINK | 332.SB001 (1) (2)
OutPort_19829335_1 | SOURCE | 332.SB001 (1) (2)
InPort_19829619_1 | SINK | 332.SB001 (1) (2)
OutPort_19829618_1 | SOURCE | 332.SB001 (1) (2)
InPort_19830441_1 | SINK | 332.SB001 (1) (2)
OutPort_19830440_1 | SOURCE | 332.SB001 (1) (2)
InPort_19830494_1 | SINK | 332.SB001 (1) (2)
OutPort_19830493_1 | SOURCE | 332.SB001 (1) (2)
InPort_19830604_1 | SINK | 332.SB001 (1) (2)
OutPort_19830603_1 | SOURCE | 332.SB001 (1) (2)
InPort_19830614_1 | SINK | 332.SB001 (1) (2)
OutPort_19830613_1 | SOURCE | 332.SB001 (1) (2)
InPort_19830969_1 | SINK | 332.SB001 (1) (2)
OutPort_19830968_1 | SOURCE | 332.SB001 (1) (2)
InPort_19830972_1 | SINK | 332.SB001 (1) (2)
OutPort_19830971_1 | SOURCE | 332.SB001 (1) (2)
InPort_19831094_1 | SINK | 332.SB001 (1) (2)
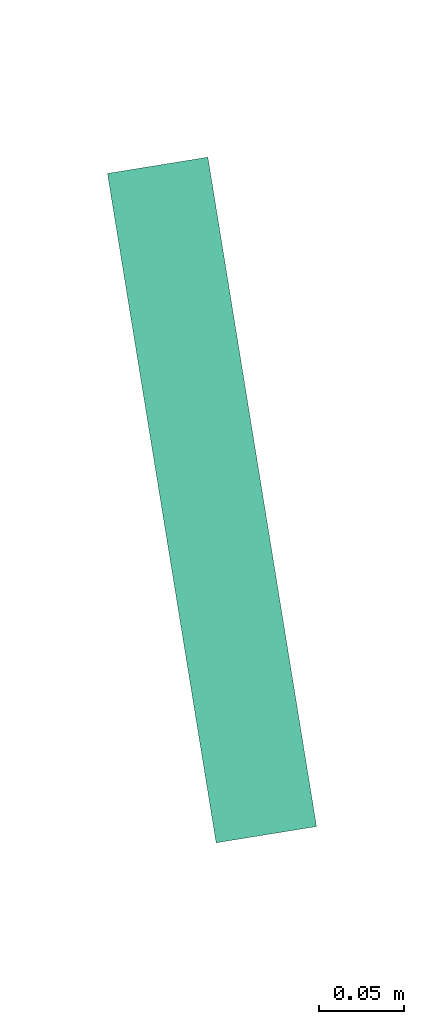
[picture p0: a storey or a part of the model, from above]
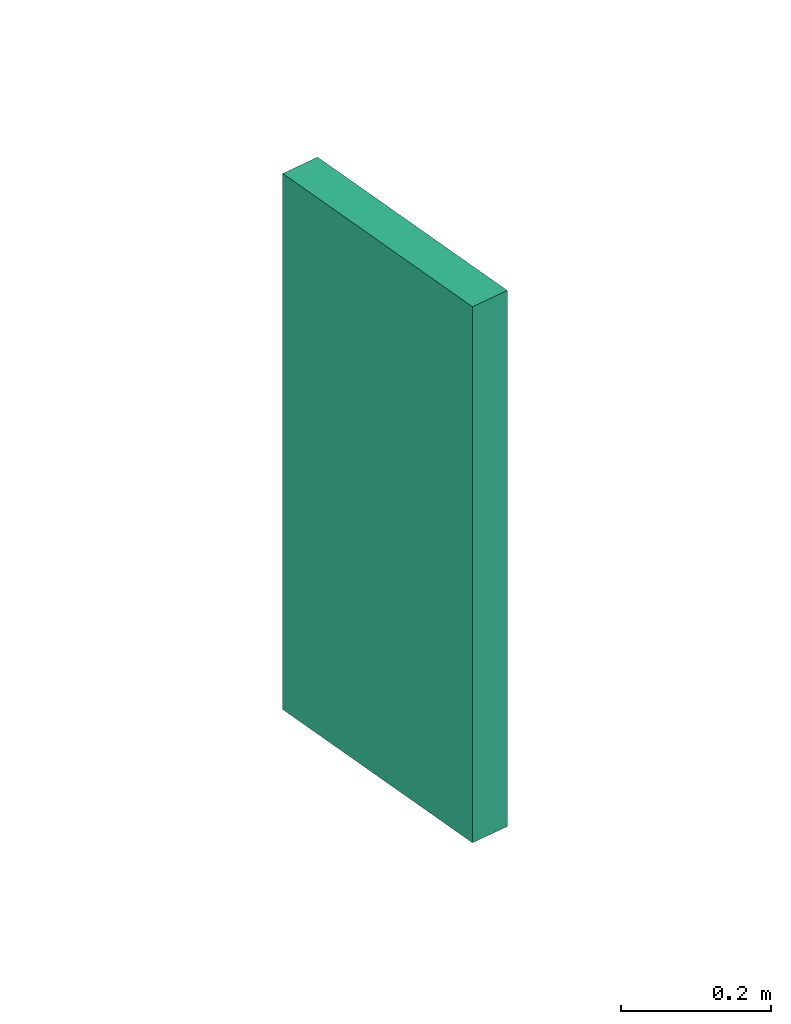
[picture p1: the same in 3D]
Properties of the parts of a building model (IFC2X3), part 2 of 3

# IfcDistributionPort (673)
Name | FlowDirection | Group
OutPort_19831093_1 | SOURCE | 332.SB001 (1) (2)
InPort_19831097_1 | SINK | 332.SB001 (1) (2)
OutPort_19831096_1 | SOURCE | 332.SB001 (1) (2)
InPort_19831177_1 | SINK | 332.SB001 (1) (2)
OutPort_19831176_1 | SOURCE | 332.SB001 (1) (2)
InPort_19831234_1 | SINK | 332.SB001 (1) (2)
OutPort_19831233_1 | SOURCE | 332.SB001 (1) (2)
InPort_19831237_1 | SINK | 332.SB001 (1) (2)
OutPort_19831236_1 | SOURCE | 332.SB001 (1) (2)
InPort_19831297_1 | SINK | 332.SB001 (1) (2)
OutPort_19831296_1 | SOURCE | 332.SB001 (1) (2)
InPort_19831381_1 | SINK | 332.SB001 (1) (2)
OutPort_19831380_1 | SOURCE | 332.SB001 (1) (2)
InPort_19831487_1 | SINK | 332.SB001 (1) (2)
OutPort_20623527_0 | SOURCE | 332.SB001 (1) (2)
InPort_19831566_1 | SINK | 332.SB001 (1) (2)
OutPort_19831567_0 | SOURCE | 332.SB001 (1) (2)
InPort_19831603_1 | SINK | 332.SB001 (1) (2)
OutPort_19831602_1 | SOURCE | 332.SB001 (1) (2)
InPort_19831615_1 | SINK | 332.SB001 (1) (2)
OutPort_19831614_1 | SOURCE | 332.SB001 (1) (2)
Port_7046618_1 | SOURCEANDSINK
Port_7046619_1 | SOURCEANDSINK
Port_7046620_1 | SOURCEANDSINK
Port_7046621_1 | SOURCEANDSINK
Port_7046635_1 | SOURCEANDSINK
Port_7046636_1 | SOURCEANDSINK
Port_7046638_1 | SOURCEANDSINK
Port_7046639_1 | SOURCEANDSINK
Port_7046640_1 | SOURCEANDSINK
Port_7046641_1 | SOURCEANDSINK
Port_7268528_1 | SOURCEANDSINK
Port_7268529_1 | SOURCEANDSINK
Port_7394731_1 | SOURCEANDSINK
Port_7394831_1 | SOURCEANDSINK
Port_8253846_1 | SOURCEANDSINK
Port_8255363_1 | SOURCEANDSINK
Port_9744690_1 | SOURCEANDSINK
Port_9745026_1 | SOURCEANDSINK
Port_9752896_1 | SOURCEANDSINK
Port_9752900_1 | SOURCEANDSINK
Port_9752904_1 | SOURCEANDSINK
Port_9752908_1 | SOURCEANDSINK
Port_9752912_1 | SOURCEANDSINK
Port_9822640_1 | SOURCEANDSINK
Port_9822760_1 | SOURCEANDSINK
Port_9822846_1 | SOURCEANDSINK
Port_10112814_1 | SOURCEANDSINK
Port_10392649_1 | SOURCEANDSINK
Port_10954286_1 | SOURCEANDSINK
Port_10954413_1 | SOURCEANDSINK

# IfcDoor: A200 - Slagdør - Enfløyet:A244 - DI_LSO - 0890 x 2190 mm, A200 - Slagdør - Enfløyet:A244 - DI_LSO - 0890 x 2190 mm:40483843
In: Nivå D-H01
Type - OperationType: SINGLE_SWING_RIGHT; ParameterTakesPrecedence: no; Sizeable: no; Material: _NSW Stål - rustfritt, _NSW Stål, N_Door - Threshold, N_Door - Panel
Type - IfcDoorPanelProperties - PanelOperation: SWINGING
OverallHeight: 2210 mm; OverallWidth: 910 mm
ePset_Simplebim - Assembly Level: Leaf
Pset_DoorCommon - Reference: A200 - Slagdør - Enfløyet:A244 - DI_LSO - 0890 x 2190 mm
ePset_SimplebimBasicQuantities - Height, opening (Simplebim): 2210 mm; Area, opening (Simplebim): 2.0111 m2; Width (Simplebim): 890 mm; Width, opening (Simplebim): 910 mm; Height (Simplebim): 2190 mm; Length, frame (Simplebim): 5270 mm; Area (Simplebim): 1.9491 m2
ePset_LocationTool - Splitting: ORIGINAL

# IfcDoor: A200 - Slagdør - Enfløyet:A244 - DI_LSO - 0990 x 2190 mm (4)
In: Nivå D-H01
Type - OperationType: SINGLE_SWING_RIGHT; ParameterTakesPrecedence: no; Sizeable: no; Material: _NSW Stål - rustfritt, _NSW Stål, N_Door - Threshold, N_Door - Panel
Type - IfcDoorPanelProperties - PanelOperation: SWINGING
OverallWidth: 1010 mm
ePset_Simplebim - Assembly Level: Leaf
Pset_DoorCommon - Reference: A200 - Slagdør - Enfløyet:A244 - DI_LSO - 0990 x 2190 mm
ePset_SimplebimBasicQuantities - Area (Simplebim): 2.1681 m2; Width (Simplebim): 990 mm; Width, opening (Simplebim): 1010 mm; Height (Simplebim): 2190 mm; Length, frame (Simplebim): 5370 mm
ePset_LocationTool - Splitting: ORIGINAL
Name (A200 - Slagdør - Enfløyet:A244 - DI_LSO - 0990 x 2190 mm:...) | OverallHeight (mm) = Height, opening (Simplebim) (mm) | 05_ID-nummer | Area, opening (Simplebim) (m2)
8702926 | 2200 | +BR003=244.04148 | 2.222
10713092 | 2200 | +BR003=244.04036 | 2.222
22473332 | 2210 | +BR003=244.04071 | 2.2321
35827357 | 2200 | +BR003=244.04029 | 2.222

# IfcDoor: A200 - Slagdør - Tofløyet:A244 - DI_LSO - 1990 x 2190 mm, A200 - Slagdør - Tofløyet:A244 - DI_LSO - 1990 x 2190 mm:45087363
In: Nivå D-H01
Type - OperationType: DOUBLE_DOOR_SINGLE_SWING; ParameterTakesPrecedence: no; Sizeable: no; Material: _NSW Stål
Type - IfcDoorPanelProperties - PanelOperation: SWINGING
OverallHeight: 2210 mm; OverallWidth: 2010 mm
AVINOR - 05_ID-nummer: +BR003=244.04000-DI0004; 08_Status: S4; 03_Ansvar: 188110; 07_Fase: F50; 02_Prosjekt: 10003898; 01_Lufthavnkode: ENBR
ePset_Simplebim - Assembly Level: Leaf
Pset_DoorCommon - Reference: A200 - Slagdør - Tofløyet:A244 - DI_LSO - 1990 x 2190 mm
ePset_SimplebimBasicQuantities - Area (Simplebim): 4.3581 m2; Area, opening (Simplebim): 4.4421 m2; Length, frame (Simplebim): 6370 mm; Height (Simplebim): 2190 mm; Height, opening (Simplebim): 2210 mm; Width, opening (Simplebim): 2010 mm; Width (Simplebim): 1990 mm
ePset_LocationTool - Splitting: ORIGINAL

# IfcFlowController: LUFTEPOTTE--:LUFTEPOTTE (2)
In: Nivå D
Type - Material: 2d_hide, Metal - Caleffi - Brass
Classification: D2020300 Domestic Water Supply Equipment (Uniformat)
ePset_LocationTool - Splitting: ORIGINAL
ePset_Simplebim - Assembly Level: Leaf
AVINOR - 08_Status: S4; 07_Fase: F90
Name (LUFTEPOTTE--:LUFTEPOTTE:...) | 05_ID-nummer | Group
23480837 | +BR003=370.SB102-ML003 | K 347
23480840 | +BR003=370.SB102-ML004 | K 349

# IfcFlowController: REGULERINGSVENTIL - MANUELL--SV001T:REGULERINGSVENTIL - MANUELL-20-SV001T (2)
In: Nivå D
Type - Material: 2d_hide
ePset_Simplebim - Assembly Level: Leaf
AVINOR - 08_Status: S4; 07_Fase: F90
ePset_LocationTool - Splitting: ORIGINAL
Group: 370.SB102 R
Name (REGULERINGSVENTIL - MANUELL--SV001T:REGULERINGSVENTIL - MANUELL-20-SV001T:...) | 05_ID-nummer
21396617 | +BR003=370.SB102-SV002
21396644 | +BR003=370.SB102-SV003

# IfcFlowController: REGULERINGSVENTIL - MANUELL--SV01T:REGULERINGSVENTIL - MANUELL-25-SV001T (2)
In: Nivå D
Type - Material: 2d_hide
ePset_Simplebim - Assembly Level: Leaf
ePset_LocationTool - Splitting: ORIGINAL
AVINOR - 08_Status: S4; 07_Fase: F90
Group: 370.SB102 R
Name (REGULERINGSVENTIL - MANUELL--SV01T:REGULERINGSVENTIL - MANUELL-25-SV001T:...) | 05_ID-nummer
22136599 | +BR003=370.SB102-SV005
22136625 | +BR003=370.SB102-SV004

# IfcFlowController: REGULERINGSVENTIL - MOTORSTYRT- 1-SB001T:REGULERINGSVENTIL - MOTORSTYRT-SB001T (2)
In: Nivå D
Type - Material: 2d_hide
ePset_LocationTool - Splitting: ORIGINAL
ePset_Simplebim - Assembly Level: Leaf
AVINOR - 08_Status: S4; 07_Fase: F90
Group: 370.SB102 R
Name (REGULERINGSVENTIL - MOTORSTYRT- 1-SB001T:REGULERINGSVENTIL - MOTORSTYRT-SB001T:...) | 05_ID-nummer
21396517 | +BR003=370.SB102-SB001
21396544 | +BR003=370.SB102-SB002

# IfcFlowController: STENGEVENTIL - MANUELL - 4 - SM:STENGEVENTIL - MANUELL - 20 - SM01T (2)
In: Nivå D
Type - Material: <Unnamed>
ePset_LocationTool - Splitting: ORIGINAL
ePset_Simplebim - Assembly Level: Leaf
AVINOR - 08_Status: S4; 07_Fase: F90
Name (STENGEVENTIL - MANUELL - 4 - SM:STENGEVENTIL - MANUELL - 20 - SM01T:...) | 05_ID-nummer
19169148 | +BR003=310.TO200-SM264
19169200 | +BR003=310.TO200-SM265

# IfcFlowController: STENGEVENTIL - MANUELL - 4 - SM:STENGEVENTIL - MANUELL - 25 - SM01T (2)
In: Nivå D
Type - Material: <Unnamed>
ePset_Simplebim - Assembly Level: Leaf
AVINOR - 08_Status: S4; 07_Fase: F90
ePset_LocationTool - Splitting: ORIGINAL
Name (STENGEVENTIL - MANUELL - 4 - SM:STENGEVENTIL - MANUELL - 25 - SM01T:...) | 05_ID-nummer
19169247 | +BR003=310.TO100-SM230
19169295 | +BR003=310.TO100-SM231

# IfcFlowController: STENGEVENTIL - MANUELL- 1-SM01T:STENGEVENTIL - MANUELL-20-SM001T (2)
In: Nivå D
Type - Material: <Unnamed>
ePset_Simplebim - Assembly Level: Leaf
ePset_LocationTool - Splitting: ORIGINAL
AVINOR - 08_Status: S4; 07_Fase: F90
Group: 370.SB102 T
Name (STENGEVENTIL - MANUELL- 1-SM01T:STENGEVENTIL - MANUELL-20-SM001T:...) | 05_ID-nummer
21396427 | +BR003=370.SB102-SM009
21396461 | +BR003=370.SB102-SM010

# IfcFlowController: STENGEVENTIL - MANUELL--SM06T:STENGEVENTIL - MANUELL-25-SM006T (2)
In: Nivå D
Type - Material: 2d_hide
ePset_Simplebim - Assembly Level: Leaf
AVINOR - 08_Status: S4; 07_Fase: F90
ePset_LocationTool - Splitting: ORIGINAL
Group: 370.SB102 T
Name (STENGEVENTIL - MANUELL--SM06T:STENGEVENTIL - MANUELL-25-SM006T:...) | 05_ID-nummer
22136604 | +BR003=370.SB102-SM011
22136675 | +BR003=370.SB102-SM012

# IfcFlowController: STENGEVENTIL - MANUELL--SM06T:STENGEVENTIL - MANUELL-40-SM006T (2)
In: Nivå D
Type - Material: 2d_hide
ePset_Simplebim - Assembly Level: Leaf
AVINOR - 08_Status: S4; 07_Fase: F90
ePset_LocationTool - Splitting: ORIGINAL
Name (STENGEVENTIL - MANUELL--SM06T:STENGEVENTIL - MANUELL-40-SM006T:...) | 05_ID-nummer | Group
20453409 | +BR003=370.SB102-SM005 | 370.SB102 T
20453412 | +BR003=370.SB102-SM007 | 370.SB102 R

# IfcFlowController: STENGEVENTIL - MOTORSTYRT - -:STENGEVENTIL - MOTORSTYRT - -, STENGEVENTIL - MOTORSTYRT - -:STENGEVENTIL - MOTORSTYRT - -:19658977
In: Nivå D
Type - Material: 2d_hide
ePset_LocationTool - Splitting: ORIGINAL
ePset_Simplebim - Assembly Level: Leaf
AVINOR - 08_Status: S4; 07_Fase: F90; 05_ID-nummer: +BR003=310.TO100-SC005

# IfcFlowController: TRYKKREDUKSJONSVENTIL - - SJ:TRYKKREDUKSJONSVENTIL - 25 - SJ01T, TRYKKREDUKSJONSVENTIL - - SJ:TRYKKREDUKSJONSVENTIL - 25 - SJ01T:19200028
In: Nivå D
Type - Material: 2d_hide
ePset_Simplebim - Assembly Level: Leaf
AVINOR - 08_Status: S4; 07_Fase: F90; 05_ID-nummer: +BR003=310.TO100-SJ011
ePset_LocationTool - Splitting: ORIGINAL

# IfcFlowFitting: Endcap 5521:Lindab EPF (5)
In: Nivå D
Type - Material: DF_Material1
ePset_Simplebim - Assembly Level: Leaf
AVINOR - 08_Status: S4; 07_Fase: F90; 05_ID-nummer: +BR003=360.SB113-KK001T
ePset_LocationTool - Splitting: ORIGINAL
Name (Endcap 5521:Lindab EPF:...) | Group
22034828 | 360.SB113 A
22035838 | 360.SB113 A
22035878 | 360.SB113 A
22058631 | 360.SB113 T
22064355 | 360.SB113 A

# IfcFlowFitting: MC_Ladder Vertical Inside Bend_Short:Standard 10mm, MC_Ladder Vertical Inside Bend_Short:Standard 10mm:14233287
In: Nivå D
Type - Material: <Unnamed>
ePset_Simplebim - Assembly Level: Leaf
ePset_LocationTool - Splitting: ORIGINAL
AVINOR - 08_Status: S4; 07_Fase: F90; 05_ID-nummer: +BR003=411.OO001-CR001T

# IfcFlowFitting: MC_Ladder Vertical Outside Bend:Standard 10mm (2)
In: Nivå D
Type - Material: <Unnamed>
ePset_Simplebim - Assembly Level: Leaf
ePset_LocationTool - Splitting: ORIGINAL
AVINOR - 08_Status: S4; 07_Fase: F90; 05_ID-nummer: +BR003=411.OO001-CR001T
Name (MC_Ladder Vertical Outside Bend:Standard 10mm:...)
14162498
14233284

# IfcFlowFitting: M_Ladder Horizontal Bend:Standard (9)
In: Nivå D
Type - Material: <Unnamed>
ePset_LocationTool - Splitting: ORIGINAL
ePset_Simplebim - Assembly Level: Leaf
AVINOR - 08_Status: S4; 07_Fase: F90; 05_ID-nummer: +BR003=411.OO001-CR001T
Name (M_Ladder Horizontal Bend:Standard:...)
14233376
14233537
14244947
14244948
14245987
14245988
14246024
14246025
14246518

# IfcFlowFitting: magicirc_elbow_full_radius_1:magicirc_elbow_full_radius_001 (43)
Type - Material: <Unnamed>
ePset_Simplebim - Assembly Level: Leaf
AVINOR - 08_Status: S4; 07_Fase: F90
ePset_LocationTool - Splitting: ORIGINAL
Name (magicirc_elbow_full_radius_1:magicirc_elbow_full_radius_001:...) | In | 05_ID-nummer | Group
7335647 | Nivå D | +BR003=360.SB113-KK001T | 360.SB113 T
12339977 | Nivå C | +BR003=360.SB114-KK001T | 360.SB114 T
12340091 | Nivå C | +BR003=360.SB114-KK001T | 360.SB114 T
12340328 | Nivå C | +BR003=360.SB114-KK001T | 360.SB114 A
12340363 | Nivå C | +BR003=360.SB114-KK001T | 360.SB114 A
13082277 | Nivå D | +BR003=360.SB113-KK001T | 360.SB113 T
13404815 | Nivå D | +BR003=360.SB113-KK001T | 360.SB113 T
13404831 | Nivå D | +BR003=360.SB113-KK001T | 360.SB113 T
18021353 | Nivå D | +BR003=360.SB113-KK001T | 360.SB113 A
18021358 | Nivå D | +BR003=360.SB113-KK001T | 360.SB113 A
18047923 | Nivå D | +BR003=360.SB113-KK001T | 360.SB113 T
18047928 | Nivå D | +BR003=360.SB113-KK001T | 360.SB113 T
22033986 | Nivå D | +BR003=360.SB113-KK001T | 360.SB113 A
22033990 | Nivå D | +BR003=360.SB113-KK001T | 360.SB113 A
22034576 | Nivå D | +BR003=360.SB113-KK001T | 360.SB113 A
22034611 | Nivå D | +BR003=360.SB113-KK001T | 360.SB113 A
22035742 | Nivå D | +BR003=360.SB113-KK001T | 360.SB113 A
22036357 | Nivå D | +BR003=360.SB113-KK001T | 360.SB113 T
22036368 | Nivå D | +BR003=360.SB113-KK001T | 360.SB113 T
22036421 | Nivå D | +BR003=360.SB113-KK001T | 360.SB113 T
22058377 | Nivå D | +BR003=360.SB113-KK001T | 360.SB113 A
22058383 | Nivå D | +BR003=360.SB113-KK001T | 360.SB113 A
22059380 | Nivå D | +BR003=360.SB113-KK001T | 360.SB113 T
22059779 | Nivå D | +BR003=360.SB113-KK001T | 360.SB113 T
22059783 | Nivå D | +BR003=360.SB113-KK001T | 360.SB113 T
22059831 | Nivå D | +BR003=360.SB113-KK001T | 360.SB113 T
22059833 | Nivå D | +BR003=360.SB113-KK001T | 360.SB113 T
22059888 | Nivå D | +BR003=360.SB113-KK001T | 360.SB113 T
22059922 | Nivå D | +BR003=360.SB113-KK001T | 360.SB113 T
22059941 | Nivå D | +BR003=360.SB113-KK001T | 360.SB113 T
22059943 | Nivå D | +BR003=360.SB113-KK001T | 360.SB113 T
22059967 | Nivå D | +BR003=360.SB113-KK001T | 360.SB113 T
22059969 | Nivå D | +BR003=360.SB113-KK001T | 360.SB113 T
22060054 | Nivå D | +BR003=360.SB113-KK001T | 360.SB113 T
22060089 | Nivå D | +BR003=360.SB113-KK001T | 360.SB113 T
22060099 | Nivå D | +BR003=360.SB113-KK001T | 360.SB113 T
22060125 | Nivå D | +BR003=360.SB113-KK001T | 360.SB113 T
22061088 | Nivå D | +BR003=360.SB113-KK001T | 360.SB113 T
22077430 | Nivå D | +BR003=360.SB113-KK001T | 360.SB113 A
22077436 | Nivå D | +BR003=360.SB113-KK001T | 360.SB113 A
22091951 | Nivå D | +BR003=360.SB113-KK001T | 360.SB113 T
22091964 | Nivå D | +BR003=360.SB113-KK001T | 360.SB113 T
22118106 | Nivå D | +BR003=360.SB113-KK001T | 360.SB113 OVS

# IfcFlowFitting: magicirc_multi_shape_trans_001:magicirc_multi_shape_trans_001 (7)
Type - Material: Material_Duct
ePset_Simplebim - Assembly Level: Leaf
ePset_LocationTool - Splitting: ORIGINAL
AVINOR - 08_Status: S4; 07_Fase: F90
Name (magicirc_multi_shape_trans_001:magicirc_multi_shape_trans_001:...) | In | 05_ID-nummer | Group
13082516 | Nivå C | +BR003=360.SB111-KK001T | 360.SB111 A
13082517 | Nivå C | +BR003=360.SB111-KK001T | 360.SB111 A
13082518 | Nivå C | +BR003=360.SB112-KK001T | 360.SB112 A
13082520 | Nivå C | +BR003=360.SB112-KK001T | 360.SB112 A
14228081 | Nivå E | +BR003=360.SB110-KK001T | 360.SB110 T
22035740 | Nivå D | +BR003=360.SB113-KK001T | 360.SB113 A
22064079 | Nivå D | +BR003=360.SB113-KK001T | 360.SB113 A

# IfcFlowFitting: magicirc_reduction_001:magicirc_reduction_001 (5)
In: Nivå D
Type - Material: Material_Duct
ePset_Simplebim - Assembly Level: Leaf
AVINOR - 08_Status: S4; 07_Fase: F90; 05_ID-nummer: +BR003=360.SB113-KK001T
ePset_LocationTool - Splitting: ORIGINAL
Name (magicirc_reduction_001:magicirc_reduction_001:...) | Group
13399997 | 360.SB113 A
13405175 | 360.SB113 T
22034573 | 360.SB113 A
22059487 | 360.SB113 T
22061040 | 360.SB113 T

# IfcFlowFitting: magicirc_tapoutlet_1:magicirc_tapoutlet_001 (12)
In: Nivå D
Type - Material: <Unnamed>
ePset_Simplebim - Assembly Level: Leaf
ePset_LocationTool - Splitting: ORIGINAL
AVINOR - 08_Status: S4; 07_Fase: F90; 05_ID-nummer: +BR003=360.SB113-KK001T
Name (magicirc_tapoutlet_1:magicirc_tapoutlet_001:...) | Group
13405091 | 360.SB113 T
22034601 | 360.SB113 A
22035303 | 360.SB113 A
22035396 | 360.SB113 A
22035824 | 360.SB113 A
22059491 | 360.SB113 T
22059919 | 360.SB113 T
22060967 | 360.SB113 T
22061062 | 360.SB113 T
22063467 | 360.SB113 A
22091940 | 360.SB113 T
22091961 | 360.SB113 T

# IfcFlowFitting: magicirc_tee_centric_90_1:magicirc_tee_centric_90_001 (4)
In: Nivå D
Type - Material: <Unnamed>
ePset_Simplebim - Assembly Level: Leaf
AVINOR - 08_Status: S4; 07_Fase: F90; 05_ID-nummer: +BR003=360.SB113-KK001T
ePset_LocationTool - Splitting: ORIGINAL
Name (magicirc_tee_centric_90_1:magicirc_tee_centric_90_001:...) | Group
13327757 | 360.SB113 A
22034461 | 360.SB113 A
22058730 | 360.SB113 T
22059452 | 360.SB113 T

# IfcFlowSegment: Cable Tray with Fittings:Armaturskinne, Cable Tray with Fittings:Armaturskinne:14244920
In: Nivå D
Type - PredefinedType: CABLETRAYSEGMENT
ePset_Simplebim - Assembly Level: Leaf
AVINOR - 08_Status: S4; 07_Fase: F90; 05_ID-nummer: +BR003=411.OO001-CR012T
ePset_SimplebimBasicQuantities - Length (Simplebim): 7130 mm; Width (Simplebim): 50 mm; Height (Simplebim): 50 mm
ePset_LocationTool - Splitting: ORIGINAL

# IfcFlowSegment: Cable Tray with Fittings:Kabelbro (15)
Type - PredefinedType: CABLETRAYSEGMENT
ePset_Simplebim - Assembly Level: Leaf
ePset_LocationTool - Splitting: ORIGINAL
AVINOR - 08_Status: S4; 07_Fase: F90; 05_ID-nummer: +BR003=411.OO001-CR001T
Name (Cable Tray with Fittings:Kabelbro:...) | In | Width (Simplebim) (mm) | Height (Simplebim) (mm) | Length (Simplebim) (mm)
8559565 | Nivå D | 400 | 60 | 2029
8597597 | Nivå D | 400 | 60 | 4936.24
14162308 | Nivå B | 60 | 400 | 872.48
14208431 | Nivå D | 400 | 60 | 4366.31
14232792 | Nivå D | 297.572 | 60 | 400
14233037 | Nivå D | 400 | 60 | 614.572
14233246 | Nivå D | 373.563 | 282.983 | 400
14233326 | Nivå D | 400 | 60 | 2989.4
14233464 | Nivå D | 400 | 60 | 2779.69
14233636 | Nivå D | 400 | 60 | 1440
14245065 | Nivå D | 352.776 | 60 | 400
14245132 | Nivå D | 400 | 60 | 938.285
14245162 | Nivå D | 409.042 | 60 | 444.973
14245866 | Nivå D | 412.642 | 60 | 448.391
14246517 | Nivå D | 400 | 60 | 579

# IfcFlowSegment: Cable Tray with Fittings:Spotskinne (9)
In: Nivå D
Type - PredefinedType: CABLETRAYSEGMENT
ePset_SimplebimBasicQuantities - Width (Simplebim): 50 mm; Height (Simplebim): 50 mm
ePset_LocationTool - Splitting: ORIGINAL
ePset_Simplebim - Assembly Level: Leaf
AVINOR - 08_Status: S4; 07_Fase: F90
Name (Cable Tray with Fittings:Spotskinne:...) | Length (Simplebim) (mm)
14244919 | 11130
14244921 | 1800
14244922 | 1800
14244923 | 3500
14244924 | 3500
14244926 | 1800
14244927 | 1800
14244928 | 10110
14244929 | 10110

# IfcFlowSegment: Pipe Types:Kobberrør (25)
ePset_Simplebim - Assembly Level: Leaf
AVINOR - 08_Status: S4; 07_Fase: F90
Name (Pipe Types:Kobberrør:...) | In | Splitting | Length (Simplebim) (mm) | Width (Simplebim) (mm) = Height (Simplebim) (mm) | 05_ID-nummer
7600312 | Nivå C | ORIGINAL | 732 | 28 | +BR003=310.TO100-KR001T | AVINOR - 01_Lufthavnkode: ENBR
7600315 | Nivå D | ORIGINAL | 1360 | 28 | +BR003=310.TO100-KR001T | Group: 310.TO100 78
19154484 | Nivå D | ORIGINAL | 458 | 28 | +BR003=310.TO200-KR003T | Group: 310.TO200 1
19166408 | Nivå D | ORIGINAL | 452 | 35 | +BR003=310.TO100-KR001T | Group: 310.TO100 78
19166672 | Nivå D | ORIGINAL | 113.413 | 22 | +BR003=310.TO200-KR003T
19166740 | Nivå D | ORIGINAL | 231.913 | 28 | +BR003=310.TO100-KR001T
19166780 | Nivå D | ORIGINAL | 6693 | 22 | +BR003=310.TO200-KR003T
19166827 | Nivå D | ORIGINAL | 6983.99 | 28 | +BR003=310.TO100-KR001T
19169156 | Nivå D | ORIGINAL | 334.075 | 22 | +BR003=310.TO200-KR003T
19169211 | Nivå D | ORIGINAL | 781.587 | 22 | +BR003=310.TO200-KR003T
19169253 | Nivå D | ORIGINAL | 770.837 | 28 | +BR003=310.TO100-KR001T
19169304 | Nivå D | ORIGINAL | 169.575 | 28 | +BR003=310.TO100-KR001T
19192308 | Nivå D | ORIGINAL | 3025.24 | 28 | +BR003=310.TO100-KR001T
19192318 | Nivå D | ORIGINAL | 3025.24 | 22 | +BR003=310.TO200-KR003T
19192476 | Nivå D | ORIGINAL | 394.321 | 22 | +BR003=310.TO200-KR003T | Group: 310.TO200 1
19192509 | Nivå D | ORIGINAL | 233.321 | 28 | +BR003=310.TO100-KR001T
19192653 | Nivå D | ORIGINAL | 44 | 28 | +BR003=310.TO100-KR001T
19192720 | Nivå D | ORIGINAL | 56 | 22 | +BR003=310.TO200-KR003T
19192774 | Nivå D | ORIGINAL | 2608 | 22 | +BR003=310.TO200-KR003T | Group: 310.TO200 1
19192795 | Nivå D | ORIGINAL | 2602 | 28 | +BR003=310.TO100-KR001T | Group: 310.TO100 78
19200038 | Nivå D | ORIGINAL | 90.6888 | 28 | +BR003=310.TO100-KR001T
19658979 | Nivå D | ORIGINAL | 233.321 | 28 | +BR003=310.TO100-KR001T
19659008 | Nivå D | ORIGINAL | 502.51 | 22 | +BR003=310.TO200-KR003T
19166557 | Nivå D | RESULT | 4078 | 28 | +BR003=310.TO200-KR003T | AVINOR - 01_Lufthavnkode: ENBR
19166602 | Nivå D | RESULT | 4072 | 35 | +BR003=310.TO100-KR001T | AVINOR - 01_Lufthavnkode: ENBR

# IfcFlowSegment: Pipe Types:MA (20)
ePset_Simplebim - Assembly Level: Leaf
AVINOR - 08_Status: S4; 07_Fase: F90
Name (Pipe Types:MA:...) | In | Splitting | Length (Simplebim) (mm) | Width (Simplebim) (mm) | Height (Simplebim) (mm) | 05_ID-nummer | 01_Lufthavnkode
6031140 | Nivå C | ORIGINAL | 804.045 | 75 | 75 | +BR003=310.TO500-KR006T | ENBR
6031736 | Nivå C | ORIGINAL | 779.937 | 110 | 110 | +BR003=310.TO500-KR006T | ENBR
8030607 | Nivå D | ORIGINAL | 724.081 | 135 | 135 | +BR003=310.SB803-KR007T | ENBR
8708246 | Nivå D | ORIGINAL | 119.885 | 110 | 111.952 | +BR003=310.TO500-KR006T
8708248 | Nivå D | ORIGINAL | 154.953 | 154.953 | 111.804 | +BR003=310.TO500-KR006T
8708253 | Nivå D | ORIGINAL | 355.047 | 75.0002 | 80.8841 | +BR003=310.TO500-KR006T
8708279 | Nivå C | ORIGINAL | 934.383 | 110 | 110 | +BR003=310.TO500-KR006T | ENBR
9049062 | Nivå D | ORIGINAL | 142.456 | 75.1033 | 75.5929 | +BR003=310.TO500-KR006T | Group: 310.TO500 22
10920417 | Nivå C | ORIGINAL | 808.903 | 75 | 75 | +BR003=310.TO500-KR006T | ENBR
15946447 | Nivå D | ORIGINAL | 111.303 | 80.9465 | 110 | +BR003=310.TO500-KR006T | Group: 310.TO500 22
15946458 | Nivå D | ORIGINAL | 144.715 | 110 | 110 | +BR003=310.TO500-KR006T
16645764 | Nivå C | ORIGINAL | 588.934 | 75 | 75 | +BR003=310.TO500-KR006T | ENBR
19152381 | Nivå D | ORIGINAL | 1403.37 | 75 | 75 | +BR003=310.TO500-KR006T | ENBR | Group: 310.TO500 22
19165741 | Nivå C | ORIGINAL | 1040.02 | 110 | 110 | +BR003=310.TO500-KR006T | ENBR | Group: 310.TO500 22
19173949 | Nivå C | ORIGINAL | 1510.68 | 75 | 75 | +BR003=310.TO500-KR006T | ENBR | Group: 310.TO500 22
19174209 | Nivå C | ORIGINAL | 1547.56 | 75 | 75 | +BR003=310.TO500-KR006T | ENBR | Group: 310.TO500 22
19174457 | Nivå C | ORIGINAL | 793.053 | 110 | 110 | +BR003=310.TO500-KR006T | ENBR | Group: 310.TO500 22
19174910 | Nivå C | ORIGINAL | 1428.53 | 75 | 75 | +BR003=310.TO500-KR006T | ENBR | Group: 310.TO500 22
19185895 | Nivå C | ORIGINAL | 1604.17 | 75 | 75 | +BR003=310.TO500-KR006T | ENBR | Group: 310.TO500 22
8028614 | Nivå D | RESULT | 4240 | 135 | 135 | +BR003=310.SB803-KR007T

# IfcFlowSegment: Pipe Types:PP avløpsrør, Pipe Types:PP avløpsrør:6031075
In: Nivå D
ePset_SimplebimBasicQuantities - Length (Simplebim): 270.24 mm; Width (Simplebim): 50 mm; Height (Simplebim): 50 mm
ePset_Simplebim - Assembly Level: Leaf
AVINOR - 08_Status: S4; 07_Fase: F90; 05_ID-nummer: +BR003=310.TO500-KR012T
ePset_LocationTool - Splitting: ORIGINAL
Group: 310.TO500 22

# IfcFlowSegment: Pipe Types:Rustfrie stålrør (8)
In: Nivå D
ePset_Simplebim - Assembly Level: Leaf
AVINOR - 08_Status: S4; 07_Fase: F90; 05_ID-nummer: +BR003=310.TO601-KR009T
Name (Pipe Types:Rustfrie stålrør:...) | Splitting | Length (Simplebim) (mm) | Width (Simplebim) (mm) | Height (Simplebim) (mm)
19165853 | ORIGINAL | 826.259 | 826.259 | 110
19165991 | ORIGINAL | 2420 | 110 | 110 | Group: 310.TO601
19168182 | ORIGINAL | 585.627 | 110 | 110
19168276 | ORIGINAL | 1831.03 | 110 | 110
19168277 | ORIGINAL | 163.345 | 110 | 163.345
19168318 | ORIGINAL | 5964.56 | 110 | 110
19168319 | ORIGINAL | 213.345 | 110 | 213.345
19168132 | RESULT | 1318 | 110 | 110

# IfcFlowSegment: Pipe Types:Stålrør normaltykke (128)
ePset_Simplebim - Assembly Level: Leaf
Name (Pipe Types:Stålrør normaltykke:...) | In | 08_Status | 07_Fase | 05_ID-nummer | Splitting | Width (Simplebim) (mm) | Height (Simplebim) (mm) | Length (Simplebim) (mm)
6588751 | Nivå C | S4 | F90 | +BR003=320.SB101-KR001T | ORIGINAL | 60.3 | 60.3 | 838
6588789 | Nivå C | S4 | F90 | +BR003=320.SB101-KR001T | ORIGINAL | 60.3 | 60.3 | 838
23480838 | Nivå D | S4 | F90 | +BR003=370.SB102-KR001T | ORIGINAL | 17.2 | 17.2 | 80 | Group: K 347
23480841 | Nivå D | S4 | F90 | +BR003=370.SB102-KR001T | ORIGINAL | 17.2 | 17.2 | 80 | Group: K 349
9498208 | Nivå D | S4 | F90 | +BR003=332.SB001-KR001T | ORIGINAL | 33.7 | 8.3199 | 33.7175 | Group: 332.SB001 (1) (2)
9498221 | Nivå D | S4 | F90 | +BR003=332.SB001-KR001T | ORIGINAL | 33.7 | 8.24815 | 33.7001 | Group: 332.SB001 (1) (2)
10175061 | Nivå D | S4 | F90 | +BR003=332.SB001-KR001T | ORIGINAL | 114.3 | 114.3 | 3218.68
10365431 | Nivå D | S4 | F90 | +BR003=332.SB001-KR001T | ORIGINAL | 33.7 | 33.7 | 47.8824
10365447 | Nivå D | S4 | F90 | +BR003=332.SB001-KR001T | ORIGINAL | 33.7 | 33.7 | 39.5417
10365456 | Nivå D | S4 | F90 | +BR003=332.SB001-KR001T | ORIGINAL | 33.7 | 33.7177 | 675.153 | Group: 332.SB001 (1) (2)
10365472 | Nivå D | S4 | F90 | +BR003=332.SB001-KR001T | ORIGINAL | 33.7 | 33.7 | 3216.9
10365508 | Nivå D | S4 | F90 | +BR003=332.SB001-KR001T | ORIGINAL | 33.7 | 33.7 | 68.2332
10365519 | Nivå D | S4 | F90 | +BR003=332.SB001-KR001T | ORIGINAL | 33.7 | 33.7 | 675.152 | Group: 332.SB001 (1) (2)
11007107 | Nivå D | S4 | F90 | +BR003=332.SB001-KR001T | ORIGINAL | 114.3 | 114.3 | 4321.04
11007168 | Nivå D | S4 | F90 | +BR003=332.SB001-KR001T | ORIGINAL | 33.7 | 9.24801 | 33.7 | Group: 332.SB001 (1) (2)
19828718 | Nivå D | S4 | F90 | +BR003=332.SB001-KR001T | ORIGINAL | 33.7 | 9.24801 | 33.7 | Group: 332.SB001 (1) (2)
19828761 | Nivå D | S4 | F90 | +BR003=332.SB001-KR001T | ORIGINAL | 33.7 | 9.24801 | 33.7 | Group: 332.SB001 (1) (2)
19828783 | Nivå D | S4 | F90 | +BR003=332.SB001-KR001T | ORIGINAL | 33.7 | 9.24801 | 33.7 | Group: 332.SB001 (1) (2)
19829300 | Nivå D | S4 | F90 | +BR003=332.SB001-KR001T | ORIGINAL | 33.7 | 17.698 | 33.7 | Group: 332.SB001 (1) (2)
19829324 | Nivå D | S4 | F90 | +BR003=332.SB001-KR001T | ORIGINAL | 33.7 | 9.24801 | 33.7 | Group: 332.SB001 (1) (2)
19829336 | Nivå D | S4 | F90 | +BR003=332.SB001-KR001T | ORIGINAL | 33.7 | 9.24807 | 33.7 | Group: 332.SB001 (1) (2)
19829619 | Nivå D | S4 | F90 | +BR003=332.SB001-KR001T | ORIGINAL | 33.7 | 9.24801 | 33.7 | Group: 332.SB001 (1) (2)
19830140 | Nivå D | S4 | F90 | +BR003=332.SB001-KR001T | ORIGINAL | 33.7 | 33.7 | 693.152
19830242 | Nivå D | S4 | F90 | +BR003=332.SB001-KR001T | ORIGINAL | 33.7001 | 33.7004 | 693.152
19830254 | Nivå D | S4 | F90 | +BR003=332.SB001-KR001T | ORIGINAL | 33.7 | 33.7 | 693.152
19830441 | Nivå D | S4 | F90 | +BR003=332.SB001-KR001T | ORIGINAL | 33.7 | 9.24801 | 33.7 | Group: 332.SB001 (1) (2)
19830494 | Nivå D | S4 | F90 | +BR003=332.SB001-KR001T | ORIGINAL | 33.7 | 9.24801 | 33.7 | Group: 332.SB001 (1) (2)
19830604 | Nivå D | S4 | F90 | +BR003=332.SB001-KR001T | ORIGINAL | 33.7 | 9.24801 | 33.7 | Group: 332.SB001 (1) (2)
19830614 | Nivå D | S4 | F90 | +BR003=332.SB001-KR001T | ORIGINAL | 33.7 | 9.24801 | 33.7 | Group: 332.SB001 (1) (2)
19830969 | Nivå D | S4 | F90 | +BR003=332.SB001-KR001T | ORIGINAL | 33.7 | 17.698 | 33.7 | Group: 332.SB001 (1) (2)
19830972 | Nivå D | S4 | F90 | +BR003=332.SB001-KR001T | ORIGINAL | 33.7 | 9.24801 | 33.7 | Group: 332.SB001 (1) (2)
19831094 | Nivå D | S4 | F90 | +BR003=332.SB001-KR001T | ORIGINAL | 33.7 | 9.24801 | 33.7 | Group: 332.SB001 (1) (2)
19831097 | Nivå D | S4 | F90 | +BR003=332.SB001-KR001T | ORIGINAL | 33.7 | 9.24801 | 33.7 | Group: 332.SB001 (1) (2)
19831177 | Nivå D | S4 | F90 | +BR003=332.SB001-KR001T | ORIGINAL | 33.7 | 9.24801 | 33.7 | Group: 332.SB001 (1) (2)
19831234 | Nivå D | S4 | F90 | +BR003=332.SB001-KR001T | ORIGINAL | 33.7 | 9.24801 | 33.7 | Group: 332.SB001 (1) (2)
19831237 | Nivå D | S4 | F90 | +BR003=332.SB001-KR001T | ORIGINAL | 33.7 | 9.24802 | 33.7 | Group: 332.SB001 (1) (2)
19831297 | Nivå D | S4 | F90 | +BR003=332.SB001-KR001T | ORIGINAL | 33.7 | 9.24801 | 33.7 | Group: 332.SB001 (1) (2)
19831381 | Nivå D | S4 | F90 | +BR003=332.SB001-KR001T | ORIGINAL | 33.7 | 33.7 | 43.28 | Group: 332.SB001 (1) (2)
19831406 | Nivå D | S4 | F90 | +BR003=332.SB001-KR001T | ORIGINAL | 33.7 | 33.7 | 229.9
19831567 | Nivå D | S4 | F90 | +BR003=332.SB001-KR001T | ORIGINAL | 33.7 | 33.7 | 841.2 | Group: 332.SB001 (1) (2)
19831603 | Nivå D | S4 | F90 | +BR003=332.SB001-KR001T | ORIGINAL | 33.7 | 9.24801 | 33.7 | Group: 332.SB001 (1) (2)
19831615 | Nivå D | S4 | F90 | +BR003=332.SB001-KR001T | ORIGINAL | 33.7 | 9.24801 | 33.7 | Group: 332.SB001 (1) (2)
19831652 | Nivå D | S4 | F90 | +BR003=332.SB001-KR001T | ORIGINAL | 33.7 | 33.7 | 3432.4
19831689 | Nivå D | S4 | F90 | +BR003=332.SB001-KR001T | ORIGINAL | 42.4 | 18.85 | 42.4
19831720 | Nivå D | S4 | F90 | +BR003=332.SB001-KR001T | ORIGINAL | 33.7 | 33.7 | 661.696
19831953 | Nivå D | S4 | F90 | +BR003=332.SB001-KR001T | ORIGINAL | 33.7 | 33.7 | 92.4
19831965 | Nivå D | S4 | F90 | +BR003=332.SB001-KR001T | ORIGINAL | 42.4 | 42.4 | 430.714
19831984 | Nivå D | S4 | F90 | +BR003=332.SB001-KR001T | ORIGINAL | 33.7 | 33.7 | 77.5802
19831987 | Nivå D | S4 | F90 | +BR003=332.SB001-KR001T | ORIGINAL | 33.7 | 33.7 | 1778.32
19832036 | Nivå D | S4 | F90 | +BR003=332.SB001-KR001T | ORIGINAL | 42.4 | 42.4 | 127.362
19832045 | Nivå D | S4 | F90 | +BR003=332.SB001-KR001T | ORIGINAL | 114.3 | 114.3 | 4146.43
19832086 | Nivå D | S4 | F90 | +BR003=332.SB001-KR001T | ORIGINAL | 33.7 | 33.7 | 94.8996
19832089 | Nivå D | S4 | F90 | +BR003=332.SB001-KR001T | ORIGINAL | 33.7 | 33.7 | 2861.72
19832116 | Nivå D | S4 | F90 | +BR003=332.SB001-KR001T | ORIGINAL | 32.6989 | 42.4 | 43.3584
19832144 | Nivå D | S4 | F90 | +BR003=332.SB001-KR001T | ORIGINAL | 33.7 | 33.7 | 78.7747
19832157 | Nivå D | S4 | F90 | +BR003=332.SB001-KR001T | ORIGINAL | 33.7 | 33.7 | 71.1302
19832322 | Nivå D | S4 | F90 | +BR003=332.SB001-KR001T | ORIGINAL | 33.7 | 33.7 | 1211.63
19832344 | Nivå D | S4 | F90 | +BR003=332.SB001-KR001T | ORIGINAL | 33.7 | 33.7 | 272.4
19832354 | Nivå D | S4 | F90 | +BR003=332.SB001-KR001T | ORIGINAL | 33.7 | 33.7 | 352.4
19832364 | Nivå D | S4 | F90 | +BR003=332.SB001-KR001T | ORIGINAL | 33.7 | 33.7 | 604.488
19832374 | Nivå D | S4 | F90 | +BR003=332.SB001-KR001T | ORIGINAL | 33.7 | 33.7 | 386.432
19832425 | Nivå D | S4 | F90 | +BR003=332.SB001-KR001T | ORIGINAL | 33.7 | 33.7 | 1692.1
19832438 | Nivå D | S4 | F90 | +BR003=332.SB001-KR001T | ORIGINAL | 33.7 | 33.7 | 2172.7
19832508 | Nivå D | S4 | F90 | +BR003=332.SB001-KR001T | ORIGINAL | 48.3 | 48.3 | 526.948
19832523 | Nivå D | S4 | F90 | +BR003=332.SB001-KR001T | ORIGINAL | 114.3 | 114.3 | 3792.8
19832544 | Nivå D | S4 | F90 | +BR003=332.SB001-KR001T | ORIGINAL | 48.3 | 48.3 | 215.337
19832560 | Nivå D | S4 | F90 | +BR003=332.SB001-KR001T | ORIGINAL | 48.3 | 48.3 | 614.408
19832570 | Nivå D | S4 | F90 | +BR003=332.SB001-KR001T | ORIGINAL | 48.3 | 48.3 | 50.3094
19832580 | Nivå D | S4 | F90 | +BR003=332.SB001-KR001T | ORIGINAL | 42.4 | 42.4 | 743.183
19832617 | Nivå D | S4 | F90 | +BR003=332.SB001-KR001T | ORIGINAL | 33.7 | 33.7 | 1747.4
19832641 | Nivå D | S4 | F90 | +BR003=332.SB001-KR001T | ORIGINAL | 33.7 | 33.7 | 233.378
19832644 | Nivå D | S4 | F90 | +BR003=332.SB001-KR001T | ORIGINAL | 48.3 | 48.3 | 815.147
19832697 | Nivå D | S4 | F90 | +BR003=332.SB001-KR001T | ORIGINAL | 33.7 | 33.7 | 1742.4
19832738 | Nivå D | S4 | F90 | +BR003=332.SB001-KR001T | ORIGINAL | 33.7 | 33.7 | 1733.8
19832789 | Nivå D | S4 | F90 | +BR003=332.SB001-KR001T | ORIGINAL | 42.4 | 42.4 | 210.228
19832799 | Nivå D | S4 | F90 | +BR003=332.SB001-KR001T | ORIGINAL | 42.4 | 42.4 | 1102.29
19832867 | Nivå D | S4 | F90 | +BR003=332.SB001-KR001T | ORIGINAL | 33.7 | 33.7 | 1098.8
19832944 | Nivå D | S4 | F90 | +BR003=332.SB001-KR001T | ORIGINAL | 33.7 | 33.7 | 572.4
19832950 | Nivå D | S4 | F90 | +BR003=332.SB001-KR001T | ORIGINAL | 33.7 | 33.7 | 2181.15
19832961 | Nivå D | S4 | F90 | +BR003=332.SB001-KR001T | ORIGINAL | 33.7 | 33.7 | 218.6
19832977 | Nivå D | S4 | F90 | +BR003=332.SB001-KR001T | ORIGINAL | 33.7 | 33.7 | 1732.4
19832987 | Nivå D | S4 | F90 | +BR003=332.SB001-KR001T | ORIGINAL | 60.3 | 60.3 | 430.296
19833031 | Nivå D | S4 | F90 | +BR003=332.SB001-KR001T | ORIGINAL | 33.7 | 33.7 | 1503.2
19833033 | Nivå D | S4 | F90 | +BR003=332.SB001-KR001T | ORIGINAL | 33.7 | 33.7 | 1297.9
19833037 | Nivå D | S4 | F90 | +BR003=332.SB001-KR001T | ORIGINAL | 33.7 | 33.7 | 503.2
19833353 | Nivå D | S4 | F90 | +BR003=332.SB001-KR001T | ORIGINAL | 33.7 | 33.7 | 319.9
19833430 | Nivå D | S4 | F90 | +BR003=332.SB001-KR001T | ORIGINAL | 60.3 | 60.3 | 98.5993
19833590 | Nivå D | S4 | F90 | +BR003=332.SB001-KR001T | ORIGINAL | 33.7 | 33.7 | 414.025
19833602 | Nivå D | S4 | F90 | +BR003=332.SB001-KR001T | ORIGINAL | 33.7 | 33.7 | 845.9
19833604 | Nivå D | S4 | F90 | +BR003=332.SB001-KR001T | ORIGINAL | 60.3 | 60.3 | 795.91
19833670 | Nivå D | S4 | F90 | +BR003=332.SB001-KR001T | ORIGINAL | 33.7 | 33.7 | 1774.19
19833691 | Nivå D | S4 | F90 | +BR003=332.SB001-KR001T | ORIGINAL | 33.7 | 33.7 | 218.6
19833716 | Nivå D | S4 | F90 | +BR003=332.SB001-KR001T | ORIGINAL | 33.7 | 33.7 | 2090.6
19833723 | Nivå D | S4 | F90 | +BR003=332.SB001-KR001T | ORIGINAL | 33.7 | 33.7 | 657.985
19833727 | Nivå D | S4 | F90 | +BR003=332.SB001-KR001T | ORIGINAL | 48.3 | 48.3 | 1992.31
19833741 | Nivå D | S4 | F90 | +BR003=332.SB001-KR001T | ORIGINAL | 33.7 | 33.7 | 78.7747
19833768 | Nivå D | S4 | F90 | +BR003=332.SB001-KR001T | ORIGINAL | 33.7 | 33.7 | 743.025
19833884 | Nivå D | S4 | F90 | +BR003=332.SB001-KR001T | ORIGINAL | 33.7 | 33.7 | 713.672
19834010 | Nivå D | S4 | F90 | +BR003=332.SB001-KR001T | ORIGINAL | 33.7 | 33.7 | 982.4
19834061 | Nivå D | S4 | F90 | +BR003=332.SB001-KR001T | ORIGINAL | 33.7 | 33.7 | 1583.62
19834092 | Nivå D | S4 | F90 | +BR003=332.SB001-KR001T | ORIGINAL | 33.7 | 33.7 | 66.2
19834144 | Nivå D | S4 | F90 | +BR003=332.SB001-KR001T | ORIGINAL | 33.7 | 12.4 | 33.7
19834150 | Nivå D | S4 | F90 | +BR003=332.SB001-KR001T | ORIGINAL | 33.7 | 33.7 | 152.4
19834160 | Nivå D | S4 | F90 | +BR003=332.SB001-KR001T | ORIGINAL | 33.7 | 12.4 | 33.7
19834257 | Nivå D | S4 | F90 | +BR003=332.SB001-KR001T | ORIGINAL | 33.7 | 33.7 | 782.4
19834398 | Nivå D | S4 | F90 | +BR003=332.SB001-KR001T | ORIGINAL | 33.7 | 18.85 | 33.7
19834413 | Nivå D | S4 | F90 | +BR003=332.SB001-KR001T | ORIGINAL | 114.3 | 114.3 | 2376.3
19834503 | Nivå D | S4 | F90 | +BR003=332.SB001-KR001T | ORIGINAL | 33.7 | 33.7 | 730.722
19834535 | Nivå D | S4 | F90 | +BR003=332.SB001-KR001T | ORIGINAL | 33.7 | 33.7 | 72.4
19834670 | Nivå D | S4 | F90 | +BR003=332.SB001-KR001T | ORIGINAL | 33.7 | 33.7 | 585.439
19834699 | Nivå D | S4 | F90 | +BR003=332.SB001-KR001T | ORIGINAL | 33.7 | 18.85 | 33.7
19834708 | Nivå D | S4 | F90 | +BR003=332.SB001-KR001T | ORIGINAL | 114.3 | 114.3 | 644.02
19834729 | Nivå D | S4 | F90 | +BR003=332.SB001-KR001T | ORIGINAL | 33.7 | 33.7 | 730.722
19834776 | Nivå D | S4 | F90 | +BR003=332.SB001-KR001T | ORIGINAL | 33.7 | 33.7 | 181.18
19834792 | Nivå D | S4 | F90 | +BR003=332.SB001-KR001T | ORIGINAL | 33.7 | 33.7 | 424.756
19834828 | Nivå D | S4 | F90 | +BR003=332.SB001-KR001T | ORIGINAL | 33.7 | 33.7 | 1980.6
19834873 | Nivå D | S4 | F90 | +BR003=332.SB001-KR001T | ORIGINAL | 60.3 | 67.4218 | 72.1291
19836970 | Nivå D | S4 | F90 | +BR003=332.SB001-KR001T | ORIGINAL | 33.7 | 33.7 | 127.833
19837045 | Nivå D | S4 | F90 | +BR003=332.SB001-KR001T | ORIGINAL | 33.7 | 10.7901 | 33.7
19837059 | Nivå D | S4 | F90 | +BR003=332.SB001-KR001T | ORIGINAL | 33.7 | 33.7 | 352.967
19837069 | Nivå D | S4 | F90 | +BR003=332.SB001-KR001T | ORIGINAL | 33.7 | 10.7901 | 33.7
20623527 | Nivå D |  |  |  | ORIGINAL | 33.7 | 33.7 | 841.2 | Group: 332.SB001 (1) (2)
20623535 | Nivå D |  |  |  | ORIGINAL | 33.7 | 33.7 | 392.831
6588746 | Nivå D | S4 | F90 | +BR003=320.SB101-KR001T | RESULT | 60 | 60 | 4222
6588784 | Nivå D | S4 | F90 | +BR003=320.SB101-KR001T | RESULT | 60 | 60 | 4222
10365352 | Nivå D | S4 | F90 | +BR003=332.SB001-KR001T | RESULT | 114 | 114 | 1586
10178875 | Nivå D | S4 | F90 | +BR003=332.SB001-KR001T | RESULT | 114 | 114 | 1003
19831705 | Nivå D | S4 | F90 | +BR003=332.SB001-KR001T | RESULT | 115 | 114 | 1140

# IfcFlowSegment: Pipe Types:Stålrør syrefast AISI 316 (58)
ePset_Simplebim - Assembly Level: Leaf
AVINOR - 08_Status: S4; 07_Fase: F90; 05_ID-nummer: +BR003=370.SB102-KR001T
Name (Pipe Types:Stålrør syrefast AISI 316:...) | In | Width (Simplebim) (mm) | Height (Simplebim) (mm) | Length (Simplebim) (mm) | Splitting
8708823 | Nivå C | 60.3 | 60.3 | 1239.6 | ORIGINAL
8708846 | Nivå C | 60.3 | 60.3 | 1284 | ORIGINAL
8709056 | Nivå D | 60.3 | 60.3 | 2921.6 | ORIGINAL
8709074 | Nivå D | 60.3 | 60.3 | 2877.2 | ORIGINAL
20453410 | Nivå D | 48.3 | 48.3 | 301.039 | ORIGINAL | Group: 370.SB102 T
20453413 | Nivå D | 48.3 | 48.3 | 321.384 | ORIGINAL | Group: 370.SB102 R
21083568 | Nivå D | 48.3 | 48.3191 | 252.61 | ORIGINAL | Group: 370.SB102 T
21083574 | Nivå D | 48.3 | 48.3228 | 236.519 | ORIGINAL | Group: 370.SB102 R
21083583 | Nivå D | 48.3 | 48.3207 | 453.54 | ORIGINAL
21083586 | Nivå D | 48.3 | 48.3 | 523.2 | ORIGINAL
21083597 | Nivå D | 48.3 | 48.3303 | 253.542 | ORIGINAL
21083604 | Nivå D | 48.3 | 48.3 | 496.926 | ORIGINAL
21083618 | Nivå D | 48.3 | 48.3 | 1855.89 | ORIGINAL
21083621 | Nivå D | 33.7 | 33.7 | 194.72 | ORIGINAL | Group: 370.SB102 T
21083628 | Nivå D | 48.3 | 48.3 | 1855.89 | ORIGINAL
21083631 | Nivå D | 33.7 | 33.7 | 185.72 | ORIGINAL | Group: 370.SB102 R
21083663 | Nivå D | 48.3 | 48.3284 | 246.254 | ORIGINAL
21083675 | Nivå D | 48.3 | 48.3404 | 244.753 | ORIGINAL
21083686 | Nivå D | 48.3 | 48.3 | 252.607 | ORIGINAL
21083700 | Nivå D | 48.3 | 48.3 | 252.607 | ORIGINAL
21083728 | Nivå D | 33.7 | 33.7 | 229.9 | ORIGINAL
21083731 | Nivå D | 48.3 | 48.3 | 1674.12 | ORIGINAL
21083740 | Nivå D | 33.7 | 33.7 | 229.9 | ORIGINAL
21083743 | Nivå D | 48.3 | 48.3 | 1214.68 | ORIGINAL
21394819 | Nivå D | 26.7 | 26.7 | 211.199 | ORIGINAL | Group: 370.SB102 R
21394902 | Nivå D | 26.7 | 26.7 | 257.199 | ORIGINAL | Group: 370.SB102 T
21395451 | Nivå D | 26.7 | 26.7 | 47.85 | ORIGINAL
21395454 | Nivå D | 33.7 | 33.7 | 5812.99 | ORIGINAL
21395508 | Nivå D | 26.7 | 26.7 | 47.85 | ORIGINAL
21395511 | Nivå D | 33.7 | 33.7 | 5762.99 | ORIGINAL
21395632 | Nivå D | 26.7 | 26.7 | 3118.5 | ORIGINAL
21395642 | Nivå D | 26.7 | 26.7 | 1451.4 | ORIGINAL
21395654 | Nivå D | 26.7 | 26.7 | 836.4 | ORIGINAL
21395873 | Nivå D | 26.7 | 26.7 | 3416.7 | ORIGINAL
21395879 | Nivå D | 26.7 | 26.7 | 1511.4 | ORIGINAL
21395947 | Nivå D | 26.7 | 26.7 | 838.2 | ORIGINAL
21396250 | Nivå D | 26.7 | 26.7 | 211.607 | ORIGINAL | Group: 370.SB102 T
21396260 | Nivå D | 26.7 | 26.7 | 83.2 | ORIGINAL | Group: 370.SB102 T
21396293 | Nivå D | 26.7 | 26.7 | 46.4 | ORIGINAL
21396317 | Nivå D | 26.7 | 26.7 | 160.607 | ORIGINAL | Group: 370.SB102 R
21396326 | Nivå D | 26.7 | 26.7 | 83.2 | ORIGINAL | Group: 370.SB102 R
21396352 | Nivå D | 26.7 | 26.7 | 46.4 | ORIGINAL
21396429 | Nivå D | 26.7 | 26.7 | 426.755 | ORIGINAL | Group: 370.SB102 T
21396463 | Nivå D | 26.7 | 26.7 | 445.82 | ORIGINAL | Group: 370.SB102 T
21396519 | Nivå D | 26.7 | 26.7 | 73.2865 | ORIGINAL | Group: 370.SB102 R
21396546 | Nivå D | 26.7 | 26.7 | 125.883 | ORIGINAL | Group: 370.SB102 R
21396619 | Nivå D | 26.7 | 26.7 | 400.506 | ORIGINAL | Group: 370.SB102 R
21396646 | Nivå D | 26.7 | 26.7 | 426.755 | ORIGINAL | Group: 370.SB102 R
22136600 | Nivå D | 33.7 | 33.7 | 2109.68 | ORIGINAL | Group: 370.SB102 R
22136605 | Nivå D | 33.7 | 33.7 | 2368.72 | ORIGINAL | Group: 370.SB102 T
22136609 | Nivå D | 33.7 | 33.7 | 158.125 | ORIGINAL | Group: 370.SB102 R
22136612 | Nivå D | 48.3 | 48.3 | 2936.24 | ORIGINAL
22136617 | Nivå D | 33.7 | 33.7 | 167.125 | ORIGINAL | Group: 370.SB102 T
22136620 | Nivå D | 48.3 | 48.3 | 2916.44 | ORIGINAL
22136626 | Nivå D | 33.7 | 33.7 | 75.575 | ORIGINAL | Group: 370.SB102 R
22136683 | Nivå D | 33.7 | 33.7 | 295.525 | ORIGINAL | Group: 370.SB102 T
20453394 | Nivå D | 60 | 61 | 1202 | RESULT
20453400 | Nivå D | 60 | 60 | 1202 | RESULT

# IfcFlowSegment: Rectangular Duct:KK002T - Rektangulære, Forsinket stål (4)
ePset_Simplebim - Assembly Level: Leaf
ePset_LocationTool - Splitting: ORIGINAL
AVINOR - 08_Status: S4; 07_Fase: F90
Name (Rectangular Duct:KK002T - Rektangulære, Forsinket stål:...) | In | Height (Simplebim) (mm) | Width (Simplebim) (mm) | Length (Simplebim) (mm) | 05_ID-nummer | Group
5717182 | Nivå E | 252.133 | 1000 | 1250 | +BR003=360.SB110-KK002T | 360.SB110 T
5717188 | Nivå E | 572.646 | 1000 | 1250 | +BR003=360.SB110-KK002T | 360.SB110 T
22034212 | Nivå D | 530 | 1400 | 2000 | +BR003=360.SB113-KK002T | 360.SB113 A
22064582 | Nivå D | 530 | 1300 | 1300 | +BR003=360.SB113-KK002T | 360.SB113 A

# IfcFlowSegment: Round Duct:KK001T - Spiro kanaler, Forsinket stål (87)
ePset_Simplebim - Assembly Level: Leaf
AVINOR - 08_Status: S4; 07_Fase: F90
Name (Round Duct:KK001T - Spiro kanaler, Forsinket stål:...) | In | Splitting | Height (Simplebim) (mm) | Width (Simplebim) (mm) | Length (Simplebim) (mm) | 05_ID-nummer | Group
5561568 | Nivå C | ORIGINAL | 114.246 | 1000 | 1000 | +BR003=360.SB111-KK001T | 360.SB111 A
5561599 | Nivå C | ORIGINAL | 110 | 1000 | 1000 | +BR003=360.SB112-KK001T | 360.SB112 A
7335645 | Nivå D | ORIGINAL | 500 | 500 | 380.196 | +BR003=360.SB113-KK001T | 360.SB113 T
7335663 | Nivå D | ORIGINAL | 386.543 | 500 | 500 | +BR003=360.SB113-KK001T | 360.SB113 T
12339971 | Nivå C | ORIGINAL | 400 | 400 | 1234.31 | +BR003=360.SB114-KK001T | 360.SB114 T
12340320 | Nivå C | ORIGINAL | 400 | 400 | 1180.98 | +BR003=360.SB114-KK001T | 360.SB114 A
13082282 | Nivå D | ORIGINAL | 500 | 500 | 2474.75 | +BR003=360.SB113-KK001T | 360.SB113 T
13271975 | Nivå D | ORIGINAL | 500 | 500 | 79.6587 | +BR003=360.SB113-KK001T | 360.SB113 T
13327755 | Nivå D | ORIGINAL | 100 | 160 | 160 | +BR003=360.SB113-KK001T | 360.SB113 A
13327761 | Nivå D | ORIGINAL | 200.017 | 200 | 1065.03 | +BR003=360.SB113-KK001T | 360.SB113 A
13385609 | Nivå D | ORIGINAL | 500 | 500 | 180 | +BR003=360.SB113-KK001T | 360.SB113 A
13399975 | Nivå D | ORIGINAL | 200 | 200 | 27.5 | +BR003=360.SB113-KK001T | 360.SB113 A
13404551 | Nivå D | ORIGINAL | 200 | 200 | 27.5 | +BR003=360.SB113-KK001T | 360.SB113 A
13404801 | Nivå D | ORIGINAL | 125.028 | 125 | 292.936 | +BR003=360.SB113-KK001T | 360.SB113 T
13404809 | Nivå D | ORIGINAL | 122.929 | 122.929 | 125.026 | +BR003=360.SB113-KK001T | 360.SB113 T
13404819 | Nivå D | ORIGINAL | 125 | 125 | 722.958 | +BR003=360.SB113-KK001T | 360.SB113 T
13404924 | Nivå D | ORIGINAL | 269.415 | 160 | 269.415 | +BR003=360.SB113-KK001T | 360.SB113 T
13404966 | Nivå D | ORIGINAL | 160 | 160 | 172.763 | +BR003=360.SB113-KK001T | 360.SB113 T
13405083 | Nivå D | ORIGINAL | 125.009 | 125 | 1142.77 | +BR003=360.SB113-KK001T | 360.SB113 T
13405116 | Nivå D | ORIGINAL | 125 | 125 | 243.076 | +BR003=360.SB113-KK001T | 360.SB113 T
14282860 | Nivå D | ORIGINAL | 1000 | 1000 | 3500.75 | +BR003=360.SB111-KK001T | 360.SB111 A
14282905 | Nivå D | ORIGINAL | 1000 | 1000 | 3506.5 | +BR003=360.SB112-KK001T | 360.SB112 A
16842945 | Nivå D | ORIGINAL | 125.022 | 125 | 693.202 | +BR003=360.SB113-KK001T | 360.SB113 A
18021351 | Nivå D | ORIGINAL | 182.947 | 199.542 | 200.832 | +BR003=360.SB113-KK001T | 360.SB113 A
22033864 | Nivå D | ORIGINAL | 500 | 329.273 | 536.516 | +BR003=360.SB113-KK001T | 360.SB113 A
22034005 | Nivå D | ORIGINAL | 500 | 500 | 1647.76 | +BR003=360.SB113-KK001T | 360.SB113 A
22034428 | Nivå D | ORIGINAL | 400 | 400 | 660 | +BR003=360.SB113-KK001T | 360.SB113 A
22034482 | Nivå D | ORIGINAL | 400 | 400 | 490 | +BR003=360.SB113-KK001T | 360.SB113 A
22034526 | Nivå D | ORIGINAL | 500 | 500 | 1335.36 | +BR003=360.SB113-KK001T | 360.SB113 A
22034590 | Nivå D | ORIGINAL | 400 | 400 | 575 | +BR003=360.SB113-KK001T | 360.SB113 A
22034605 | Nivå D | ORIGINAL | 400 | 400 | 493.013 | +BR003=360.SB113-KK001T | 360.SB113 A
22034656 | Nivå D | ORIGINAL | 400 | 400 | 540.312 | +BR003=360.SB113-KK001T | 360.SB113 A
22035462 | Nivå D | ORIGINAL | 315 | 315 | 3344.73 | +BR003=360.SB113-KK001T | 360.SB113 A
22035514 | Nivå D | ORIGINAL | 250 | 250 | 1596.42 | +BR003=360.SB113-KK001T | 360.SB113 A
22035599 | Nivå D | ORIGINAL | 250 | 250 | 35.7877 | +BR003=360.SB113-KK001T | 360.SB113 A
22035656 | Nivå D | ORIGINAL | 315 | 315 | 1596.42 | +BR003=360.SB113-KK001T | 360.SB113 A
22035723 | Nivå D | ORIGINAL | 315 | 315 | 370 | +BR003=360.SB113-KK001T | 360.SB113 A
22035852 | Nivå D | ORIGINAL | 315 | 315 | 351 | +BR003=360.SB113-KK001T | 360.SB113 A
22036345 | Nivå D | ORIGINAL | 459.038 | 295.077 | 500 | +BR003=360.SB113-KK001T | 360.SB113 T
22036362 | Nivå D | ORIGINAL | 500 | 500 | 1158.15 | +BR003=360.SB113-KK001T | 360.SB113 T
22036439 | Nivå D | ORIGINAL | 500 | 500 | 1092.6 | +BR003=360.SB113-KK001T | 360.SB113 T
22036447 | Nivå D | ORIGINAL | 315 | 315 | 1292.41 | +BR003=360.SB113-KK001T | 360.SB113 T
22057833 | Nivå D | ORIGINAL | 500 | 500 | 3974.33 | +BR003=360.SB113-KK001T | 360.SB113 A
22057878 | Nivå D | ORIGINAL | 500 | 500 | 2054.05 | +BR003=360.SB113-KK001T | 360.SB113 T
22057971 | Nivå D | ORIGINAL | 500 | 500 | 53.75 | +BR003=360.SB113-KK001T | 360.SB113 T
22058238 | Nivå D | ORIGINAL | 400 | 400 | 736.41 | +BR003=360.SB113-KK001T | 360.SB113 A
22058354 | Nivå D | ORIGINAL | 400 | 360.77 | 439.23 | +BR003=360.SB113-KK001T | 360.SB113 A
22058751 | Nivå D | ORIGINAL | 250 | 250 | 194.852 | +BR003=360.SB113-KK001T | 360.SB113 T
22058947 | Nivå D | ORIGINAL | 250 | 250 | 2687.56 | +BR003=360.SB113-KK001T | 360.SB113 T
22059374 | Nivå D | ORIGINAL | 315 | 315 | 485 | +BR003=360.SB113-KK001T | 360.SB113 T
22059397 | Nivå D | ORIGINAL | 250 | 250 | 425 | +BR003=360.SB113-KK001T | 360.SB113 T
22059663 | Nivå D | ORIGINAL | 250 | 250 | 121.547 | +BR003=360.SB113-KK001T | 360.SB113 T
22059757 | Nivå D | ORIGINAL | 230.33 | 230.33 | 250 | +BR003=360.SB113-KK001T | 360.SB113 T
22059827 | Nivå D | ORIGINAL | 250 | 250 | 236.447 | +BR003=360.SB113-KK001T | 360.SB113 T
22059829 | Nivå D | ORIGINAL | 230.33 | 230.33 | 250 | +BR003=360.SB113-KK001T | 360.SB113 T
22059849 | Nivå D | ORIGINAL | 250 | 250 | 174.852 | +BR003=360.SB113-KK001T | 360.SB113 T
22059882 | Nivå D | ORIGINAL | 250 | 250 | 161.547 | +BR003=360.SB113-KK001T | 360.SB113 T
22059884 | Nivå D | ORIGINAL | 230.33 | 230.33 | 250 | +BR003=360.SB113-KK001T | 360.SB113 T
22059904 | Nivå D | ORIGINAL | 250 | 250 | 197.352 | +BR003=360.SB113-KK001T | 360.SB113 T
22059937 | Nivå D | ORIGINAL | 250 | 250 | 141.579 | +BR003=360.SB113-KK001T | 360.SB113 T
22059939 | Nivå D | ORIGINAL | 230.33 | 230.33 | 250 | +BR003=360.SB113-KK001T | 360.SB113 T
22059963 | Nivå D | ORIGINAL | 250 | 250 | 176.447 | +BR003=360.SB113-KK001T | 360.SB113 T
22059965 | Nivå D | ORIGINAL | 230.33 | 230.33 | 250 | +BR003=360.SB113-KK001T | 360.SB113 T
22060003 | Nivå D | ORIGINAL | 250 | 250 | 859.753 | +BR003=360.SB113-KK001T | 360.SB113 T
22060048 | Nivå D | ORIGINAL | 250 | 250 | 53.4428 | +BR003=360.SB113-KK001T | 360.SB113 T
22060050 | Nivå D | ORIGINAL | 230.33 | 230.33 | 250 | +BR003=360.SB113-KK001T | 360.SB113 T
22060077 | Nivå D | ORIGINAL | 250 | 250 | 640.422 | +BR003=360.SB113-KK001T | 360.SB113 T
22060095 | Nivå D | ORIGINAL | 250 | 250 | 96.3466 | +BR003=360.SB113-KK001T | 360.SB113 T
22060097 | Nivå D | ORIGINAL | 230.33 | 230.33 | 250 | +BR003=360.SB113-KK001T | 360.SB113 T
22060111 | Nivå D | ORIGINAL | 250 | 250 | 58.5217 | +BR003=360.SB113-KK001T | 360.SB113 T
22061004 | Nivå D | ORIGINAL | 315 | 315 | 5537.46 | +BR003=360.SB113-KK001T | 360.SB113 T
22061051 | Nivå D | ORIGINAL | 160 | 160 | 4175 | +BR003=360.SB113-KK001T | 360.SB113 T
22061080 | Nivå D | ORIGINAL | 160 | 160 | 1210 | +BR003=360.SB113-KK001T | 360.SB113 T
22063618 | Nivå D | ORIGINAL | 146 | 315 | 315 | +BR003=360.SB113-KK001T | 360.SB113 A
22063642 | Nivå D | ORIGINAL | 107 | 315 | 315 | +BR003=360.SB113-KK001T | 360.SB113 A
22064314 | Nivå D | ORIGINAL | 315 | 315 | 322 | +BR003=360.SB113-KK001T | 360.SB113 A
22077326 | Nivå D | ORIGINAL | 400 | 400 | 1215.64 | +BR003=360.SB113-KK001T | 360.SB113 A
22077406 | Nivå D | ORIGINAL | 389.23 | 274.167 | 400 | +BR003=360.SB113-KK001T | 360.SB113 A
22090771 | Nivå D | ORIGINAL | 200 | 200 | 70 | +BR003=360.SB113-KK001T | 360.SB113 OVS
22091927 | Nivå D | ORIGINAL | 250 | 250 | 545 | +BR003=360.SB113-KK001T | 360.SB113 T
22091943 | Nivå D | ORIGINAL | 250 | 250 | 1750 | +BR003=360.SB113-KK001T | 360.SB113 T
22091953 | Nivå D | ORIGINAL | 250 | 250 | 1075 | +BR003=360.SB113-KK001T | 360.SB113 T
22117714 | Nivå D | ORIGINAL | 250 | 250 | 470 | +BR003=360.SB113-KK001T | 360.SB113 A
22117972 | Nivå D | ORIGINAL | 200 | 200 | 27.5 | +BR003=360.SB113-KK001T | 360.SB113 OVS
22118098 | Nivå D | ORIGINAL | 200 | 200 | 75.5801 | +BR003=360.SB113-KK001T | 360.SB113 OVS
14276198 | Nivå D | RESULT | 1250 | 1250 | 3348 | +BR003=360.SB110-KK001T | 360.SB110 T
7936095 | Nivå D | RESULT | 160 | 160 | 524 | +BR003=360.SB113-KK001T | 360.SB113 T

# IfcFlowTerminal: A271 - Stellebord_JJ:A271 - 80x900_JJ, A271 - Stellebord_JJ:A271 - 80x900_JJ:24247377
In: Nivå D-H01
Type - Material: NSW - white våtrom
ePset_Simplebim - Assembly Level: Leaf
ePset_LocationTool - Splitting: ORIGINAL

# IfcFlowTerminal: A274 - Armstøtte HWC:A274 - Armstøtte HWC, A274 - Armstøtte HWC:A274 - Armstøtte HWC:28179810
In: Nivå D-H01
Type - Material: <Unnamed>
ePset_Simplebim - Assembly Level: Leaf
ePset_LocationTool - Splitting: ORIGINAL

# IfcFlowTerminal: A274 - Avfall Liten:A274 - Avfall Liten, A274 - Avfall Liten:A274 - Avfall Liten:26246828
In: Nivå D-H01
Type - Material: NSW - white våtrom
ePset_Simplebim - Assembly Level: Leaf
ePset_LocationTool - Splitting: ORIGINAL

# IfcFlowTerminal: A274 - Avfall:A274 - Avfall, A274 - Avfall:A274 - Avfall:26246831
In: Nivå D-H01
Type - Material: NSW - white våtrom
ePset_LocationTool - Splitting: ORIGINAL
ePset_Simplebim - Assembly Level: Leaf

# IfcFlowTerminal: A274 - Håndtørkepapir:A274 - Håndtorke-papir - 330 x 330 x 220 mm, A274 - Håndtørkepapir:A274 - Håndtorke-papir - 330 x 330 x 220 mm:26246829
In: Nivå D-H01
Type - Material: NSW - white våtrom
ePset_Simplebim - Assembly Level: Leaf
ePset_LocationTool - Splitting: ORIGINAL

# IfcFlowTerminal: A274 - Kleshenger:A274 - Kleshenger, A274 - Kleshenger:A274 - Kleshenger:35264569
In: Nivå D-H01
Type - Material: <Unnamed>
ePset_Simplebim - Assembly Level: Leaf
ePset_LocationTool - Splitting: ORIGINAL

# IfcFlowTerminal: A274 - Såp dispenser-berøringsfri:Såp-berøringsfri (2)
In: Nivå D-H01
Type - Material: Satin, GFRP
Material: GFRP, Satin
ePset_Simplebim - Assembly Level: Leaf
ePset_LocationTool - Splitting: ORIGINAL
Name (A274 - Såp dispenser-berøringsfri:Såp-berøringsfri:...)
27156612
27156613

# IfcFlowTerminal: A274 - Såpedisp:A274 - Såpedispenser 80x150 mm, A274 - Såpedisp:A274 - Såpedispenser 80x150 mm:26837138
In: Nivå D-H01
Type - Material: NSW - white våtrom
ePset_Simplebim - Assembly Level: Leaf
ePset_LocationTool - Splitting: ORIGINAL

# IfcFlowTerminal: A274 - Toalettrull &Avfall Liten:A274 - Toalettrull 350x350mm, A274 - Toalettrull &Avfall Liten:A274 - Toalettrull 350x350mm:26246827
In: Nivå D-H01
Type - Material: NSW - white våtrom
ePset_Simplebim - Assembly Level: Leaf
ePset_LocationTool - Splitting: ORIGINAL

# IfcFlowTerminal: A274 - Vegghengt speil:A274 - GL01 Speil_Vegg hengt-HWC, A274 - Vegghengt speil:A274 - GL01 Speil_Vegg hengt-HWC:26865514
In: Nivå D-H01
Type - Material: Speil
ePset_Simplebim - Assembly Level: Leaf
ePset_LocationTool - Splitting: ORIGINAL

# IfcFlowTerminal: A274 - Vegghengt speil:A274 - GL04 Speil_Veg hengt-1800mm, A274 - Vegghengt speil:A274 - GL04 Speil_Veg hengt-1800mm:26865548
In: Nivå D-H01
Type - Material: Speil
ePset_Simplebim - Assembly Level: Leaf
ePset_LocationTool - Splitting: ORIGINAL

# IfcFlowTerminal: A274 - Vegghengt speil:A274 - GL08 Speil_Vegg hengt-600mm, A274 - Vegghengt speil:A274 - GL08 Speil_Vegg hengt-600mm:26865549
In: Nivå D-H01
Type - Material: Speil
ePset_Simplebim - Assembly Level: Leaf
ePset_LocationTool - Splitting: ORIGINAL

# IfcFlowTerminal: A274 - WC Børste:A274 - WC Børste, A274 - WC Børste:A274 - WC Børste:25050403
In: Nivå D-H01
Type - Material: <Unnamed>
ePset_Simplebim - Assembly Level: Leaf
ePset_LocationTool - Splitting: ORIGINAL

# IfcFlowTerminal: A278 - Brannskap innfelt i innbyggingsskap:A278 - Brannskap innfelt i innbyggingsskap, A278 - Brannskap innfelt i innbyggingsskap:A278 - Brannskap innfelt i innbyggingsskap:26765547
In: Nivå D-H01
Type - Material: <Unnamed>
ePset_Simplebim - Assembly Level: Leaf
ePset_LocationTool - Splitting: ORIGINAL

# IfcFlowTerminal: A315 - 3D Gulvsluk:Sluk (2)
In: Nivå D-H01
Type - Material: <Unnamed>
ePset_Simplebim - Assembly Level: Leaf
ePset_LocationTool - Splitting: ORIGINAL
Name (A315 - 3D Gulvsluk:Sluk:...)
28710394
37112398

# IfcFlowTerminal: A315 - 3D HC Vask:A315 - 3D HC Vask - 560 x 600 mm, A315 - 3D HC Vask:A315 - 3D HC Vask - 560 x 600 mm:19469878
In: Nivå D-H01
Type - Material: NSW - white våtrom
ePset_Simplebim - Assembly Level: Leaf
ePset_LocationTool - Splitting: ORIGINAL

# IfcFlowTerminal: A315 - 3D HC toalett med cisterne:Standard, A315 - 3D HC toalett med cisterne:Standard:28179128
In: Nivå D-H01
Type - Material: Ifö porcelain
Material: <Unnamed>
ePset_Simplebim - Assembly Level: Leaf
ePset_LocationTool - Splitting: ORIGINAL

# IfcFlowTerminal: A315 - 3D Vasken-Renhold:400 x 500mm, A315 - 3D Vasken-Renhold:400 x 500mm:27498216
In: Nivå D-H01
Type - Material: Porcelain
Classification: D2010440 Sinks - Service (Uniformat)
ePset_Simplebim - Assembly Level: Leaf
ePset_LocationTool - Splitting: ORIGINAL

# IfcFlowTerminal: A315 - Armatur:L983C, A315 - Armatur:L983C:27532098
In: Nivå D-H01
Type - Material: <Unnamed>
ePset_Simplebim - Assembly Level: Leaf
ePset_LocationTool - Splitting: ORIGINAL

# IfcFlowTerminal: A315 - Armatur:sink mounted faucet, A315 - Armatur:sink mounted faucet:28754496
In: Nivå D-H01
Type - Material: <Unnamed>
ePset_LocationTool - Splitting: ORIGINAL
ePset_Simplebim - Assembly Level: Leaf

# IfcFlowTerminal: BRANNSKAP - 2 - UO:BRANNSKAP - - UO001T, BRANNSKAP - 2 - UO:BRANNSKAP - - UO001T:10911357
In: Nivå D
Type - Material: <Unnamed>
ePset_Simplebim - Assembly Level: Leaf
AVINOR - 08_Status: S4; 07_Fase: F90; 05_ID-nummer: +BR003=331.00400-UO019
ePset_LocationTool - Splitting: ORIGINAL

# IfcFlowTerminal: BUS Snorbryter:Binary receiver, BUS Snorbryter:Binary receiver:4207578
In: Nivå D
Type - Material: <Unnamed>
ePset_Simplebim - Assembly Level: Leaf
AVINOR - 08_Status: S4; 07_Fase: F90; 05_ID-nummer: +BR003=564.SD0504-XS026
ePset_LocationTool - Splitting: ORIGINAL

# IfcFlowTerminal: BUS Tilstede på vegg +1100 180° r=8m PH:Move detector 3, BUS Tilstede på vegg +1100 180° r=8m PH:Move detector 3:4155016
In: Nivå D
Type - Material: <Unnamed>
AVINOR - 08_Status: S4; 07_Fase: F90; 05_ID-nummer: +BR003=564.SD0504-RB025
ePset_Simplebim - Assembly Level: Leaf
ePset_LocationTool - Splitting: ORIGINAL

# IfcFlowTerminal: Downlight Ø200 LED32W glatt:-UP1207 DL 200 RAL 9010, Downlight Ø200 LED32W glatt:-UP1207 DL 200 RAL 9010:3343406
In: Nivå D
Type - Material: <Unnamed>
ePset_Simplebim - Assembly Level: Leaf
AVINOR - 08_Status: S4; 07_Fase: F90; 05_ID-nummer: +BR003=442.00001-UP1207T
ePset_LocationTool - Splitting: ORIGINAL
Group: =433.SD121-KW28

# IfcFlowTerminal: FRALUFTSVENTIL - - SF001T:FRALUFTSVENTIL - KSO 125 - SF001T, FRALUFTSVENTIL - - SF001T:FRALUFTSVENTIL - KSO 125 - SF001T:16842743
In: Nivå D
Type - Material: <Unnamed>
ePset_LocationTool - Splitting: ORIGINAL
AVINOR - 08_Status: S4; 07_Fase: F90; 05_ID-nummer: +BR003=360.TO001-SF001T
ePset_Simplebim - Assembly Level: Leaf
Group: 360.SB113 A

# IfcFlowTerminal: FRALUFTSVENTIL - - SF002T:FRALUFTSVENTIL - NETTING-200 - SF002T (2)
In: Nivå D
Type - Material: <Unnamed>
ePset_LocationTool - Splitting: ORIGINAL
ePset_Simplebim - Assembly Level: Leaf
AVINOR - 08_Status: S4; 07_Fase: F90; 05_ID-nummer: +BR003=360.TO001-SF002T
Group: 360.SB113 OVS
Name (FRALUFTSVENTIL - - SF002T:FRALUFTSVENTIL - NETTING-200 - SF002T:...)
22090841
22118100

# IfcFlowTerminal: FRALUFTSVENTIL - - SF002T:FRALUFTSVENTIL - NETTING-250 - SF002T, FRALUFTSVENTIL - - SF002T:FRALUFTSVENTIL - NETTING-250 - SF002T:22122182
In: Nivå D
Type - Material: <Unnamed>
ePset_Simplebim - Assembly Level: Leaf
AVINOR - 08_Status: S4; 07_Fase: F90; 05_ID-nummer: +BR003=360.TO001-SF002T
ePset_LocationTool - Splitting: ORIGINAL
Group: 360.SB113 A

# IfcFlowTerminal: FRALUFTSVENTIL - 1 - SF001T:FRALUFTSVENTIL - BALANCE-E-160 - SF001T, FRALUFTSVENTIL - 1 - SF001T:FRALUFTSVENTIL - BALANCE-E-160 - SF001T:8669098
In: Nivå D
Type - Material: <Unnamed>
AVINOR - 08_Status: S4; 07_Fase: F90; 05_ID-nummer: +BR003=360.TO001-SF001T
ePset_Simplebim - Assembly Level: Leaf
ePset_LocationTool - Splitting: ORIGINAL
Group: 360.SB113 A

# IfcFlowTerminal: HC VASK - - NY:HC VASK - - NY005T, HC VASK - - NY:HC VASK - - NY005T:10888927
In: Nivå D
Type - Material: NSW - white våtrom
ePset_Simplebim - Assembly Level: Leaf
AVINOR - 05_ID-nummer: +BR003=310.TO500-NY005T; 08_Status: S4; 07_Fase: F90
ePset_LocationTool - Splitting: ORIGINAL

# IfcFlowTerminal: HCWC - - NX:HCWC - - NX003T, HCWC - - NX:HCWC - - NX003T:10884926
In: Nivå D
Type - Material: <Unnamed>, NSW - white våtrom
ePset_Simplebim - Assembly Level: Leaf
AVINOR - 08_Status: S4; 07_Fase: F90; 05_ID-nummer: +BR003=310.TO500-NX003T
ePset_LocationTool - Splitting: ORIGINAL
Group: 310.TO500 1 (47)

# IfcFlowTerminal: KJØKKENHETTE - FA:KJØKKENHETTE - Kjøkkenhette 1300x1300 - FA002T, KJØKKENHETTE - FA:KJØKKENHETTE - Kjøkkenhette 1300x1300 - FA002T:22064396
In: Nivå D
Type - Material: <Unnamed>
ePset_Simplebim - Assembly Level: Leaf
ePset_LocationTool - Splitting: ORIGINAL
AVINOR - 08_Status: S4; 07_Fase: F90; 05_ID-nummer: +BR003=360.PB113-FA002
Group: 360.SB113 A

# IfcFlowTerminal: KJØKKENHETTE - FA:KJØKKENHETTE - kjøkkenhette 2000x1400 - FA013T, KJØKKENHETTE - FA:KJØKKENHETTE - kjøkkenhette 2000x1400 - FA013T:22063950
In: Nivå D
Type - Material: <Unnamed>
ePset_Simplebim - Assembly Level: Leaf
ePset_LocationTool - Splitting: ORIGINAL
AVINOR - 08_Status: S4; 07_Fase: F90; 05_ID-nummer: +BR003=360.PB113-FA001
Group: 360.SB113 A

# IfcFlowTerminal: Ledelys bredstrålende LED innfelt:-UN6200 RAL 9010, Ledelys bredstrålende LED innfelt:-UN6200 RAL 9010:5563343
In: Nivå D
Type - Material: magi2D, <Unnamed>
ePset_Simplebim - Assembly Level: Leaf
ePset_LocationTool - Splitting: ORIGINAL
AVINOR - 08_Status: S4; 07_Fase: F90; 05_ID-nummer: +BR003=443.SD203-UN308

# IfcFlowTerminal: Ledelys bredstrålende LED utenpåliggende:-UN6102 (2)
In: Nivå D
Type - Material: magi2d_black, <Unnamed>
ePset_Simplebim - Assembly Level: Leaf
AVINOR - 08_Status: S4; 07_Fase: F90
ePset_LocationTool - Splitting: ORIGINAL
Name (Ledelys bredstrålende LED utenpåliggende:-UN6102:...) | 05_ID-nummer
14230975 | +BR003=443.SD203-UN117
14230976 | +BR003=443.SD203-UN220

# IfcFlowTerminal: M-lys fremover tak publikum 20m:-UN7310, M-lys fremover tak publikum 20m:-UN7310:4501853
In: Nivå D
Type - Material: 2dsblk, <Unnamed>
ePset_LocationTool - Splitting: ORIGINAL
ePset_Simplebim - Assembly Level: Leaf
AVINOR - 08_Status: S4; 07_Fase: F90; 05_ID-nummer: +BR003=443.SD203-UN401

# IfcFlowTerminal: PLUMBING FIXTURE - Ghost object -:ARMATUR - - UB512T, PLUMBING FIXTURE - Ghost object -:ARMATUR - - UB512T:19200130
In: Nivå D
Type - Material: <Unnamed>
ePset_Simplebim - Assembly Level: Leaf
AVINOR - 08_Status: S4; 07_Fase: F90; 05_ID-nummer: +BR003=310.TO100-UB512T
ePset_LocationTool - Splitting: ORIGINAL

# IfcFlowTerminal: PLUMBING FIXTURE - Ghost object -:ARMATUR - - UB513T, PLUMBING FIXTURE - Ghost object -:ARMATUR - - UB513T:19200148
In: Nivå D
Type - Material: <Unnamed>
ePset_Simplebim - Assembly Level: Leaf
ePset_LocationTool - Splitting: ORIGINAL
AVINOR - 08_Status: S4; 07_Fase: F90; 05_ID-nummer: +BR003=310.TO100-UB513T

# IfcFlowTerminal: PLUMBING FIXTURE - Ghost object -:ARMATUR - - UB514T, PLUMBING FIXTURE - Ghost object -:ARMATUR - - UB514T:19200165
In: Nivå D
Type - Material: <Unnamed>
AVINOR - 08_Status: S4; 07_Fase: F90; 05_ID-nummer: +BR003=310.TO100-UB514T
ePset_Simplebim - Assembly Level: Leaf
ePset_LocationTool - Splitting: ORIGINAL

# IfcFlowTerminal: PLUMBING FIXTURE - Ghost object -:VARMTVANNSBEREDER - - NW502T, PLUMBING FIXTURE - Ghost object -:VARMTVANNSBEREDER - - NW502T:19200091
In: Nivå D
Type - Material: <Unnamed>
ePset_Simplebim - Assembly Level: Leaf
ePset_LocationTool - Splitting: ORIGINAL
AVINOR - 08_Status: S4; 07_Fase: F90; 05_ID-nummer: +BR003=310.TO200-NW502T
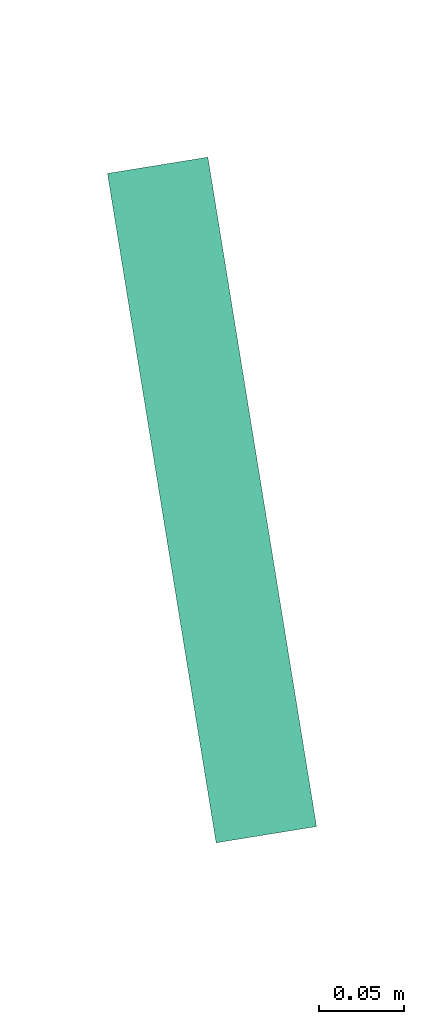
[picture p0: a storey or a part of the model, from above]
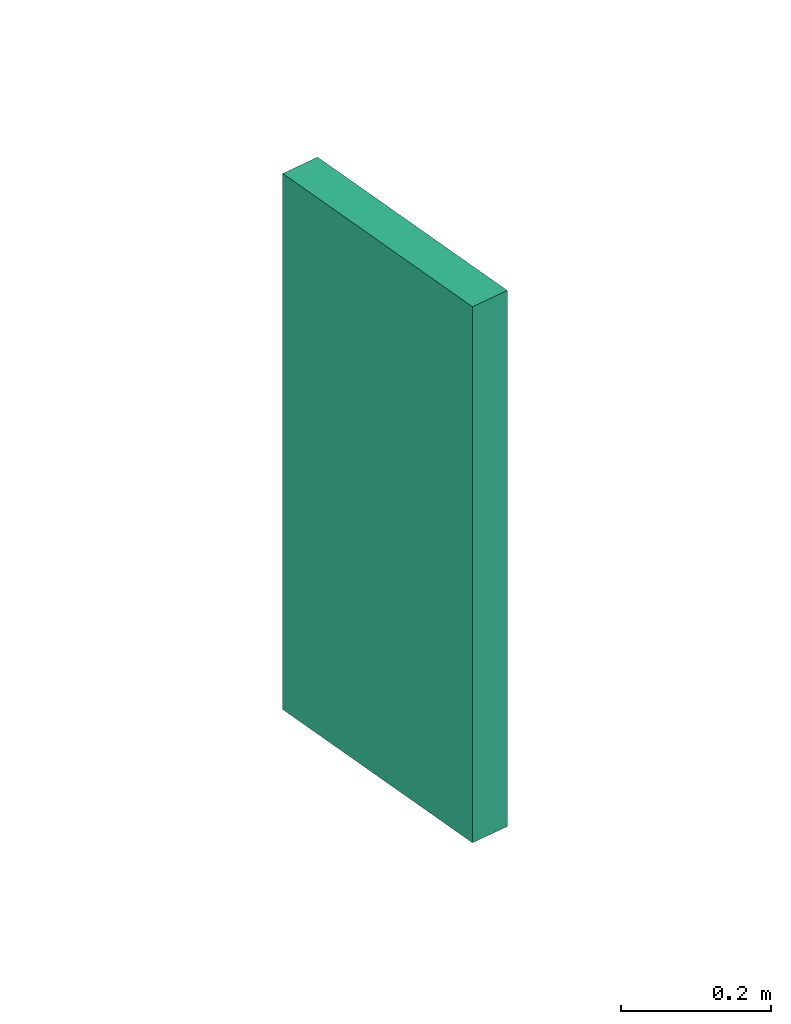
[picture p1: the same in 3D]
Properties of the parts of a building model (IFC2X3), part 3 of 3

# IfcFlowTerminal: SERVANTBATTERI - - IN:SERVANTBATTERI - - INKL.M.VASK, SERVANTBATTERI - - IN:SERVANTBATTERI - - INKL.M.VASK:10914620
In: Nivå D
Type - Material: <Unnamed>
ePset_Simplebim - Assembly Level: Leaf
ePset_LocationTool - Splitting: ORIGINAL
AVINOR - 05_ID-nummer: +BR003=310.TO100-INKL.M.VASK

# IfcFlowTerminal: SLUK - flis 2 - KN:SLUK - - KN506T, SLUK - flis 2 - KN:SLUK - - KN506T:19152087
In: Nivå D
Type - Material: <Unnamed>
ePset_Simplebim - Assembly Level: Leaf
ePset_LocationTool - Splitting: ORIGINAL
AVINOR - 08_Status: S4; 07_Fase: F90; 05_ID-nummer: +BR003=310.TO500-KN506T

# IfcFlowTerminal: Speilarmatur LED p-toalett:-UP1118 Dummy-LF L600, Speilarmatur LED p-toalett:-UP1118 Dummy-LF L600:3339015
In: Nivå D
Type - Material: <Unnamed>
ePset_LocationTool - Splitting: ORIGINAL
ePset_Simplebim - Assembly Level: Leaf
AVINOR - 08_Status: S4; 07_Fase: F90; 05_ID-nummer: +BR003=442.00001-UP1118T
Group: =433.SD121-KW28

# IfcFlowTerminal: TILLUFTSVENTIL - - ST003T:TILLUFTSVENTIL - EAGLE Cb 160-600-1V+ALSd 125-160 - ST003T, TILLUFTSVENTIL - - ST003T:TILLUFTSVENTIL - EAGLE Cb 160-600-1V+ALSd 125-160 - ST003T:7568002
In: Nivå D
Type - Material: <Unnamed>
ePset_Simplebim - Assembly Level: Leaf
ePset_LocationTool - Splitting: ORIGINAL
AVINOR - 05_ID-nummer: +BR003=360.TO001-ST003T; 08_Status: S4; 07_Fase: F90
Group: 360.SB113 T

# IfcFlowTerminal: TILLUFTSVENTIL - 1 - ST004T:TILLUFTSVENTIL - TELLUS-LOV-H-125 - ST004T, TILLUFTSVENTIL - 1 - ST004T:TILLUFTSVENTIL - TELLUS-LOV-H-125 - ST004T:13386488
In: Nivå D
Type - Material: <Unnamed>
ePset_Simplebim - Assembly Level: Leaf
ePset_LocationTool - Splitting: ORIGINAL
AVINOR - 08_Status: S4; 07_Fase: F90; 05_ID-nummer: +BR003=360.TO001-ST004T
Group: 360.SB113 T

# IfcFlowTerminal: TILLUFTSVENTIL - 1 - ST004T:TILLUFTSVENTIL - TELLUS-LOV-H-160 - ST004T, TILLUFTSVENTIL - 1 - ST004T:TILLUFTSVENTIL - TELLUS-LOV-H-160 - ST004T:22061097
In: Nivå D
Type - Material: <Unnamed>
ePset_LocationTool - Splitting: ORIGINAL
ePset_Simplebim - Assembly Level: Leaf
AVINOR - 08_Status: S4; 07_Fase: F90; 05_ID-nummer: +BR003=360.TO001-ST004T
Group: 360.SB113 T

# IfcFlowTerminal: TILLUFTSVENTIL - 1 - ST004T:TILLUFTSVENTIL - TELLUS-LOV-H-250 - ST004T (7)
In: Nivå D
Type - Material: <Unnamed>
ePset_Simplebim - Assembly Level: Leaf
AVINOR - 08_Status: S4; 07_Fase: F90; 05_ID-nummer: +BR003=360.TO001-ST004T
ePset_LocationTool - Splitting: ORIGINAL
Group: 360.SB113 T
Name (TILLUFTSVENTIL - 1 - ST004T:TILLUFTSVENTIL - TELLUS-LOV-H-250 - ST004T:...)
22059600
22059826
22059881
22059936
22059962
22060047
22060094

# IfcFlowTerminal: TILLUFTSVENTIL - 2 - ST072T:TILLUFTSVENTIL - NETTING-1000 - ST072T (3)
In: Nivå D
Type - Material: <Unnamed>
ePset_Simplebim - Assembly Level: Leaf
ePset_LocationTool - Splitting: ORIGINAL
AVINOR - 08_Status: S4; 07_Fase: F90; 05_ID-nummer: +BR003=360.TO001-ST072T
Name (TILLUFTSVENTIL - 2 - ST072T:TILLUFTSVENTIL - NETTING-1000 - ST072T:...) | Group
14282370 | 360.SB112 A
14282947 | 360.SB112 A
14282965 | 360.SB111 A

# IfcFlowTerminal: Teknisk tak utenpåliggende LED4000lm bredstrålende:-UP1113 Teknisk tak LED4000lm WB, Teknisk tak utenpåliggende LED4000lm bredstrålende:-UP1113 Teknisk tak LED4000lm WB:3223138
In: Nivå D
Type - Material: <Unnamed>
ePset_LocationTool - Splitting: ORIGINAL
ePset_Simplebim - Assembly Level: Leaf
AVINOR - 08_Status: S4; 07_Fase: F90; 05_ID-nummer: +BR003=442.00001-UP1113T
Group: =433.SD121-KW31

# IfcFlowTerminal: Tele Data gen uttak enkel:Data socket-1, Tele Data gen uttak enkel:Data socket-1:10954286
In: Nivå D
Type - Material: <Unnamed>
ePset_Simplebim - Assembly Level: Leaf
ePset_LocationTool - Splitting: ORIGINAL
AVINOR - 08_Status: S1; 07_Fase: F30

# IfcFlowTerminal: Tele-Data gen uttak dobbel Tak_U boks:Data_uttak_dobbel Tak_U boks (4)
In: Nivå D
Type - Material: <Unnamed>
ePset_Simplebim - Assembly Level: Leaf
ePset_LocationTool - Splitting: ORIGINAL
AVINOR - 08_Status: S1; 07_Fase: F30
Name (Tele-Data gen uttak dobbel Tak_U boks:Data_uttak_dobbel Tak_U boks:...)
7394731
7394831
8253846
9752896

# IfcFlowTerminal: Tele-Data gen uttak dobbel Tak_U boks:Data_uttak_dobbel Tak_U boks_for WiFi, Tele-Data gen uttak dobbel Tak_U boks:Data_uttak_dobbel Tak_U boks_for WiFi:8255363
In: Nivå D
Type - Material: <Unnamed>
ePset_Simplebim - Assembly Level: Leaf
ePset_LocationTool - Splitting: ORIGINAL
AVINOR - 08_Status: S1; 07_Fase: F30

# IfcFlowTerminal: Tele-Data gen uttak dobbel:Tele-Data gen. uttak dobbel (10)
In: Nivå D
Type - Material: <Unnamed>
ePset_Simplebim - Assembly Level: Leaf
ePset_LocationTool - Splitting: ORIGINAL
AVINOR - 08_Status: S1; 07_Fase: F30
Name (Tele-Data gen uttak dobbel:Tele-Data gen. uttak dobbel:...)
7268529
9744690
9745026
9752900
9752904
9752908
9822640
9822760
9822846
10392649

# IfcFlowTerminal: UTSLAGSVASK - 400x500 - NY:UTSLAGSVASK - - NY003T, UTSLAGSVASK - 400x500 - NY:UTSLAGSVASK - - NY003T:10914619
In: Nivå D
Type - Material: <Unnamed>
ePset_Simplebim - Assembly Level: Leaf
AVINOR - 08_Status: S4; 07_Fase: F90; 05_ID-nummer: +BR003=310.TO500-NY003T
ePset_LocationTool - Splitting: ORIGINAL

# IfcFlowTerminal: UZ002T:Dyse/Spreder - UZ002T (35)
Type - Material: <Unnamed>
ePset_Simplebim - Assembly Level: Leaf
ePset_LocationTool - Splitting: ORIGINAL
AVINOR - 08_Status: S4; 05_ID-nummer: +BR003=332.SB001-UZ002T; 07_Fase: F90
Name (UZ002T:Dyse/Spreder - UZ002T:...) | In | Group
9498207 | Nivå D | 332.SB001 (1) (2)
9498220 | Nivå D | 332.SB001 (1) (2)
10236406 | Nivå C
10237647 | Nivå C
10237654 | Nivå C
10237681 | Nivå C
10237756 | Nivå C
10239490 | Nivå C
10239506 | Nivå C
10239522 | Nivå C
10239538 | Nivå C
11007167 | Nivå D | 332.SB001 (1) (2)
19828717 | Nivå D | 332.SB001 (1) (2)
19828760 | Nivå D | 332.SB001 (1) (2)
19828782 | Nivå D | 332.SB001 (1) (2)
19829299 | Nivå D | 332.SB001 (1) (2)
19829323 | Nivå D | 332.SB001 (1) (2)
19829335 | Nivå D | 332.SB001 (1) (2)
19829618 | Nivå D | 332.SB001 (1) (2)
19830440 | Nivå D | 332.SB001 (1) (2)
19830493 | Nivå D | 332.SB001 (1) (2)
19830603 | Nivå D | 332.SB001 (1) (2)
19830613 | Nivå D | 332.SB001 (1) (2)
19830968 | Nivå D | 332.SB001 (1) (2)
19830971 | Nivå D | 332.SB001 (1) (2)
19831093 | Nivå D | 332.SB001 (1) (2)
19831096 | Nivå D | 332.SB001 (1) (2)
19831176 | Nivå D | 332.SB001 (1) (2)
19831233 | Nivå D | 332.SB001 (1) (2)
19831236 | Nivå D | 332.SB001 (1) (2)
19831296 | Nivå D | 332.SB001 (1) (2)
19831380 | Nivå D | 332.SB001 (1) (2)
19831602 | Nivå D | 332.SB001 (1) (2)
19831614 | Nivå D | 332.SB001 (1) (2)
20623192 | Nivå C

# IfcFlowTerminal: UZ003T:Dyse/Spreder - UZ003T (2)
In: Nivå D
Type - Material: <Unnamed>
AVINOR - 08_Status: S4; 07_Fase: F90; 05_ID-nummer: +BR003=332.SB001-UZ003T
ePset_Simplebim - Assembly Level: Leaf
ePset_LocationTool - Splitting: ORIGINAL
Group: 332.SB001 (1) (2)
Name (UZ003T:Dyse/Spreder - UZ003T:...)
9498206
9498219

# IfcFlowTerminal: UZ014T:Dyse/Spreder - UZ014T (2)
In: Nivå D
Type - Material: 2dsblk
AVINOR - 08_Status: S4; 07_Fase: F90; 05_ID-nummer: +BR003=332.PB001-UZ014T
ePset_Simplebim - Assembly Level: Leaf
ePset_LocationTool - Splitting: ORIGINAL
Group: 332.SB001 (1) (2)
Name (UZ014T:Dyse/Spreder - UZ014T:...)
19831487
19831566

# IfcFurnishingElement: A279 Røykgardin E30:A279 Røykgardin E30, A279 Røykgardin E30:A279 Røykgardin E30:26623484
In: Nivå D-H01
Type - Material: A290 - Laminat - Hvit
ePset_Simplebim - Assembly Level: Leaf
ePset_LocationTool - Splitting: ORIGINAL
AVINOR - 05_ID-nummer: +B3003=279.SD405

# IfcFurnishingElement: Branngardin Skinne:Branngardin Skinne (2)
In: Nivå D-H01
Type - Material: A290 - Laminat - Hvit
ePset_LocationTool - Splitting: ORIGINAL
ePset_Simplebim - Assembly Level: Leaf
Name (Branngardin Skinne:Branngardin Skinne:...)
28103675
28103734

# IfcMember: Rectangular Mullion:A246 - Fuge 5mm L01 (3)
In: Nivå D-H01
Type - PredefinedType: MULLION; Material: Rubber
Pset_MemberCommon - Reference: Rectangular Mullion:A246 - Fuge 5mm L01
ePset_Simplebim - Assembly Level: Leaf
ePset_SimplebimBasicQuantities - Height (Simplebim): 5 mm; Width (Simplebim): 20 mm
ePset_LocationTool - Splitting: ORIGINAL
Name (Rectangular Mullion:A246 - Fuge 5mm L01:...) | Area, sides, net (Simplebim) (m2) | Weight, as steel (Simplebim) (kg) | Volume, net (Simplebim) (m3) | Length (Simplebim) (mm)
39868117 | 0.015325 | 0.237463 | 0.00003025 | 302.5
39868151 | 0.0302 | 0.471 | 0.00006 | 600
39868152 | 0.004825 | 0.0726125 | 0.00000925 | 92.5

# IfcMember: Rectangular Mullion:A246 - Fuge 5mm L09 (101)
In: Nivå D-H01
Type - PredefinedType: MULLION; Material: Rubber
Pset_MemberCommon - Reference: Rectangular Mullion:A246 - Fuge 5mm L09
ePset_Simplebim - Assembly Level: Leaf
Name (Rectangular Mullion:A246 - Fuge 5mm L09:...) | Splitting | Weight, as steel (Simplebim) (kg) | Length (Simplebim) (mm) | Height (Simplebim) (mm) | Width (Simplebim) (mm) | Area, sides, net (Simplebim) (m2) | Volume, net (Simplebim) (m3)
13184355 | ORIGINAL | 0.467075 | 595 | 5 | 20 | 0.02995 | 0.0000595
13184367 | ORIGINAL | 0.467075 | 595 | 5 | 20 | 0.02995 | 0.0000595
13184368 | ORIGINAL | 0.467075 | 595 | 5 | 20 | 0.02995 | 0.0000595
13184369 | ORIGINAL | 0.467075 | 595 | 5 | 20 | 0.02995 | 0.0000595
13184370 | ORIGINAL | 0.467075 | 595 | 5 | 20 | 0.02995 | 0.0000595
13184371 | ORIGINAL | 0.467075 | 595 | 5 | 20 | 0.02995 | 0.0000595
13406760 | ORIGINAL | 0.469038 | 597.5 | 5 | 20 | 0.030075 | 0.00005975
16546372 | ORIGINAL | 0.471 | 600 | 5 | 20 | 0.0302 | 0.00006
16546469 | ORIGINAL | 0.471 | 600 | 5 | 20 | 0.0302 | 0.00006
30191381 | ORIGINAL | 0.231575 | 295 | 5 | 20 | 0.01495 | 0.0000295
34889933 | ORIGINAL | 0.467075 | 595 | 5 | 20 | 0.02995 | 0.0000595
34889970 | ORIGINAL | 0.467075 | 595 | 5 | 20 | 0.02995 | 0.0000595
34890003 | ORIGINAL | 0.467075 | 595 | 5 | 20 | 0.02995 | 0.0000595
34890034 | ORIGINAL | 0.471 | 600 | 5 | 20 | 0.0302 | 0.00006
34890063 | ORIGINAL | 0.233538 | 297.5 | 5 | 20 | 0.015075 | 0.00002975
39868062 | ORIGINAL | 0.233538 | 297.5 | 5 | 20 | 0.015075 | 0.00002975
39868064 | ORIGINAL | 0.2198 | 280 | 5 | 20 | 0.0142 | 0.000028
39868067 | ORIGINAL | 0.38465 | 490 | 5 | 20 | 0.0247 | 0.000049
39868087 | ORIGINAL | 0.467075 | 595 | 5 | 20 | 0.02995 | 0.0000595
39868107 | ORIGINAL | 0.231575 | 295 | 5 | 20 | 0.01495 | 0.0000295
39868168 | ORIGINAL | 0.231575 | 295 | 5 | 20 | 0.01495 | 0.0000295
39868169 | ORIGINAL | 0.2198 | 280 | 5 | 20 | 0.0142 | 0.000028
39868171 | ORIGINAL | 0.38465 | 490 | 5 | 20 | 0.0247 | 0.000049
39868176 | ORIGINAL | 0.467075 | 595 | 5 | 20 | 0.02995 | 0.0000595
39868183 | ORIGINAL | 0.231575 | 295 | 5 | 20 | 0.01495 | 0.0000295
39868197 | ORIGINAL | 0.233538 | 297.5 | 5 | 20 | 0.015075 | 0.00002975
39868198 | ORIGINAL | 0.2198 | 280 | 5 | 20 | 0.0142 | 0.000028
39868200 | ORIGINAL | 0.38465 | 490 | 5 | 20 | 0.0247 | 0.000049
39868205 | ORIGINAL | 0.467075 | 595 | 5 | 20 | 0.02995 | 0.0000595
39868212 | ORIGINAL | 0.231575 | 295 | 5 | 20 | 0.01495 | 0.0000295
39868234 | ORIGINAL | 0.241388 | 307.5 | 5 | 20 | 0.015575 | 0.00003075
39868235 | ORIGINAL | 0.467075 | 595 | 5 | 20 | 0.02995 | 0.0000595
39868236 | ORIGINAL | 0.467075 | 595 | 5 | 20 | 0.02995 | 0.0000595
39868237 | ORIGINAL | 0.467075 | 595 | 5 | 20 | 0.02995 | 0.0000595
39868238 | ORIGINAL | 0.467075 | 595 | 5 | 20 | 0.02995 | 0.0000595
39868239 | ORIGINAL | 0.467075 | 595 | 5 | 20 | 0.02995 | 0.0000595
39868240 | ORIGINAL | 0.467075 | 595 | 5 | 20 | 0.02995 | 0.0000595
39868250 | ORIGINAL | 0.467075 | 595 | 5 | 20 | 0.02995 | 0.0000595
39868251 | ORIGINAL | 0.467075 | 595 | 5 | 20 | 0.02995 | 0.0000595
39868252 | ORIGINAL | 0.467075 | 595 | 5 | 20 | 0.02995 | 0.0000595
39868271 | ORIGINAL | 0.233538 | 297.5 | 5 | 20 | 0.015075 | 0.00002975
39868273 | ORIGINAL | 0.225688 | 287.5 | 5 | 20 | 0.014575 | 0.00002875
39868275 | ORIGINAL | 0.233538 | 297.5 | 5 | 20 | 0.015075 | 0.00002975
39868276 | ORIGINAL | 0.390538 | 497.5 | 5 | 20 | 0.025075 | 0.00004975
39868296 | ORIGINAL | 0.467075 | 595 | 5 | 20 | 0.02995 | 0.0000595
39868297 | ORIGINAL | 0.467075 | 595 | 5 | 20 | 0.02995 | 0.0000595
39868298 | ORIGINAL | 0.0765375 | 97.5 | 5 | 20 | 0.005075 | 0.00000975
39868299 | ORIGINAL | 0.467075 | 595 | 5 | 20 | 0.02995 | 0.0000595
39868300 | ORIGINAL | 0.467075 | 595 | 5 | 20 | 0.02995 | 0.0000595
39868301 | ORIGINAL | 0.467075 | 595 | 5 | 20 | 0.02995 | 0.0000595
39868302 | ORIGINAL | 0.467075 | 595 | 5 | 20 | 0.02995 | 0.0000595
39868303 | ORIGINAL | 0.233538 | 297.5 | 5 | 20 | 0.015075 | 0.00002975
39868316 | ORIGINAL | 0.233538 | 297.5 | 5 | 20 | 0.015075 | 0.00002975
39868402 | ORIGINAL | 0.900788 | 20 | 1147.5 | 5 | 0.057575 | 0.00011475
39868404 | ORIGINAL | 0.900788 | 20 | 1147.5 | 5 | 0.057575 | 0.00011475
39868406 | ORIGINAL | 0.900788 | 20 | 1147.5 | 5 | 0.057575 | 0.00011475
39868408 | ORIGINAL | 0.900788 | 20 | 1147.5 | 5 | 0.057575 | 0.00011475
39868410 | ORIGINAL | 0.900788 | 20 | 1147.5 | 5 | 0.057575 | 0.00011475
39868412 | ORIGINAL | 0.900788 | 20 | 1147.5 | 5 | 0.057575 | 0.00011475
39868416 | ORIGINAL | 0.900788 | 20 | 1147.5 | 5 | 0.057575 | 0.00011475
39868422 | ORIGINAL | 0.896863 | 20 | 1142.5 | 5 | 0.057325 | 0.00011425
39868426 | ORIGINAL | 0.896863 | 20 | 1142.5 | 5 | 0.057325 | 0.00011425
39868497 | ORIGINAL | 0.590713 | 20 | 752.5 | 5 | 0.037825 | 0.00007525
39868498 | ORIGINAL | 0.157 | 200 | 5 | 20 | 0.0102 | 0.00002
39868499 | ORIGINAL | 0.898825 | 20 | 1145 | 5 | 0.05745 | 0.0001145
39868500 | ORIGINAL | 1.0205 | 20 | 1300 | 5 | 0.0652 | 0.00013
39868501 | ORIGINAL | 0.0785 | 20 | 100 | 5 | 0.0052 | 0.00001
39868502 | ORIGINAL | 0.160925 | 20 | 205 | 5 | 0.01045 | 0.0000205
39868557 | ORIGINAL | 0.900788 | 20 | 1147.5 | 5 | 0.057575 | 0.00011475
39868559 | ORIGINAL | 0.900788 | 20 | 1147.5 | 5 | 0.057575 | 0.00011475
39868561 | ORIGINAL | 0.900788 | 20 | 1147.5 | 5 | 0.057575 | 0.00011475
39868563 | ORIGINAL | 0.900788 | 20 | 1147.5 | 5 | 0.057575 | 0.00011475
39868565 | ORIGINAL | 0.900788 | 20 | 1147.5 | 5 | 0.057575 | 0.00011475
39868567 | ORIGINAL | 0.896863 | 20 | 1142.5 | 5 | 0.057325 | 0.00011425
39868569 | ORIGINAL | 0.896863 | 20 | 1142.5 | 5 | 0.057325 | 0.00011425
39868571 | ORIGINAL | 0.900788 | 20 | 1147.5 | 5 | 0.057575 | 0.00011475
39868610 | ORIGINAL | 0.590713 | 20 | 752.5 | 5 | 0.037825 | 0.00007525
39868611 | ORIGINAL | 0.157 | 200 | 5 | 20 | 0.0102 | 0.00002
39868612 | ORIGINAL | 0.898825 | 20 | 1145 | 5 | 0.05745 | 0.0001145
39868613 | ORIGINAL | 1.0205 | 20 | 1300 | 5 | 0.0652 | 0.00013
39868614 | ORIGINAL | 0.0785 | 20 | 100 | 5 | 0.0052 | 0.00001
39868615 | ORIGINAL | 0.160925 | 20 | 205 | 5 | 0.01045 | 0.0000205
39868503 | RESULT | 0.27475 | 20 | 350 | 4 | 0.0177 | 0.000035
39868403 | RESULT | 0.27475 | 20 | 350 | 4 | 0.0177 | 0.000035
39868405 | RESULT | 0.27475 | 20 | 350 | 4 | 0.0177 | 0.000035
39868558 | RESULT | 0.27475 | 20 | 350 | 4 | 0.0177 | 0.000035
39868560 | RESULT | 0.27475 | 20 | 350 | 4 | 0.0177 | 0.000035
39868616 | RESULT | 0.27475 | 20 | 350 | 4 | 0.0177 | 0.000035
39868407 | RESULT | 0.27475 | 20 | 350 | 4 | 0.0177 | 0.000035
39868409 | RESULT | 0.27475 | 20 | 350 | 4 | 0.0177 | 0.000035
39868411 | RESULT | 0.27475 | 20 | 350 | 4 | 0.0177 | 0.000035
39868413 | RESULT | 0.27475 | 20 | 350 | 4 | 0.0177 | 0.000035
39868420 | RESULT | 0.27475 | 20 | 350 | 4 | 0.0177 | 0.000035
39868562 | RESULT | 0.27475 | 20 | 350 | 4 | 0.0177 | 0.000035
39868564 | RESULT | 0.27475 | 20 | 350 | 4 | 0.0177 | 0.000035
39868566 | RESULT | 0.27475 | 20 | 350 | 4 | 0.0177 | 0.000035
39868424 | RESULT | 0.27475 | 20 | 350 | 4 | 0.0177 | 0.000035
39868428 | RESULT | 0.27475 | 20 | 350 | 4 | 0.0177 | 0.000035
39868568 | RESULT | 0.27475 | 20 | 350 | 4 | 0.0177 | 0.000035
39868570 | RESULT | 0.27475 | 20 | 350 | 4 | 0.0177 | 0.000035
39868572 | RESULT | 0.27475 | 20 | 350 | 4 | 0.0177 | 0.000035

# IfcMember: Rectangular Mullion:A248-M03 kantbeskyt. åpning 230 (2)
In: Nivå D-H01
Type - PredefinedType: MULLION; Material: A200 - Metall - Stål
Pset_MemberCommon - Reference: Rectangular Mullion:A248-M03 kantbeskyt. åpning 230
ePset_Simplebim - Assembly Level: Leaf
ePset_SimplebimBasicQuantities - Volume, net (Simplebim): 0.0001725 m3; Weight, as steel (Simplebim): 1.35413 kg; Width (Simplebim): 5 mm; Height (Simplebim): 150 mm; Length (Simplebim): 230 mm; Area, sides, net (Simplebim): 0.0728 m2
ePset_LocationTool - Splitting: ORIGINAL
Name (Rectangular Mullion:A248-M03 kantbeskyt. åpning 230:...)
26458456
30191392

# IfcMember: Rectangular Mullion:A248-M03 kantbeskyt. åpning 260 (10)
In: Nivå D-H01
Type - PredefinedType: MULLION; Material: A200 - Metall - Stål
ePset_Simplebim - Assembly Level: Leaf
ePset_LocationTool - Splitting: ORIGINAL
Pset_MemberCommon - Reference: Rectangular Mullion:A248-M03 kantbeskyt. åpning 260
ePset_SimplebimBasicQuantities - Width (Simplebim): 5 mm; Length (Simplebim): 260 mm
Name (Rectangular Mullion:A248-M03 kantbeskyt. åpning 260:...) | Weight, as steel (Simplebim) (kg) | Volume, net (Simplebim) (m3) | Height (Simplebim) (mm) | Area, sides, net (Simplebim) (m2)
26458452 | 1.0205 | 0.00013 | 100 | 0.0556
26458453 | 2.041 | 0.00026 | 200 | 0.1086
26458454 | 13.2665 | 0.00169 | 1300 | 0.6916
26458455 | 7.65375 | 0.000975 | 750 | 0.4001
28799189 | 2.11754 | 0.00026975 | 207.5 | 0.112575
30191376 | 7.65375 | 0.000975 | 750 | 0.4001
30191377 | 13.2665 | 0.00169 | 1300 | 0.6916
30191378 | 1.0205 | 0.00013 | 100 | 0.0556
30191379 | 2.11754 | 0.00026975 | 207.5 | 0.112575
30191380 | 2.041 | 0.00026 | 200 | 0.1086

# IfcMember: Rectangular Mullion:A248-M11 vinkelprofil 50 (3)
In: Nivå D-H01
Type - PredefinedType: MULLION; Material: A200 - Metall - Stål
Pset_MemberCommon - Reference: Rectangular Mullion:A248-M11 vinkelprofil 50
ePset_Simplebim - Assembly Level: Leaf
ePset_LocationTool - Splitting: ORIGINAL
ePset_SimplebimBasicQuantities - Height (Simplebim): 5 mm; Width (Simplebim): 50 mm
Name (Rectangular Mullion:A248-M11 vinkelprofil 50:...) | Volume, net (Simplebim) (m3) | Weight, as steel (Simplebim) (kg) | Length (Simplebim) (mm) | Area, sides, net (Simplebim) (m2)
34894014 | 0.00014875 | 1.16769 | 595 | 0.06595
34894030 | 0.0000225 | 0.176625 | 90 | 0.0104
34894035 | 0.000075 | 0.58875 | 300 | 0.0335

# IfcMember: Rectangular Mullion:A248-M11 vinkelprofil 80 høyre (5)
In: Nivå D-H01
Type - PredefinedType: MULLION; Material: A200 - Metall - Stål
ePset_SimplebimBasicQuantities - Width (Simplebim): 15 mm; Length (Simplebim): 80 mm
ePset_LocationTool - Splitting: ORIGINAL
Pset_MemberCommon - Reference: Rectangular Mullion:A248-M11 vinkelprofil 80 høyre
ePset_Simplebim - Assembly Level: Leaf
Name (Rectangular Mullion:A248-M11 vinkelprofil 80 høyre:...) | Height (Simplebim) (mm) | Volume, net (Simplebim) (m3) | Area, sides, net (Simplebim) (m2) | Weight, as steel (Simplebim) (kg)
34894039 | 207.5 | 0.000217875 | 0.041525 | 1.71032
34894044 | 100 | 0.000105 | 0.0211 | 0.82425
34894048 | 200 | 0.00021 | 0.0401 | 1.6485
39868400 | 752.5 | 0.000790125 | 0.145075 | 6.20248
39868401 | 1300 | 0.001365 | 0.2491 | 10.7152

# IfcMember: Rectangular Mullion:A248-M11 vinkelprofil 80 venstre (5)
In: Nivå D-H01
Type - PredefinedType: MULLION; Material: A200 - Metall - Stål
ePset_LocationTool - Splitting: ORIGINAL
ePset_Simplebim - Assembly Level: Leaf
Pset_MemberCommon - Reference: Rectangular Mullion:A248-M11 vinkelprofil 80 venstre
ePset_SimplebimBasicQuantities - Width (Simplebim): 15 mm; Length (Simplebim): 80 mm
Name (Rectangular Mullion:A248-M11 vinkelprofil 80 venstre:...) | Height (Simplebim) (mm) | Volume, net (Simplebim) (m3) | Area, sides, net (Simplebim) (m2) | Weight, as steel (Simplebim) (kg)
34894017 | 207.5 | 0.000217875 | 0.041525 | 1.71032
34894021 | 100 | 0.000105 | 0.0211 | 0.82425
34894026 | 200 | 0.00021 | 0.0401 | 1.6485
39868508 | 752.5 | 0.000790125 | 0.145075 | 6.20248
39868509 | 1300 | 0.001365 | 0.2491 | 10.7152

# IfcPlate: A249-S01 - Sokkel veggkledning:A249-S01 - Sokkel veggkledning (3)
In: Nivå D-H01
Type - PredefinedType: CURTAIN_PANEL; Material: A246 - M _veggkledning metall
ePset_Simplebim - Assembly Level: Leaf
Pset_PlateCommon - Reference: A249-S01 - Sokkel veggkledning:A249-S01 - Sokkel veggkledning
Name (A249-S01 - Sokkel veggkledning:A249-S01 - Sokkel veggkledning:...) | Splitting | Weight, as steel (Simplebim) (kg) | Volume, net (Simplebim) (m3) | Area, largest surface, net (Simplebim) (m2)
30191385 | ORIGINAL | 18.4681 | 0.00235263 | 0.117631
26458440 | ORIGINAL | 12.8524 | 0.00163725 | 0.0818625
18898944 | RESULT | 16.7892 | 0.00213875 | 0.106938

# IfcPlate: System Panel:A246-GL01 - Glasspanel opaque (RA), System Panel:A246-GL01 - Glasspanel opaque (RA):42233615
In: Nivå D-H01
Type - PredefinedType: CURTAIN_PANEL; Material: A246 - GL _veggkledning glass opalt hvit
ePset_LocationTool - Splitting: ORIGINAL
ePset_Simplebim - Assembly Level: Leaf
Pset_PlateCommon - Reference: System Panel:A246-GL01 - Glasspanel opaque (RA)
ePset_SimplebimBasicQuantities - Area, largest surface, net (Simplebim): 1.89 m2; Volume, net (Simplebim): 0.0189 m3; Weight, as steel (Simplebim): 148.365 kg

# IfcPlate: System Panel:A246-L06 - Laminatpanel toppfelt/skilting ved dør, System Panel:A246-L06 - Laminatpanel toppfelt/skilting ved dør:13165954
In: Nivå D-H01
Type - PredefinedType: CURTAIN_PANEL; Material: A246 - L _veggkledning laminat
Pset_PlateCommon - Reference: System Panel:A246-L06 - Laminatpanel toppfelt/skilting ved dør
ePset_Simplebim - Assembly Level: Leaf
ePset_LocationTool - Splitting: ORIGINAL
ePset_SimplebimBasicQuantities - Area, largest surface, net (Simplebim): 0.4975 m2; Weight, as steel (Simplebim): 78.1075 kg; Volume, net (Simplebim): 0.00995 m3

# IfcPlate: System Panel:A246-T01 - Trespiler (48)
In: Nivå D-H01
Type - PredefinedType: CURTAIN_PANEL; Material: A246 - T _veggkledning trespiler
ePset_Simplebim - Assembly Level: Leaf
Pset_PlateCommon - Reference: System Panel:A246-T01 - Trespiler
Name (System Panel:A246-T01 - Trespiler:...) | Splitting | Weight, as steel (Simplebim) (kg) | Area, largest surface, net (Simplebim) (m2) | Volume, net (Simplebim) (m3)
34889240 | ORIGINAL | 139.188 | 0.443275 | 0.017731
27161262 | ORIGINAL | 65.5004 | 0.2086 | 0.008344
30191386 | ORIGINAL | 114.626 | 0.36505 | 0.014602
35534962 | ORIGINAL | 69.0094 | 0.219775 | 0.008791
26458441 | ORIGINAL | 129.831 | 0.413475 | 0.016539
34889241 | ORIGINAL | 336.294 | 1.071 | 0.04284
27161263 | ORIGINAL | 158.256 | 0.504 | 0.02016
30191387 | ORIGINAL | 276.948 | 0.882 | 0.03528
35534963 | ORIGINAL | 166.734 | 0.531 | 0.02124
26458442 | ORIGINAL | 313.686 | 0.999 | 0.03996
34889245 | ORIGINAL | 212.986 | 0.6783 | 0.027132
27161266 | ORIGINAL | 212.986 | 0.6783 | 0.027132
34889691 | ORIGINAL | 212.986 | 0.6783 | 0.027132
34889766 | ORIGINAL | 212.986 | 0.6783 | 0.027132
35534967 | ORIGINAL | 212.986 | 0.6783 | 0.027132
11064238 | ORIGINAL | 212.986 | 0.6783 | 0.027132
11064241 | ORIGINAL | 212.986 | 0.6783 | 0.027132
34889997 | ORIGINAL | 212.986 | 0.6783 | 0.027132
11064244 | ORIGINAL | 212.986 | 0.6783 | 0.027132
11064247 | ORIGINAL | 212.986 | 0.6783 | 0.027132
34889964 | ORIGINAL | 212.986 | 0.6783 | 0.027132
11064250 | ORIGINAL | 212.986 | 0.6783 | 0.027132
11064253 | ORIGINAL | 212.986 | 0.6783 | 0.027132
34889928 | ORIGINAL | 212.986 | 0.6783 | 0.027132
13406747 | ORIGINAL | 212.986 | 0.6783 | 0.027132
16546364 | ORIGINAL | 212.986 | 0.6783 | 0.027132
34890030 | ORIGINAL | 212.986 | 0.6783 | 0.027132
16546461 | ORIGINAL | 212.986 | 0.6783 | 0.027132
34890055 | ORIGINAL | 212.986 | 0.6783 | 0.027132
39192342 | RESULT | 47.1922 | 0.150294 | 0.00601175
39192343 | RESULT | 64.9234 | 0.206762 | 0.0082705
39192345 | RESULT | 64.9234 | 0.206762 | 0.0082705
39192346 | RESULT | 64.9234 | 0.206762 | 0.0082705
39192348 | RESULT | 64.9234 | 0.206762 | 0.0082705
39192350 | RESULT | 64.9234 | 0.206762 | 0.0082705
39192351 | RESULT | 64.9234 | 0.206762 | 0.0082705
39192352 | RESULT | 64.9234 | 0.206762 | 0.0082705
39192353 | RESULT | 64.9234 | 0.206762 | 0.0082705
39192354 | RESULT | 64.9234 | 0.206762 | 0.0082705
39192355 | RESULT | 64.9234 | 0.206762 | 0.0082705
39192356 | RESULT | 64.9234 | 0.206762 | 0.0082705
39192357 | RESULT | 64.9234 | 0.206762 | 0.0082705
39192358 | RESULT | 64.9234 | 0.206762 | 0.0082705
39192359 | RESULT | 64.9234 | 0.206762 | 0.0082705
39192360 | RESULT | 64.9234 | 0.206762 | 0.0082705
39192361 | RESULT | 64.9234 | 0.206762 | 0.0082705
39192362 | RESULT | 64.9234 | 0.206762 | 0.0082705
39192363 | RESULT | 64.9234 | 0.206762 | 0.0082705

# IfcRailing: Railing:A287-S04 (3)
In: Nivå D-H01
Material: <Unnamed>
ePset_Simplebim - Assembly Level: Leaf
Pset_RailingCommon - Reference: Railing:A287-S04
ePset_SimplebimBasicQuantities - Height: 148 mm; Length: 680 mm; Width: 677.099 mm
ePset_LocationTool - Splitting: ORIGINAL
Name (Railing:A287-S04:...)
18896053
26643158
26643174

# IfcSlab: Floor:A252 - Hulldekke 200 mm, Floor:A252 - Hulldekke 200 mm:10276074
In: Himlingsplan Nivå E
Type - PredefinedType: FLOOR; Material: _NSW Betong 200 mm
ePset_SimplebimBasicQuantities - Area, sides, net (Simplebim): 13.5727 m2; Area, largest surface, net (Simplebim): 159.154 m2; Volume, net (Simplebim): 31.8308 m3; Thickness (Simplebim): 200 mm; Perimeter (Simplebim): 67863.6 mm; Area, top, net (Simplebim): 159.154 m2
ePset_Simplebim - Assembly Level: Leaf
Pset_SlabCommon - Reference: Floor:A252 - Hulldekke 200 mm
ePset_LocationTool - Splitting: RESULT

# IfcSlab: Floor:A252 - Hulldekke 400 mm, Floor:A252 - Hulldekke 400 mm:17072446
In: Nivå D-H01
Type - PredefinedType: FLOOR; Material: _NSW Betong 400 mm
ePset_LocationTool - Splitting: RESULT
ePset_SimplebimBasicQuantities - Area, top, net (Simplebim): 163.216 m2; Area, largest surface, net (Simplebim): 163.216 m2; Area, sides, net (Simplebim): 24.824 m2; Volume, net (Simplebim): 65.2866 m3; Thickness (Simplebim): 400 mm; Perimeter (Simplebim): 62060 mm
ePset_Simplebim - Assembly Level: Leaf
Pset_SlabCommon - Reference: Floor:A252 - Hulldekke 400 mm

# IfcSlab: Floor:A253 - Betong Påstop 150mm, Floor:A253 - Betong Påstop 150mm:17675853
In: Nivå D-H01
Type - PredefinedType: FLOOR; Material: _NSW Betong 150 mm
ePset_Simplebim - Assembly Level: Leaf
ePset_LocationTool - Splitting: RESULT
ePset_SimplebimBasicQuantities - Area, top, net (Simplebim): 164.137 m2; Area, largest surface, net (Simplebim): 164.137 m2; Volume, net (Simplebim): 24.6205 m3; Perimeter (Simplebim): 66523.9 mm; Thickness (Simplebim): 150 mm; Area, sides, net (Simplebim): 9.97858 m2
Pset_SlabCommon - Reference: Floor:A253 - Betong Påstop 150mm

# IfcSlab: Floor:A253 - Betong Påstop 50 mm, Floor:A253 - Betong Påstop 50 mm:40474868
In: Nivå D-H01
Type - PredefinedType: FLOOR; Material: _NSW Betong paastøp 50 mm
Pset_SlabCommon - Reference: Floor:A253 - Betong Påstop 50 mm
ePset_Simplebim - Assembly Level: Leaf
ePset_SimplebimBasicQuantities - Area, top, net (Simplebim): 137.648 m2; Volume, net (Simplebim): 6.8824 m3; Area, largest surface, net (Simplebim): 137.648 m2; Perimeter (Simplebim): 55127.6 mm; Area, sides, net (Simplebim): 2.75638 m2; Thickness (Simplebim): 50 mm
ePset_LocationTool - Splitting: ORIGINAL

# IfcSlab: Floor:A255-K01 Keramisk flis - Mørk 600x600mm, Floor:A255-K01 Keramisk flis - Mørk 600x600mm:36753619
In: Nivå D-H01
Type - PredefinedType: FLOOR; Material: A255 - K01 11 mm, A200 - Lim 9 mm, _NSW Generell Gulv (Floor) 50 mm
ePset_SimplebimBasicQuantities - Area, sides, net (Simplebim): 0.720312 m2; Perimeter (Simplebim): 10290.2 mm; Volume, net (Simplebim): 0.423885 m3; Area, largest surface, net (Simplebim): 6.0555 m2; Thickness (Simplebim): 70 mm; Area, top, net (Simplebim): 6.05561 m2
ePset_Simplebim - Assembly Level: Leaf
ePset_LocationTool - Splitting: ORIGINAL
Pset_SlabCommon - Reference: Floor:A255-K01 Keramisk flis - Mørk 600x600mm

# IfcSlab: Floor:A255-K02 Keramisk flis ansatte arealer, Floor:A255-K02 Keramisk flis ansatte arealer:19104468
In: Nivå D-H01
Type - PredefinedType: FLOOR; Material: 246-F01 5 mm, FLIS- ANSATT - Tiles 200 x 200 65 mm
ePset_Simplebim - Assembly Level: Leaf
Pset_SlabCommon - Reference: Floor:A255-K02 Keramisk flis ansatte arealer
ePset_LocationTool - Splitting: ORIGINAL
ePset_SimplebimBasicQuantities - Area, sides, net (Simplebim): 0.686322 m2; Perimeter (Simplebim): 9804.59 mm; Volume, net (Simplebim): 0.419575 m3; Area, top, net (Simplebim): 5.99394 m2; Area, largest surface, net (Simplebim): 5.99392 m2; Thickness (Simplebim): 70 mm

# IfcSlab: Floor:A255-K04 Keramisk flis - Mørk 900x450, Floor:A255-K04 Keramisk flis - Mørk 900x450:37167846
In: Nivå D-H01
Type - PredefinedType: FLOOR; Material: 255 - keramisk flis sort 450x900 11 mm, A200 - Lim 9 mm, _NSW Generell Gulv (Floor) 50 mm
ePset_Simplebim - Assembly Level: Leaf
Pset_SlabCommon - Reference: Floor:A255-K04 Keramisk flis - Mørk 900x450
ePset_LocationTool - Splitting: ORIGINAL
ePset_SimplebimBasicQuantities - Perimeter (Simplebim): 2339.95 mm; Area, top, net (Simplebim): 0.161602 m2; Volume, net (Simplebim): 0.011312 m3; Area, sides, net (Simplebim): 0.163796 m2; Area, largest surface, net (Simplebim): 0.1616 m2; Thickness (Simplebim): 70 mm

# IfcSlab: Floor:A255-KA avrettingsmasse 10mm, Floor:A255-KA avrettingsmasse 10mm:12442284
In: Nivå D-H01
Type - PredefinedType: FLOOR; Material: _NSW Generell Gulv (Floor) 10 mm
Pset_SlabCommon - Reference: Floor:A255-KA avrettingsmasse 10mm
ePset_LocationTool - Splitting: ORIGINAL
ePset_Simplebim - Assembly Level: Leaf
ePset_SimplebimBasicQuantities - Perimeter (Simplebim): 55178.1 mm; Area, top, net (Simplebim): 137.648 m2; Volume, net (Simplebim): 1.37648 m3; Area, largest surface, net (Simplebim): 137.648 m2; Thickness (Simplebim): 10 mm; Area, sides, net (Simplebim): 0.551781 m2

# IfcSlab: Floor:A255-KOM01, Floor:A255-KOM01:43243248
In: Nivå D-H01
Type - PredefinedType: FLOOR; Material: Rubber 2 mm, _NSW Generell Gulv (Floor) 68 mm
ePset_Simplebim - Assembly Level: Leaf
Pset_SlabCommon - Reference: Floor:A255-KOM01
ePset_SimplebimBasicQuantities - Area, top, net (Simplebim): 137.648 m2; Volume, net (Simplebim): 9.63536 m3; Area, largest surface, net (Simplebim): 137.648 m2; Perimeter (Simplebim): 55124 mm; Thickness (Simplebim): 70 mm; Area, sides, net (Simplebim): 3.85868 m2
ePset_LocationTool - Splitting: ORIGINAL

# IfcSlab: Floor:A255-ML06, Floor:A255-ML06:27471380:6
In: Nivå D-H01
Type - PredefinedType: FLOOR; Material: 255-ML06 2 mm
ePset_SimplebimBasicQuantities - Area, top, net (Simplebim): 10.6002 m2; Volume, net (Simplebim): 0.0212004 m3; Perimeter (Simplebim): 13285.7 mm; Area, largest surface, net (Simplebim): 10.6002 m2; Area, sides, net (Simplebim): 0.0265715 m2; Thickness (Simplebim): 2 mm
ePset_Simplebim - Assembly Level: Leaf
ePset_LocationTool - Splitting: ORIGINAL
Pset_SlabCommon - Reference: Floor:A255-ML06

# IfcSlab: SurveyMarker rektangulær:Custom (3)
In: Nivå D
Type - PredefinedType: BASESLAB; Material: Black
ePset_Simplebim - Assembly Level: Leaf
ePset_SimplebimBasicQuantities - Thickness (Simplebim): 0.8 mm; Volume, net (Simplebim): 0.00000153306 m3
ePset_LocationTool - Splitting: ORIGINAL
Pset_SlabCommon - Reference: SurveyMarker rektangulær:Custom
Name (SurveyMarker rektangulær:Custom:...) | Area, sides, net (Simplebim) (m2) | Perimeter (Simplebim) (mm) | Area, largest surface, net (Simplebim) (m2) | Area, top, net (Simplebim) (m2)
14740786 | 0.000198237 | 247.797 | 0.000958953 | 0.00191714
14741162 | 0.000198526 | 248.158 | 0.00095841 | 0.001917
14741201 | 0.000200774 | 250.968 | 0.000958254 | 0.00191587

# IfcSlab: SurveyMarker:Custom (25)
In: Nivå D
Type - PredefinedType: BASESLAB; Material: Black
ePset_LocationTool - Splitting: ORIGINAL
ePset_Simplebim - Assembly Level: Leaf
Pset_SlabCommon - Reference: SurveyMarker:Custom
ePset_SimplebimBasicQuantities - Thickness (Simplebim): 0.8 mm; Volume, net (Simplebim): 0.00000153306 m3
Name (SurveyMarker:Custom:...) | Area, sides, net (Simplebim) (m2) | Perimeter (Simplebim) (mm) | Area, largest surface, net (Simplebim) (m2) | Area, top, net (Simplebim) (m2)
14740739 | 0.000201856 | 252.321 | 0.000958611 | 0.00191533
14740871 | 0.000201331 | 251.664 | 0.000958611 | 0.00191559
14740884 | 0.000198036 | 247.545 | 0.000958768 | 0.00191724
14740900 | 0.000201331 | 251.664 | 0.000958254 | 0.00191559
14740914 | 0.000202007 | 252.509 | 0.000957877 | 0.00191526
14740936 | 0.000202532 | 253.165 | 0.00095841 | 0.00191499
14740978 | 0.000202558 | 253.197 | 0.000958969 | 0.00191498
14740997 | 0.000198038 | 247.548 | 0.00095841 | 0.00191724
14768915 | 0.000200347 | 250.433 | 0.000959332 | 0.00191609
14768918 | 0.000198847 | 248.558 | 0.000959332 | 0.00191684
14768921 | 0.000197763 | 247.203 | 0.000959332 | 0.00191738
14768924 | 0.000198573 | 248.217 | 0.000959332 | 0.00191697
14769821 | 0.000202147 | 252.684 | 0.000958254 | 0.00191519
14769847 | 0.000201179 | 251.473 | 0.000958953 | 0.00191567
14769874 | 0.000198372 | 247.965 | 0.000958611 | 0.00191707
15621737 | 0.000198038 | 247.548 | 0.00095841 | 0.00191724
16242263 | 0.000197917 | 247.396 | 0.000958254 | 0.0019173
16242318 | 0.000197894 | 247.367 | 0.000958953 | 0.00191731
16242348 | 0.00020153 | 251.913 | 0.000958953 | 0.00191549
16242375 | 0.000199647 | 249.559 | 0.00095841 | 0.00191644
16242415 | 0.000198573 | 248.217 | 0.000958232 | 0.00191697
16242458 | 0.000202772 | 253.466 | 0.00095857 | 0.00191487
16242490 | 0.00019919 | 248.988 | 0.000958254 | 0.00191666
16242531 | 0.000198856 | 248.571 | 0.000958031 | 0.00191683
16242560 | 0.000198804 | 248.505 | 0.000958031 | 0.00191686

# IfcWall: Basic Wall:A242 - Betongblokk - 190 mm massiv/utstøpt (6)
In: Nivå B
Type - PredefinedType: STANDARD; Material: A200 - Betong 190 mm
ePset_Simplebim - Assembly Level: Leaf
Pset_WallCommon - Reference: Basic Wall:A242 - Betongblokk - 190 mm massiv/utstøpt
ePset_LocationTool - Splitting: RESULT
ePset_SimplebimBasicQuantities - Thickness (Simplebim): 190 mm; Height (Simplebim): 380 mm
Name (Basic Wall:A242 - Betongblokk - 190 mm massiv/utstøpt:...) | Area, side, net, smaller (Simplebim) (m2) = Area, side, gross, smaller (Simplebim) (m2) | Area, side, gross, AABB (Simplebim) (m2) | Area, side, gross, larger (Simplebim) (m2) = Area, largest surface, net (Simplebim) (m2) = Area, side, net, larger (Simplebim) (m2) | Volume, net (Simplebim) (m3) | Length (Simplebim) (mm) | Area, side, net, average (Simplebim) (m2) = Area, side, gross, average (Simplebim) (m2)
6247567 | 1.85869 | 1.93078 | 1.93089 | 0.360011 | 5081 | 1.89479
8734502 | 0.623385 | 0.7676 | 0.767785 | 0.132161 | 2020 | 0.695585
5263560 | 5.2364 | 5.3086 | 5.3086 | 1.00177 | 13970 | 5.2725
5907481 | 0.8702 | 0.8702 | 0.8702 | 0.165338 | 2290 | 0.8702
6688136 | 0.798 | 0.798 | 0.798 | 0.15162 | 2100 | 0.798
8695811 | 0.798 | 0.798 | 0.798 | 0.15162 | 2100 | 0.798

# IfcWall: Basic Wall:A242 - GG100/100GG (5)
Type - PredefinedType: STANDARD; Material: A240 - Gipsplate 12.5 mm, A240 - Gipsplate 12.5 mm, A200 - Isolasjon - Rock Wool 100 mm, A240 - Gipsplate 12.5 mm, A240 - Gipsplate 12.5 mm
ePset_Simplebim - Assembly Level: Leaf
Pset_WallCommon - Reference: Basic Wall:A242 - GG100/100GG
Name (Basic Wall:A242 - GG100/100GG:...) | In | Volume, net (Simplebim) (m3) | Area, side, gross, AABB (Simplebim) (m2) | Area, side, gross, smaller (Simplebim) (m2) = Area, side, net, smaller (Simplebim) (m2) | Area, side, net, larger (Simplebim) (m2) = Area, side, gross, larger (Simplebim) (m2) | Area, side, gross, average (Simplebim) (m2) = Area, side, net, average (Simplebim) (m2) | Area, largest surface, net (Simplebim) (m2) | Thickness (Simplebim) (mm) | Length (Simplebim) (mm) | Height (Simplebim) (mm) | Splitting
25713377 | Nivå D-H01 | 0.102022 | 0.736 | 0.69819 | 0.69819 | 0.69819 | 0.69819 | 150 | 200 | 3680 | ORIGINAL
28816814 | Nivå D-H01 | 1.76538 |  |  |  |  | 11.7894 |  |  |  | ORIGINAL
16534522 | Himlingsplan Nivå E | 0.0590625 | 0.39375 | 0.39375 | 0.39375 | 0.39375 | 0.39375 | 150 | 1125 | 350 | RESULT
16534523 | Himlingsplan Nivå E | 0.0484602 | 0.32604 | 0.32498 | 0.325987 | 0.325483 | 0.325987 | 150 | 836 | 390 | RESULT
24716550 | Himlingsplan Nivå E | 0.256669 | 1.71132 | 1.71113 | 1.71113 | 1.71113 | 1.71113 | 150 | 4388 | 390 | RESULT

# IfcWall: Basic Wall:A242 - GG120/100GG (2)
In: Nivå D-H01
Type - PredefinedType: STANDARD; Material: A240 - Gipsplate 12.5 mm, A240 - Gipsplate 12.5 mm, A200 - Isolasjon - Rock Wool 120 mm, A240 - Gipsplate 12.5 mm, A240 - Gipsplate 12.5 mm
ePset_Simplebim - Assembly Level: Leaf
ePset_SimplebimBasicQuantities - Thickness (Simplebim): 170 mm; Height (Simplebim): 3920 mm
Pset_WallCommon - Reference: Basic Wall:A242 - GG120/100GG
Name (Basic Wall:A242 - GG120/100GG:...) | Volume, net (Simplebim) (m3) | Area, side, gross, smaller (Simplebim) (m2) = Area, side, gross, average (Simplebim) (m2) = Area, side, gross, larger (Simplebim) (m2) | Area, side, net, larger (Simplebim) (m2) = Area, side, net, average (Simplebim) (m2) = Area, side, net, smaller (Simplebim) (m2) = Area, largest surface, net (Simplebim) (m2) | Area, side, gross, AABB (Simplebim) (m2) | Length (Simplebim) (mm) | Splitting
28956523 | 0.253096 | 1.4888 | 1.4888 | 1.5092 | 385 | ORIGINAL
35827299 | 1.30492 | 9.898 | 7.676 | 9.898 | 2525 | RESULT

# IfcWall: Basic Wall:A242 - GG160/100GG, Basic Wall:A242 - GG160/100GG:8700756
In: Nivå D-H01
Type - PredefinedType: STANDARD; Material: A240 - Gipsplate 12.5 mm, A240 - Gipsplate 12.5 mm, A200 - Isolasjon - Rock Wool 160 mm, A240 - Gipsplate 12.5 mm, A240 - Gipsplate 12.5 mm
Pset_WallCommon - Reference: Basic Wall:A242 - GG160/100GG
ePset_Simplebim - Assembly Level: Leaf
ePset_LocationTool - Splitting: ORIGINAL
ePset_SimplebimBasicQuantities - Area, side, gross, smaller (Simplebim): 8.59637 m2; Area, side, net, smaller (Simplebim): 6.37437 m2; Area, side, gross, larger (Simplebim): 8.70403 m2; Area, side, gross, average (Simplebim): 8.6502 m2; Area, side, net, average (Simplebim): 6.4282 m2; Volume, net (Simplebim): 1.3409 m3; Thickness (Simplebim): 210 mm; Length (Simplebim): 2420 mm; Height (Simplebim): 3630 mm; Area, side, gross, AABB (Simplebim): 8.7846 m2; Area, side, net, larger (Simplebim): 6.48203 m2; Area, largest surface, net (Simplebim): 6.48203 m2

# IfcWall: Basic Wall:A242 - GGG100/0 (9)
Type - PredefinedType: STANDARD; Material: A240 - Gipsplate 12.5 mm, A240 - Gipsplate 12.5 mm, A240 - Gipsplate 12.5 mm, A240 - Stenderverk - Usiolert 100 mm
Pset_WallCommon - Reference: Basic Wall:A242 - GGG100/0
ePset_Simplebim - Assembly Level: Leaf
Name (Basic Wall:A242 - GGG100/0:...) | In | Area, side, gross, smaller (Simplebim) (m2) | Volume, net (Simplebim) (m3) | Area, side, net, larger (Simplebim) (m2) | Area, largest surface, net (Simplebim) (m2) | Thickness (Simplebim) (mm) | Height (Simplebim) (mm) | Length (Simplebim) (mm) | Area, side, gross, average (Simplebim) (m2) | Area, side, net, smaller (Simplebim) (m2) | Area, side, gross, AABB (Simplebim) (m2) | Area, side, gross, larger (Simplebim) (m2) | Area, side, net, average (Simplebim) (m2) | Splitting
8699486 | Nivå D-H01 | 14.2758 | 1.65564 | 12.0647 | 12.0647 | 137.5 | 3680 | 3885 | 14.2863 | 12.0437 | 14.2968 | 14.2968 | 12.0542 | ORIGINAL
8699885 | Nivå D-H01 | 8.11076 | 1.11398 | 8.12074 | 8.12074 | 137.5 | 3460 | 2347.5 | 8.11575 | 8.11076 | 8.12235 | 8.12074 | 8.11575 | ORIGINAL
8699940 | Nivå D-H01 | 15.1059 | 2.08152 | 15.1491 | 15.1491 | 137.5 | 3680 | 4181.25 | 15.1275 | 15.1059 | 15.387 | 15.1491 | 15.1275 | ORIGINAL
24716551 | Himlingsplan Nivå E | 0.939217 | 0.129023 | 0.941005 | 0.941005 | 138 | 403 | 2335 | 0.940111 | 0.939217 | 0.941005 | 0.941005 | 0.940111 | RESULT
24716552 | Himlingsplan Nivå E | 1.02375 | 0.140766 | 1.02375 | 1.02375 | 138 | 390 | 2625 | 1.02375 | 1.02375 | 1.02375 | 1.02375 | 1.02375 | RESULT
37352730 | Himlingsplan Nivå E | 1.18528 | 0.162975 | 1.18528 | 1.18528 | 138 | 350 | 3387 | 1.18528 | 1.18528 | 1.18545 | 1.18528 | 1.18528 | RESULT
37353051 | Himlingsplan Nivå E | 2.76629 | 0.164614 | 1.19719 | 0.99225 | 138 | 350 | 4131 | 2.76629 | 1.19719 | 1.44585 | 2.76629 | 1.19719 | RESULT
39293615 | Himlingsplan Nivå E | 0.14175 | 0.0194906 | 0.14175 | 0.14175 | 138 | 350 | 405 | 0.14175 | 0.14175 | 0.14175 | 0.14175 | 0.14175 | RESULT
39293785 | Himlingsplan Nivå E | 0.212291 | 0.02919 | 0.212291 | 0.212291 | 138 | 350 | 607 | 0.212291 | 0.212291 | 0.21245 | 0.212291 | 0.212291 | RESULT

# IfcWallStandardCase: Basic Wall:3mm RF-stål (2)
In: Nivå D-H01
Type - PredefinedType: STANDARD; Material: A200 - Metall - Stål 3 mm
ePset_LocationTool - Splitting: ORIGINAL
Pset_WallCommon - Reference: Basic Wall:3mm RF-stål
ePset_SimplebimBasicQuantities - Thickness (Simplebim): 3 mm; Length (Simplebim): 160 mm; Height (Simplebim): 250 mm; Volume, net (Simplebim): 0.00012 m3; Area, side, net, larger (Simplebim): 0.04 m2; Area, side, gross, smaller (Simplebim): 0.04 m2; Area, largest surface, net (Simplebim): 0.04 m2; Area, side, net, smaller (Simplebim): 0.04 m2; Area, side, gross, larger (Simplebim): 0.04 m2; Area, side, net, average (Simplebim): 0.04 m2; Area, side, gross, average (Simplebim): 0.04 m2; Area, side, gross, AABB (Simplebim): 0.04 m2
ePset_Simplebim - Assembly Level: Leaf
Name (Basic Wall:3mm RF-stål:...)
41642562
41642570

# IfcWallStandardCase: Basic Wall:A242 - G75/75G (3)
In: Nivå D-H01
Type - PredefinedType: STANDARD; Material: A240 - Gipsplate 12.5 mm, A200 - Isolasjon - Rock Wool 75 mm, A240 - Gipsplate 12.5 mm
ePset_Simplebim - Assembly Level: Leaf
Pset_WallCommon - Reference: Basic Wall:A242 - G75/75G
ePset_SimplebimBasicQuantities - Thickness (Simplebim): 100 mm
ePset_LocationTool - Splitting: ORIGINAL
Name (Basic Wall:A242 - G75/75G:...) | Area, side, gross, average (Simplebim) (m2) = Area, side, gross, larger (Simplebim) (m2) = Area, side, gross, smaller (Simplebim) (m2) = Area, side, gross, AABB (Simplebim) (m2) | Length (Simplebim) (mm) | Volume, net (Simplebim) (m3) | Height (Simplebim) (mm) | Area, side, net, larger (Simplebim) (m2) = Area, side, net, average (Simplebim) (m2) = Area, side, net, smaller (Simplebim) (m2) = Area, largest surface, net (Simplebim) (m2) | 08_Status | 03_Ansvar | 07_Fase | 02_Prosjekt | 05_ID-nummer | 01_Lufthavnkode
40483837 | 19.3225 | 5352.5 | 1.73114 | 3610 | 17.3114
45087917 | 4.77 | 4770 | 0.477 | 1000 | 4.77 | S4 | 188110 | F50 | 10003898 | +BR003=242.0064 | ENBR
45087996 | 2.136 | 2136 | 0.2136 | 1000 | 2.136 | S4 | 188110 | F50 | 10003898 | +BR003=242.0064 | ENBR

# IfcWallStandardCase: Basic Wall:A242 - GG100/0 (3)
In: Nivå D-H01
Type - PredefinedType: STANDARD; Material: A240 - Gipsplate 12.5 mm, A240 - Gipsplate 12.5 mm, A240 - Stenderverk - Usiolert 100 mm
ePset_LocationTool - Splitting: ORIGINAL
ePset_Simplebim - Assembly Level: Leaf
ePset_SimplebimBasicQuantities - Thickness (Simplebim): 125 mm; Height (Simplebim): 3680 mm
Pset_WallCommon - Reference: Basic Wall:A242 - GG100/0
Name (Basic Wall:A242 - GG100/0:...) | Length (Simplebim) (mm) | Volume, net (Simplebim) (m3) | Area, side, net, smaller (Simplebim) (m2) = Area, side, gross, larger (Simplebim) (m2) = Area, side, net, average (Simplebim) (m2) = Area, side, gross, average (Simplebim) (m2) = Area, largest surface, net (Simplebim) (m2) = Area, side, net, larger (Simplebim) (m2) = Area, side, gross, smaller (Simplebim) (m2) = Area, side, gross, AABB (Simplebim) (m2)
24249450 | 130 | 0.0598 | 0.4784
25050400 | 187.053 | 0.0860444 | 0.688355
25050401 | 187.053 | 0.0860444 | 0.688355

# IfcWallStandardCase: Basic Wall:A242 - GG100/100GG (3)
In: Nivå D-H01
Type - PredefinedType: STANDARD; Material: A240 - Gipsplate 12.5 mm, A240 - Gipsplate 12.5 mm, A200 - Isolasjon - Rock Wool 100 mm, A240 - Gipsplate 12.5 mm, A240 - Gipsplate 12.5 mm
ePset_SimplebimBasicQuantities - Thickness (Simplebim): 150 mm
ePset_Simplebim - Assembly Level: Leaf
ePset_LocationTool - Splitting: ORIGINAL
Pset_WallCommon - Reference: Basic Wall:A242 - GG100/100GG
Name (Basic Wall:A242 - GG100/100GG:...) | Area, side, gross, AABB (Simplebim) (m2) | Area, side, net, average (Simplebim) (m2) = Area, side, net, smaller (Simplebim) (m2) = Area, largest surface, net (Simplebim) (m2) = Area, side, net, larger (Simplebim) (m2) | Area, side, gross, average (Simplebim) (m2) = Area, side, gross, larger (Simplebim) (m2) = Area, side, gross, smaller (Simplebim) (m2) | Length (Simplebim) (mm) | Height (Simplebim) (mm) | Volume, net (Simplebim) (m3)
8700069 | 10.0188 | 10.0188 | 10.0188 | 2722.5 | 3680 | 1.50282
18826179 | 8.7952 | 8.7952 | 8.7952 | 2390 | 3680 | 1.31928
19585628 | 10.0914 | 7.8694 | 12.3134 | 2780 | 3630 | 1.18041

# IfcWallStandardCase: Basic Wall:A242 - GG120/100GG (7)
In: Nivå D-H01
Type - PredefinedType: STANDARD; Material: A240 - Gipsplate 12.5 mm, A240 - Gipsplate 12.5 mm, A200 - Isolasjon - Rock Wool 120 mm, A240 - Gipsplate 12.5 mm, A240 - Gipsplate 12.5 mm
ePset_Simplebim - Assembly Level: Leaf
ePset_SimplebimBasicQuantities - Thickness (Simplebim): 170 mm
Pset_WallCommon - Reference: Basic Wall:A242 - GG120/100GG
ePset_LocationTool - Splitting: ORIGINAL
Name (Basic Wall:A242 - GG120/100GG:...) | Volume, net (Simplebim) (m3) | Area, side, net, smaller (Simplebim) (m2) = Area, side, net, average (Simplebim) (m2) = Area, largest surface, net (Simplebim) (m2) = Area, side, net, larger (Simplebim) (m2) | Area, side, gross, AABB (Simplebim) (m2) | Length (Simplebim) (mm) | Height (Simplebim) (mm) | Area, side, gross, larger (Simplebim) (m2) = Area, side, gross, average (Simplebim) (m2) = Area, side, gross, smaller (Simplebim) (m2)
6308724 | 1.18854 | 7.644 | 7.644 | 1950 | 3920 | 8.3836
6318026 | 1.44403 | 9.683 | 9.683 | 8420 | 1150 | 9.683
13178472 | 1.23361 | 7.2565 | 7.2565 | 6310 | 1150 | 7.2565
19585626 | 1.64268 | 9.6628 | 9.6628 | 2465 | 3920 | 9.6628
24751117 | 10.1204 | 59.5318 | 59.5318 | 14920 | 3990.07 | 59.5318
28956522 | 2.21622 | 13.0366 | 17.4787 | 6310 | 2770 | 17.4787
34890490 | 0.357918 | 2.1054 | 2.1054 | 537.091 | 3920 | 2.1054

# IfcWallStandardCase: Basic Wall:A242 - GG160/100GG (2)
In: Nivå D-H01
Type - PredefinedType: STANDARD; Material: A240 - Gipsplate 12.5 mm, A240 - Gipsplate 12.5 mm, A200 - Isolasjon - Rock Wool 160 mm, A240 - Gipsplate 12.5 mm, A240 - Gipsplate 12.5 mm
ePset_LocationTool - Splitting: ORIGINAL
Pset_WallCommon - Reference: Basic Wall:A242 - GG160/100GG
ePset_Simplebim - Assembly Level: Leaf
ePset_SimplebimBasicQuantities - Thickness (Simplebim): 210 mm
Name (Basic Wall:A242 - GG160/100GG:...) | Area, side, gross, AABB (Simplebim) (m2) = Area, largest surface, net (Simplebim) (m2) = Area, side, net, average (Simplebim) (m2) = Area, side, gross, average (Simplebim) (m2) = Area, side, net, smaller (Simplebim) (m2) = Area, side, gross, larger (Simplebim) (m2) = Area, side, net, larger (Simplebim) (m2) = Area, side, gross, smaller (Simplebim) (m2) | Length (Simplebim) (mm) | Height (Simplebim) (mm) | Volume, net (Simplebim) (m3)
5350630 | 8.48565 | 2452.5 | 3460 | 1.78199
19585627 | 9.6784 | 2630 | 3680 | 2.03246

# IfcWallStandardCase: Basic Wall:A242 - GGG100/0, Basic Wall:A242 - GGG100/0:5348455
In: Nivå D-H01
Type - PredefinedType: STANDARD; Material: A240 - Gipsplate 12.5 mm, A240 - Gipsplate 12.5 mm, A240 - Gipsplate 12.5 mm, A240 - Stenderverk - Usiolert 100 mm
ePset_LocationTool - Splitting: ORIGINAL
Pset_WallCommon - Reference: Basic Wall:A242 - GGG100/0
ePset_Simplebim - Assembly Level: Leaf
ePset_SimplebimBasicQuantities - Volume, net (Simplebim): 1.44843 m3; Length (Simplebim): 2862.5 mm; Area, side, gross, AABB (Simplebim): 10.534 m2; Area, side, gross, average (Simplebim): 10.534 m2; Area, side, net, average (Simplebim): 10.534 m2; Area, side, gross, larger (Simplebim): 10.534 m2; Area, side, net, smaller (Simplebim): 10.534 m2; Area, largest surface, net (Simplebim): 10.534 m2; Area, side, gross, smaller (Simplebim): 10.534 m2; Area, side, net, larger (Simplebim): 10.534 m2; Thickness (Simplebim): 137.5 mm; Height (Simplebim): 3680 mm

# IfcWallStandardCase: Basic Wall:A246 - F02 - 900 x 300 (13)
In: Nivå D-H01
Type - PredefinedType: STANDARD; Material: 246-F02 10 mm
ePset_Simplebim - Assembly Level: Leaf
ePset_SimplebimBasicQuantities - Thickness (Simplebim): 10 mm
ePset_LocationTool - Splitting: ORIGINAL
Pset_WallCommon - Reference: Basic Wall:A246 - F02 - 900 x 300
Name (Basic Wall:A246 - F02 - 900 x 300:...) | Volume, net (Simplebim) (m3) | Area, side, gross, AABB (Simplebim) (m2) | Area, side, gross, smaller (Simplebim) (m2) = Area, side, gross, larger (Simplebim) (m2) = Area, side, gross, average (Simplebim) (m2) | Area, side, net, larger (Simplebim) (m2) = Area, side, net, smaller (Simplebim) (m2) = Area, side, net, average (Simplebim) (m2) = Area, largest surface, net (Simplebim) (m2) | Length (Simplebim) (mm) | Height (Simplebim) (mm)
25871670 | 0.02484 | 2.484 | 2.484 | 2.484 | 920 | 2700
25871671 | 0.00505043 | 0.505043 | 0.505043 | 0.505043 | 187.053 | 2700
25871672 | 0.01053 | 1.053 | 1.053 | 1.053 | 390 | 2700
25871673 | 0.00505043 | 0.505043 | 0.505043 | 0.505043 | 187.053 | 2700
25871674 | 0.02754 | 2.754 | 2.754 | 2.754 | 1020 | 2700
25871675 | 0.07074 | 7.074 | 7.074 | 7.074 | 2620 | 2700
25871676 | 0.06264 | 6.264 | 6.264 | 6.264 | 2320 | 2700
25871677 | 0.04825 | 7.047 | 7.047 | 4.825 | 2610 | 2700
26761438 | 0.066363 | 11.0803 | 11.0803 | 6.6363 | 3957.25 | 2800
26761655 | 0.01586 | 1.586 | 1.586 | 1.586 | 610 | 2600
26761749 | 0.04719 | 4.719 | 4.719 | 4.719 | 1815 | 2600
26769118 | 0.0912585 | 9.12585 | 9.12585 | 9.12585 | 3259.23 | 2800
26769119 | 0.00530673 | 0.530673 | 0.530674 | 0.530674 | 189.526 | 2800

# IfcWallStandardCase: Basic Wall:A246 - Maling KA (8)
In: Nivå D-H01
Type - PredefinedType: STANDARD; Material: A246 - ML01U _Maling kommers (302) 2 mm
ePset_Simplebim - Assembly Level: Leaf
Pset_WallCommon - Reference: Basic Wall:A246 - Maling KA
ePset_SimplebimBasicQuantities - Thickness (Simplebim): 2 mm; Height (Simplebim): 3680 mm
ePset_LocationTool - Splitting: ORIGINAL
Name (Basic Wall:A246 - Maling KA:...) | Length (Simplebim) (mm) | Area, side, gross, AABB (Simplebim) (m2) | Area, side, net, larger (Simplebim) (m2) = Area, largest surface, net (Simplebim) (m2) = Area, side, net, smaller (Simplebim) (m2) = Area, side, net, average (Simplebim) (m2) | Area, side, gross, smaller (Simplebim) (m2) = Area, side, gross, larger (Simplebim) (m2) = Area, side, gross, average (Simplebim) (m2) | Volume, net (Simplebim) (m3)
40455950 | 14920 | 54.9056 | 54.9056 | 54.9056 | 0.109811
40455951 | 2866.5 | 10.5487 | 10.5487 | 10.5487 | 0.0210974
40455952 | 5350.5 | 19.6898 | 19.6898 | 19.6898 | 0.0393797
40455959 | 1685.5 | 6.20264 | 6.20264 | 6.20264 | 0.0124053
40455960 | 6705 | 24.6744 | 24.6744 | 24.6744 | 0.0493488
40455961 | 4235.5 | 15.5866 | 15.5866 | 15.5866 | 0.0311733
40455962 | 10946 | 40.2813 | 17.4771 | 40.2819 | 0.0349542
40455963 | 8398 | 30.9046 | 26.3646 | 30.9046 | 0.0527293

# IfcWindow: Hullboring Sirkulær:V (24)
In: Nivå D
Type - ParameterTakesPrecedence: no; Sizeable: no; Material: Utsparing
OverallHeight: 200 mm
ePset_Simplebim - Assembly Level: Leaf
AVINOR - 08_Status: S4
Pset_WindowCommon - Reference: Hullboring Sirkulær:V
ePset_LocationTool - Splitting: ORIGINAL
Name (Hullboring Sirkulær:V:...) | OverallWidth (mm) | Perimeter (Simplebim) (mm) | Length, frame (Simplebim) (mm) | Height (Simplebim) (mm) | Area (Simplebim) (m2) | Width (Simplebim) (mm)
14740738 | 160 | 1120 | 960 | 400 | 0.064 | 160
14740870 | 100 | 1000 | 900 | 400 | 0.04 | 100
14740883 | 140 | 1080 | 940 | 400 | 0.056 | 140
14740899 | 100 | 1000 | 900 | 400 | 0.04 | 100
14740913 | 140 | 1080 | 940 | 400 | 0.056 | 140
14740935 | 140 | 1080 | 940 | 400 | 0.056 | 140
14740977 | 200 | 1200 | 1000 | 400 | 0.08 | 200
14768914 | 100 | 1500 | 1400 | 650 | 0.065 | 100
14768917 | 100 | 1500 | 1400 | 650 | 0.065 | 100
14768920 | 100 | 1500 | 1400 | 650 | 0.065 | 100
14768923 | 100 | 1500 | 1400 | 650 | 0.065 | 100
14769820 | 100 | 1460 | 1380 | 650 | 0.052 | 80
14769846 | 140 | 1580 | 1440 | 650 | 0.091 | 140
14769873 | 160 | 1620 | 1460 | 650 | 0.104 | 160
15621736 | 140 | 1080 | 940 | 400 | 0.056 | 140
16242262 | 160 | 1620 | 1460 | 650 | 0.104 | 160
16242317 | 140 | 1580 | 1440 | 650 | 0.091 | 140
16242347 | 140 | 1580 | 1440 | 650 | 0.091 | 140
16242374 | 140 | 1580 | 1440 | 650 | 0.091 | 140
16242414 | 160 | 1620 | 1460 | 650 | 0.104 | 160
16242457 | 140 | 1580 | 1440 | 650 | 0.091 | 140
16242489 | 140 | 1580 | 1440 | 650 | 0.091 | 140
16242530 | 100 | 1500 | 1400 | 650 | 0.065 | 100
16242559 | 100 | 1500 | 1400 | 650 | 0.065 | 100

# IfcWindow: Utsparing Rektangulær:V (3)
In: Nivå D
Type - ParameterTakesPrecedence: no; Sizeable: no; Material: Utsparing
ePset_LocationTool - Splitting: ORIGINAL
ePset_Simplebim - Assembly Level: Leaf
Pset_WindowCommon - Reference: Utsparing Rektangulær:V
AVINOR - 08_Status: S4
ePset_SimplebimBasicQuantities - Height (Simplebim): 400 mm
Name (Utsparing Rektangulær:V:...) | OverallHeight (mm) | OverallWidth (mm) | Perimeter (Simplebim) (mm) | Length, frame (Simplebim) (mm) | Area (Simplebim) (m2) | Width (Simplebim) (mm)
14740784 | 1200 | 1200 | 3000 | 1900 | 0.44 | 1100
14741161 | 1200 | 1200 | 3000 | 1900 | 0.44 | 1100
14741200 | 1550 | 1300 | 3699.99 | 2250 | 0.579998 | 1450

# IfcWindow: Utsparing Sirkulær:V, Utsparing Sirkulær:V:14740996
In: Nivå D
Type - ParameterTakesPrecedence: no; Sizeable: no; Material: Utsparing
OverallHeight: 560 mm; OverallWidth: 560 mm
ePset_Simplebim - Assembly Level: Leaf
AVINOR - 08_Status: S4
ePset_SimplebimBasicQuantities - Perimeter (Simplebim): 1920 mm; Length, frame (Simplebim): 1360 mm; Height (Simplebim): 400 mm; Area (Simplebim): 0.224 m2; Width (Simplebim): 560 mm
Pset_WindowCommon - Reference: Utsparing Sirkulær:V
ePset_LocationTool - Splitting: ORIGINAL
